(* Logix 5000 project; controller Electronic_Displays vendor 1 type 14 code 65 rev 17.4; software revision 17.01; part 2 of 8 *)

ADD_ON_INSTRUCTION ResetSign   (* revision 1.0, ExecuteEnableInFalse *)
// Reset Sign
// Erases All
// Variable Memory
// Revision note:
// Original Release
// 11-01-2012
// c.elston
VAR_IN_OUT
   Address : STRING; {required}   // "00" = all signs "01" = address 01 "02" = address 02 etc...(see protocol)
END_VAR
VAR_OUTPUT
   EN : BOOL; {visible}   // Instruction Interface Enable Bit
   DN : BOOL; {visible}   // Instruction Interface Done Bit
   ER : BOOL; {visible}   // Instruction Interface Error Bit
   IP : BOOL; {visible}   // Instruction Interface InProcess Bit
END_VAR
VAR_IN_OUT
   map_SignInput : SINT[32]; {required}   // Ethernet/IP LEDSIGN.I Data I/O Mapping
   map_SignOutput : SINT[496]; {required}   // Ethernet/IP LEDSIGN.O Data I/O Mapping
   Packet1Sent : STRING; {required}   // The actual packet sent to the sign (Packet1)
   Packet2Sent : STRING; {required}   // The actual packet sent to the sign (Packet2)
   Packet3Sent : STRING; {required}   // The actual packet sent to the sign (Packet3)
END_VAR
VAR
   SEQ : DINT;   // Sequence Number
   OktoCycle : BOOL;   // Ok to Cycle
   InCycle : BOOL;   // Incycle
   Error : BOOL;   // Error
   Enabled : BOOL;   // Enable ON Bit
   Done : BOOL;   // Done
   Disabled : BOOL;   // Disabled OFF Bit
   SignETX : STRING := '^C';   // DO NOT EDIT = ^C
   SignFileLabel : STRING;
   SignSOH : STRING := '^A';   // DO NOT EDIT = ^A
   SignAddress : STRING;
   SignSTX : STRING := '^B';   // DO NOT EDIT = ^B
   SignNULL : STRING;
   SignResetMemoryCommand : STRING := 'CM';   // DO NOT EDIT = SM
   SignCommandCode : STRING := 'C';   // DO NOT EDIT = C
   TotalPacketCount : DINT[7];   // Total Character Count
   Select : DINT;   // Packet Array Select
   PacketMax : DINT := 82;   // Max Packet Count
   PacketCount : DINT[7];
   Packet6Offset : DINT;
   Packet5Offset : DINT;
   Packet4Offset : DINT;
   Packet3Offset : DINT;
   Packet2Offset : DINT;
   Packet1Offset : DINT;
   Packet : STRING[7];   // Packet Array to send to sign
END_VAR

ROUTINE EnableInFalse   (* ladder *)
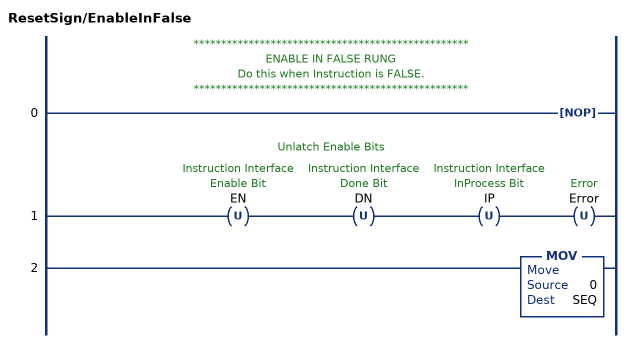
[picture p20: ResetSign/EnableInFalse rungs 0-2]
   // **************************************************
   // ENABLE IN FALSE RUNG
   // Do this when Instruction is FALSE.
   // **************************************************
   0: NOP();
   // Unlatch Enable Bits
   1: OTU(EN)OTU(DN)OTU(IP)OTU(Error);
   2: MOV(0,SEQ);
END_ROUTINE

ROUTINE Logic   (* ladder *)
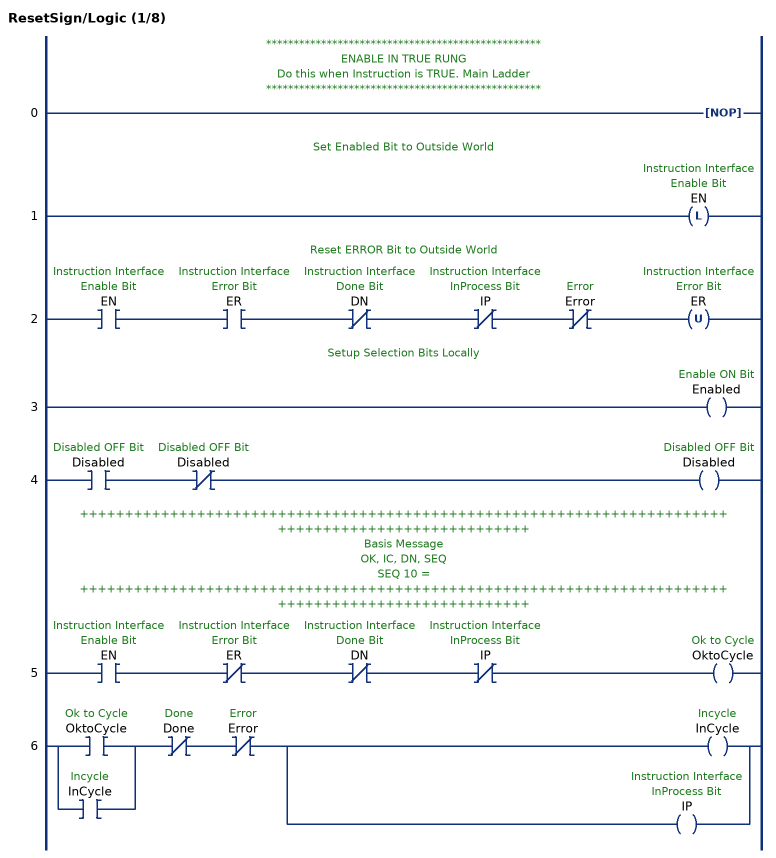
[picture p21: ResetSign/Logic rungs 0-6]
   // **************************************************
   // ENABLE IN TRUE RUNG
   // Do this when Instruction is TRUE. Main Ladder
   // **************************************************
   0: NOP();
   // Set Enabled Bit to Outside World
   1: OTL(EN);
   // Reset ERROR Bit to Outside World
   2: XIC(EN)XIC(ER)XIO(DN)XIO(IP)XIO(Error)OTU(ER);
   // Setup Selection Bits Locally
   3: OTE(Enabled);
   4: XIC(Disabled)XIO(Disabled)OTE(Disabled);
   // ++++++++++++++++++++++++++++++++++++++++++++++++++++++++++++++++++++++++++++++++++++++++++++++++++++
   // Basis Message
   // OK, IC, DN, SEQ
   // SEQ 10 =
   // ++++++++++++++++++++++++++++++++++++++++++++++++++++++++++++++++++++++++++++++++++++++++++++++++++++
   5: XIC(EN)XIO(ER)XIO(DN)XIO(IP)OTE(OktoCycle);
   6: [XIC(OktoCycle) ,XIC(InCycle) ]XIO(Done)XIO(Error)[OTE(InCycle) ,OTE(IP) ];
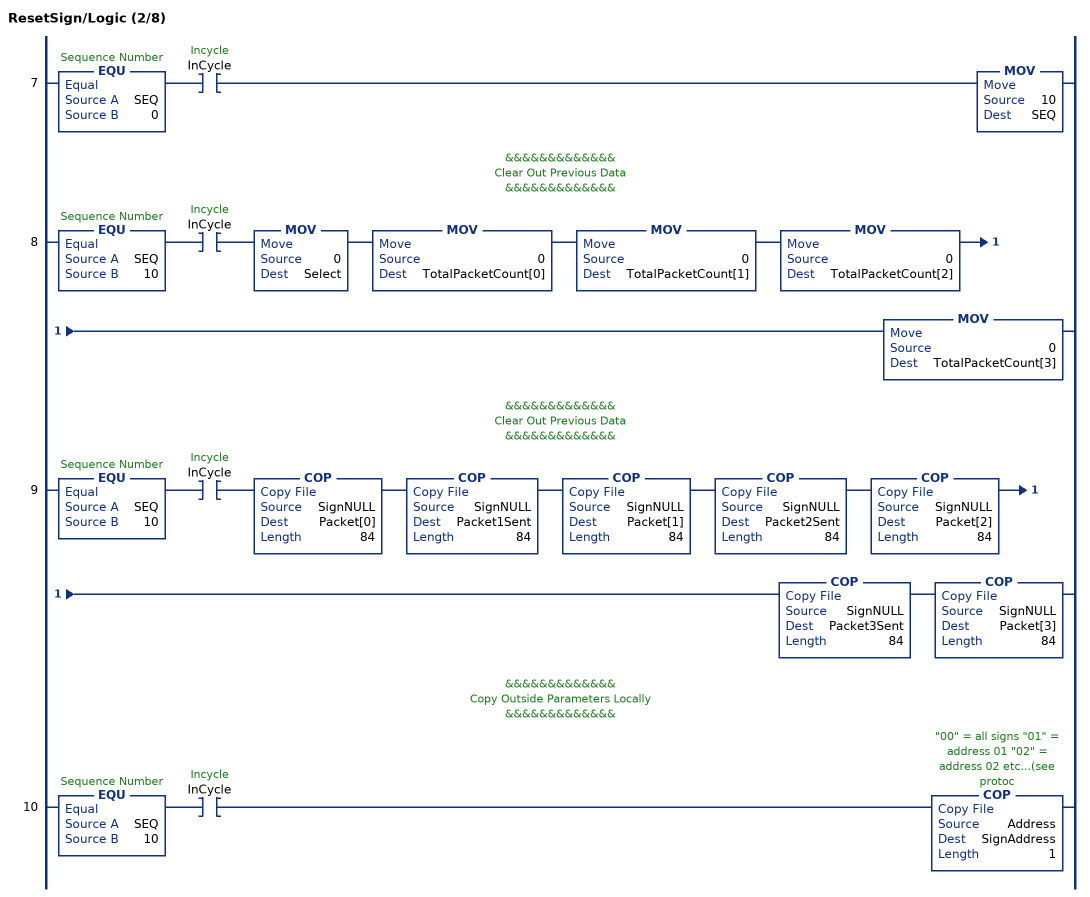
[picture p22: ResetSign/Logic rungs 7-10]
   7: EQU(SEQ,0)XIC(InCycle)MOV(10,SEQ);
   // &&&&&&&&&&&&&
   // Clear Out Previous Data
   // &&&&&&&&&&&&&
   8: EQU(SEQ,10)XIC(InCycle)MOV(0,Select)MOV(0,TotalPacketCount[0])MOV(0,TotalPacketCount[1])MOV(0,TotalPacketCount[2])MOV(0,TotalPacketCount[3]);
   // &&&&&&&&&&&&&
   // Clear Out Previous Data
   // &&&&&&&&&&&&&
   9: EQU(SEQ,10)XIC(InCycle)COP(SignNULL,Packet[0],84)COP(SignNULL,Packet1Sent,84)COP(SignNULL,Packet[1],84)COP(SignNULL,Packet2Sent,84)COP(SignNULL,Packet[2],84)COP(SignNULL,Packet3Sent,84)COP(SignNULL,Packet[3],84);
   // &&&&&&&&&&&&&
   // Copy Outside Parameters Locally
   // &&&&&&&&&&&&&
   10: EQU(SEQ,10)XIC(InCycle)COP(Address,SignAddress,1);
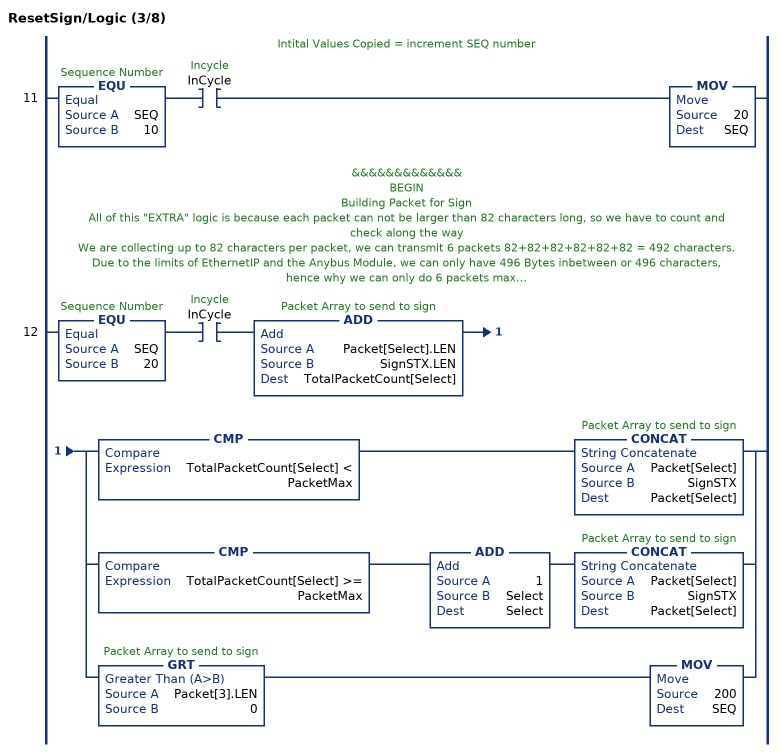
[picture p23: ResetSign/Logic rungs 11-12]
   // Intital Values Copied = increment SEQ number
   11: EQU(SEQ,10)XIC(InCycle)MOV(20,SEQ);
   // &&&&&&&&&&&&&
   // BEGIN
   // Building Packet for Sign
   // All of this "EXTRA" logic is because each packet can not be larger than 82 characters long, so we have to count and check along the way
   // We are collecting up to 82 characters per packet, we can transmit 6 packets 82+82+82+82+82+82 = 492 characters.
   // Due to the limits of EthernetIP and the Anybus Module, we can only have 496 Bytes inbetween or 496 characters, hence why we can only do 6 packets max.
   // Once we exceed this, we will fault and ERROR trap any windy typing people.
   // In this instruction below, it's so small, we are only using 3 packets max.
   // &&&&&&&&&&&&&
   12: EQU(SEQ,20)XIC(InCycle)ADD(Packet[Select].LEN,SignSTX.LEN,TotalPacketCount[Select])[CMP(TotalPacketCount[Select] < PacketMax) CONCAT(Packet[Select],SignSTX,Packet[Select]) ,CMP(TotalPacketCount[Select] >= PacketMax) ADD(1,Select,Select) CONCAT(Packet[Select],SignSTX,Packet[Select]) ,GRT(Packet[3].LEN,0) MOV(200,SEQ) ];
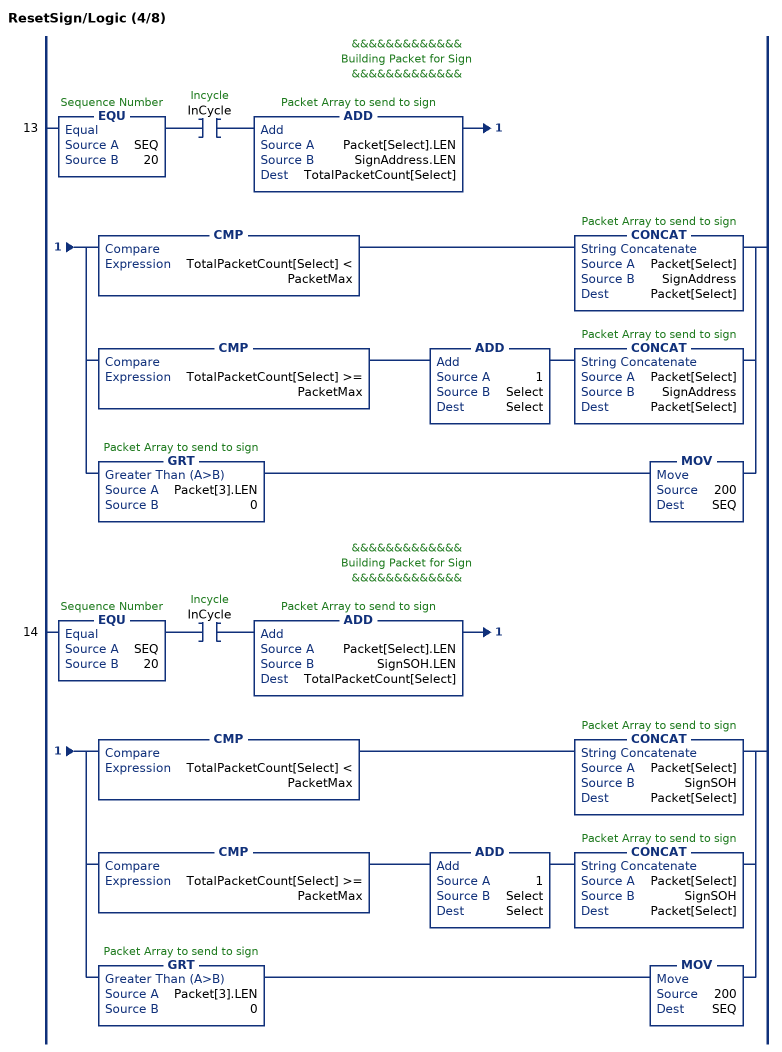
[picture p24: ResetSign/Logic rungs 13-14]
   // &&&&&&&&&&&&&
   // Building Packet for Sign
   // &&&&&&&&&&&&&
   13: EQU(SEQ,20)XIC(InCycle)ADD(Packet[Select].LEN,SignAddress.LEN,TotalPacketCount[Select])[CMP(TotalPacketCount[Select] < PacketMax) CONCAT(Packet[Select],SignAddress,Packet[Select]) ,CMP(TotalPacketCount[Select] >= PacketMax) ADD(1,Select,Select) CONCAT(Packet[Select],SignAddress,Packet[Select]) ,GRT(Packet[3].LEN,0) MOV(200,SEQ) ];
   // &&&&&&&&&&&&&
   // Building Packet for Sign
   // &&&&&&&&&&&&&
   14: EQU(SEQ,20)XIC(InCycle)ADD(Packet[Select].LEN,SignSOH.LEN,TotalPacketCount[Select])[CMP(TotalPacketCount[Select] < PacketMax) CONCAT(Packet[Select],SignSOH,Packet[Select]) ,CMP(TotalPacketCount[Select] >= PacketMax) ADD(1,Select,Select) CONCAT(Packet[Select],SignSOH,Packet[Select]) ,GRT(Packet[3].LEN,0) MOV(200,SEQ) ];
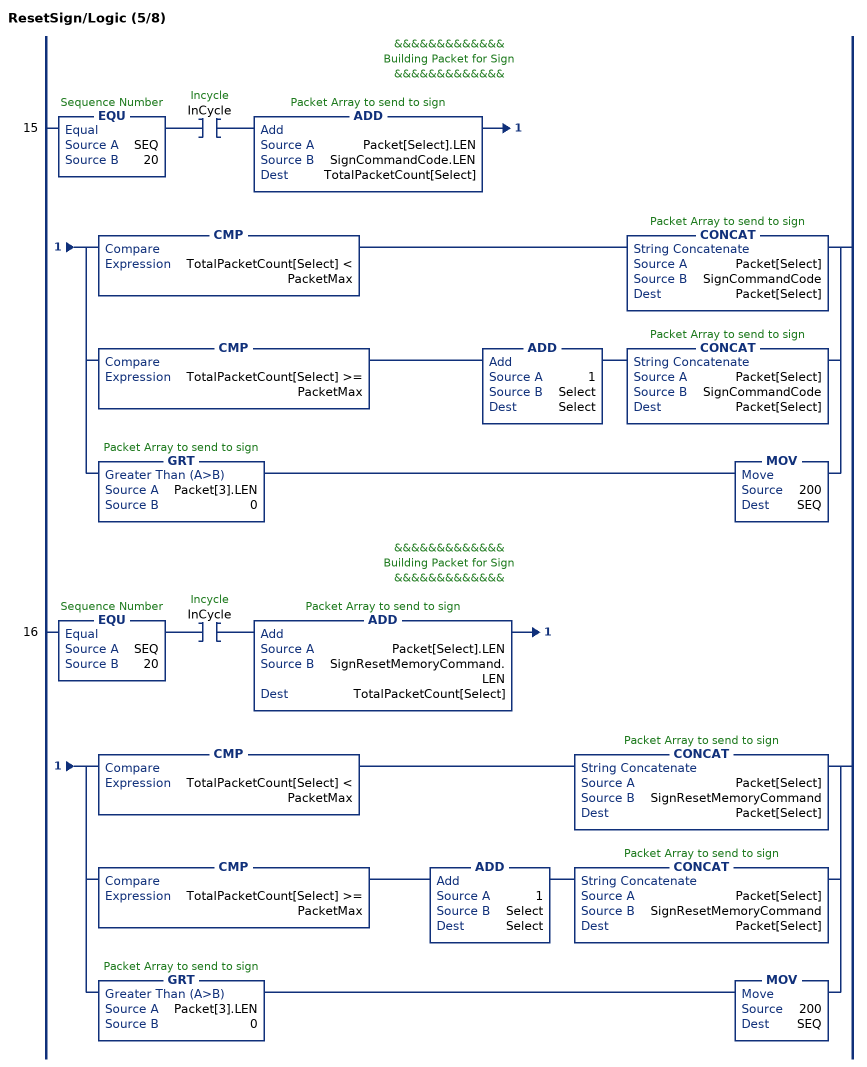
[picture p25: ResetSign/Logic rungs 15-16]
   // &&&&&&&&&&&&&
   // Building Packet for Sign
   // &&&&&&&&&&&&&
   15: EQU(SEQ,20)XIC(InCycle)ADD(Packet[Select].LEN,SignCommandCode.LEN,TotalPacketCount[Select])[CMP(TotalPacketCount[Select] < PacketMax) CONCAT(Packet[Select],SignCommandCode,Packet[Select]) ,CMP(TotalPacketCount[Select] >= PacketMax) ADD(1,Select,Select) CONCAT(Packet[Select],SignCommandCode,Packet[Select]) ,GRT(Packet[3].LEN,0) MOV(200,SEQ) ];
   // &&&&&&&&&&&&&
   // Building Packet for Sign
   // &&&&&&&&&&&&&
   16: EQU(SEQ,20)XIC(InCycle)ADD(Packet[Select].LEN,SignResetMemoryCommand.LEN,TotalPacketCount[Select])[CMP(TotalPacketCount[Select] < PacketMax) CONCAT(Packet[Select],SignResetMemoryCommand,Packet[Select]) ,CMP(TotalPacketCount[Select] >= PacketMax) ADD(1,Select,Select) CONCAT(Packet[Select],SignResetMemoryCommand,Packet[Select]) ,GRT(Packet[3].LEN,0) MOV(200,SEQ) ];
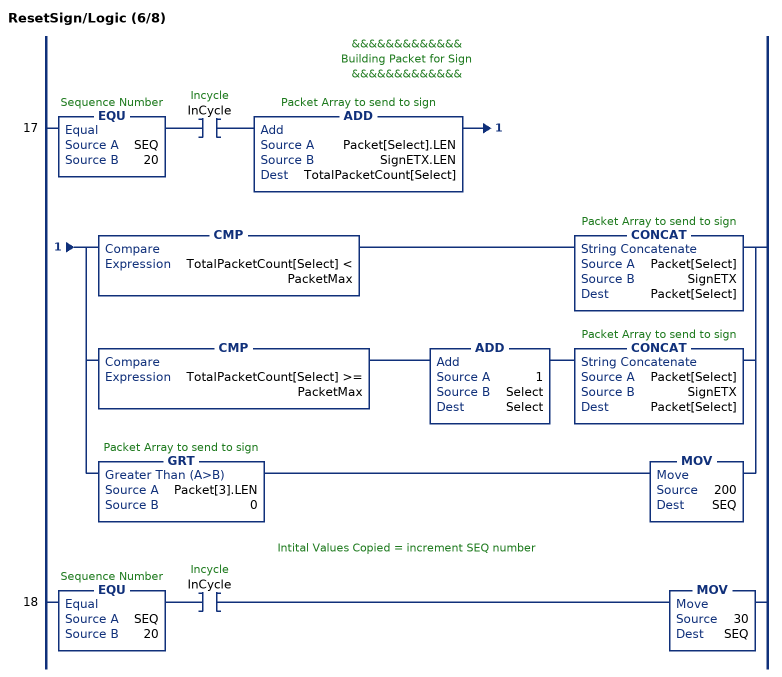
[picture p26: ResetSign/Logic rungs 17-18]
   // &&&&&&&&&&&&&
   // Building Packet for Sign
   // &&&&&&&&&&&&&
   17: EQU(SEQ,20)XIC(InCycle)ADD(Packet[Select].LEN,SignETX.LEN,TotalPacketCount[Select])[CMP(TotalPacketCount[Select] < PacketMax) CONCAT(Packet[Select],SignETX,Packet[Select]) ,CMP(TotalPacketCount[Select] >= PacketMax) ADD(1,Select,Select) CONCAT(Packet[Select],SignETX,Packet[Select]) ,GRT(Packet[3].LEN,0) MOV(200,SEQ) ];
   // Intital Values Copied = increment SEQ number
   18: EQU(SEQ,20)XIC(InCycle)MOV(30,SEQ);
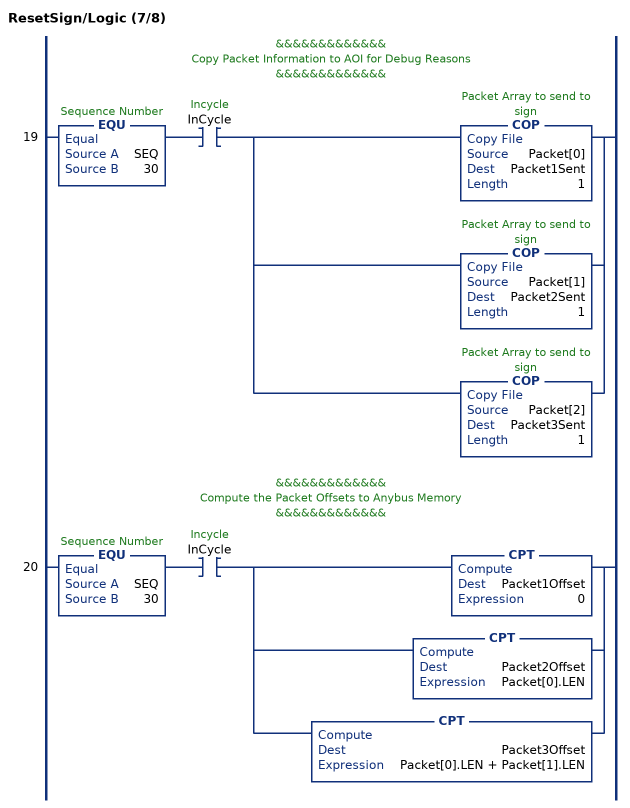
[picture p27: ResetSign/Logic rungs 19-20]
   // &&&&&&&&&&&&&
   // Copy Packet Information to AOI for Debug Reasons
   // &&&&&&&&&&&&&
   19: EQU(SEQ,30)XIC(InCycle)[COP(Packet[0],Packet1Sent,1) ,COP(Packet[1],Packet2Sent,1) ,COP(Packet[2],Packet3Sent,1) ];
   // &&&&&&&&&&&&&
   // Compute the Packet Offsets to Anybus Memory
   // &&&&&&&&&&&&&
   20: EQU(SEQ,30)XIC(InCycle)[CPT(Packet1Offset,0) ,CPT(Packet2Offset,Packet[0].LEN) ,CPT(Packet3Offset,Packet[0].LEN + Packet[1].LEN) ];
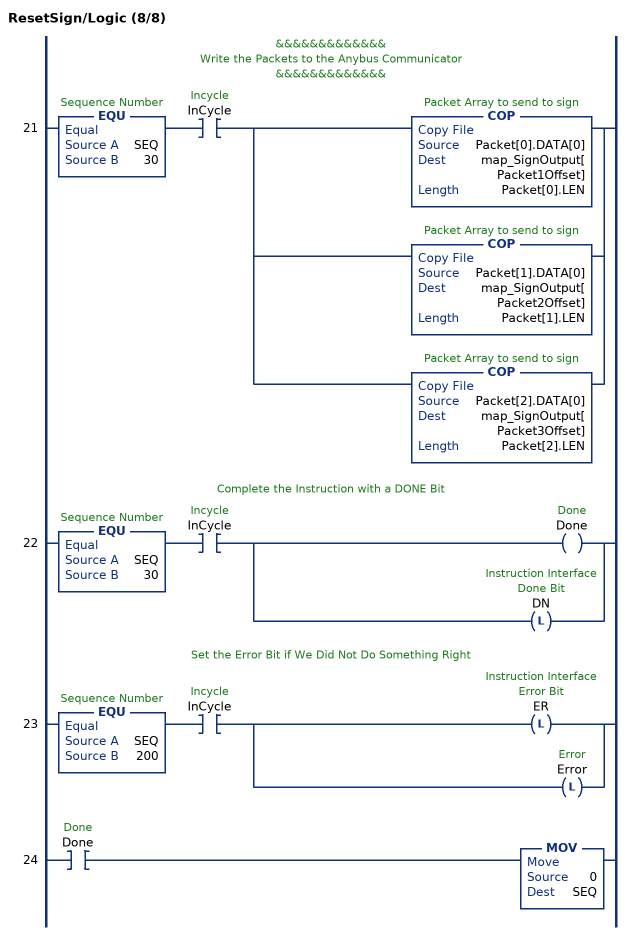
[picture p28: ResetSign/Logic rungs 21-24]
   // &&&&&&&&&&&&&
   // Write the Packets to the Anybus Communicator
   // &&&&&&&&&&&&&
   21: EQU(SEQ,30)XIC(InCycle)[COP(Packet[0].DATA[0],map_SignOutput[Packet1Offset],Packet[0].LEN) ,COP(Packet[1].DATA[0],map_SignOutput[Packet2Offset],Packet[1].LEN) ,COP(Packet[2].DATA[0],map_SignOutput[Packet3Offset],Packet[2].LEN) ];
   // Complete the Instruction with a DONE Bit
   22: EQU(SEQ,30)XIC(InCycle)[OTE(Done) ,OTL(DN) ];
   // Set the Error Bit if We Did Not Do Something Right
   23: EQU(SEQ,200)XIC(InCycle)[OTL(ER) ,OTL(Error) ];
   24: XIC(Done)MOV(0,SEQ);
END_ROUTINE
END_ADD_ON_INSTRUCTION

ADD_ON_INSTRUCTION SendSignMessage   (* revision 1.0, ExecuteEnableInFalse *)
// Send up to
// Four Lines
// to LED Sign
// Revision note:
// Original Release
// 11-01-2012
// c.elston
VAR_IN_OUT
   Address : STRING; {required}   // "00" = all signs "01" = address 01 "02" = address 02 etc...(see protocol)
   CommandCode : STRING; {required}   // "A" = text "B" = variable "C" = special "D" = text,norestart etc...(see protocol)
   FileLabel : STRING; {required}   // "A" = default etc...(see protocol)
END_VAR
VAR_INPUT
   ENText1Message : BOOL; {visible}   // 0 = don't sent message 1 = send message
END_VAR
VAR_IN_OUT
   Text1Message : STRING; {required}   // Actual Text Message to be Written to Screen (Line 1) 4 x 1 configuration
END_VAR
VAR_INPUT
   ENText2Message : BOOL; {visible}   // 0 = don't sent message 1 = send message
END_VAR
VAR_IN_OUT
   Text2Message : STRING; {required}   // Actual Text Message to be Written to Screen (Line 2) 4 x 1 configuration
END_VAR
VAR_INPUT
   ENText3Message : BOOL; {visible}   // 0 = don't sent message 1 = send message
END_VAR
VAR_IN_OUT
   Text3Message : STRING; {required}   // Actual Text Message to be Written to Screen (Line 3) 4 x 1 configuration
END_VAR
VAR_INPUT
   ENText4Message : BOOL; {visible}   // 0 = don't sent message 1 = send message
END_VAR
VAR_IN_OUT
   Text4Message : STRING; {required}   // Actual Text Message to be Written to Screen (Line 4) 4 x 1 configuration
END_VAR
VAR_INPUT
   ENTextFormats : BOOL; {visible}   // 0 = no additional text formatting 1 = enable text formatting
END_VAR
VAR_IN_OUT
   TextFont : STRING; {required}   // "0" = default "1" = SF7 "2" = SF10 "3" = SS16 "4" = SF16
   TextColor : STRING; {required}   // "0" = Red (default) "1" = Green "2" = Yellow "3" = Rainbow1
   TextAlign : STRING; {required}   // "M"=middle line "T"=top line "B"=bottom line "F"=fill (best for variables) "L"=left "R"=right
   TextAttribute : STRING; {required}   // "0"=flashing off "1"=flashing on "2"=wide off "3"=wide on "4"=bold off "5"=bold on
END_VAR
VAR_INPUT
   ENTextSpecials : BOOL; {visible}   // 0 = no additional text special formatting 1 = enable text special formatting
END_VAR
VAR_IN_OUT
   TextEffect : STRING; {required}   // "S"=scrolls "H"=hold "F"=flash "A"=slide up "B"=slide down "C"=slide left "D"=slide right "a"=roll up "b"=roll down "c"=roll left "d"=roll right
   TextSpeed : STRING; {required}   // 1 - 8 "3" = Default (see protocol)
   TextPause : STRING; {required}   // 00 - 99 "02" = Default (see protocol) [must be two digits] if not will not work!
END_VAR
VAR_INPUT
   ENVariable1Message : BOOL; {visible}   // 0 = don't sent embedded variable 1 = send embedded variable
END_VAR
VAR_IN_OUT
   Variable1Name : STRING; {required}   // Name of variable Default is = U
END_VAR
VAR_INPUT
   ENVariable2Message : BOOL; {visible}   // 0 = don't sent embedded variable 1 = send embedded variable
END_VAR
VAR_IN_OUT
   Variable2Name : STRING; {required}   // Name of variable Default is = V
END_VAR
VAR_INPUT
   ENVariable3Message : BOOL; {visible}   // 0 = don't sent embedded variable 1 = send embedded variable
END_VAR
VAR_IN_OUT
   Variable3Name : STRING; {required}   // Name of variable Default is = W
END_VAR
VAR_INPUT
   ENVariable4Message : BOOL; {visible}   // 0 = don't sent embedded variable 1 = send embedded variable
END_VAR
VAR_IN_OUT
   Variable4Name : STRING; {required}   // Name of variable Default is = X
END_VAR
VAR_INPUT
   ENVariableFormats : BOOL; {visible}   // 0 = no additional text formatting 1 = enable text formatting
END_VAR
VAR_IN_OUT
   VariableFont : STRING; {required}   // "0" = default "1" = SF7 "2" = SF10 "3" = SS16 "4" = SF16 etc...(see protocol)
   VariableColor : STRING; {required}   // "0" = Red (default) "1" = Green "2" = Yellow "3" = Rainbow1
   VariableAttribute : STRING; {required}   // "0"=flashing off "1"=flashing on "2"=wide off "3"=wide on "4"=bold off "5"=bold on
END_VAR
VAR_OUTPUT
   EN : BOOL; {visible}   // Instruction Interface Enable Bit
   DN : BOOL; {visible}   // Instruction Interface Done Bit
   IP : BOOL; {visible}   // Instruction Interface InProcess Bit
   ER : BOOL; {visible}   // Instruction Interface Error Bit
END_VAR
VAR_IN_OUT
   map_SignInput : SINT[32]; {required}   // Ethernet/IP LEDSIGN.I Data I/O Mapping
   map_SignOutput : SINT[496]; {required}   // Ethernet/IP LEDSIGN.O Data I/O Mapping
   Packet1Sent : STRING; {required}   // The actual packet sent to the sign (Packet1)
   Packet2Sent : STRING; {required}   // The actual packet sent to the sign (Packet2)
   Packet3Sent : STRING; {required}   // The actual packet sent to the sign (Packet3)
   Packet4Sent : STRING; {required}   // The actual packet sent to the sign (Packet4)
   Packet5Sent : STRING; {required}   // The actual packet sent to the sign (Packet5)
   Packet6Sent : STRING; {required}   // The actual packet sent to the sign (Packet6)
END_VAR
VAR
   SEQ : DINT;   // Sequence Number
   OktoCycle : BOOL;   // Ok to Cycle
   InCycle : BOOL;   // Incycle
   Error : BOOL;   // Error
   Enabled : BOOL;   // Enable ON Bit
   Done : BOOL;   // Done
   Disabled : BOOL;   // Disabled OFF Bit
   SignETX : STRING := '^C';   // DO NOT EDIT = ^C
   SignTextMessage1 : STRING;
   SignColor : STRING;
   SignFont : STRING;
   SignFileLabel : STRING;
   SignCommandCode : STRING;
   SignSOH : STRING := '^A';   // DO NOT EDIT = ^A
   SignAddress : STRING;
   SignSTX : STRING := '^B';   // DO NOT EDIT = ^B
   Packet : STRING[7];   // Packet Array to send to sign
   SignFontCommand : STRING := '^F';   // DO NOT EDIT = ^F
   SignColorCommand : STRING := '^O';   // DO NOT EDIT = ^O
   SignAlignCommand : STRING := '^G';   // DO NOT EDIT = ^G
   SignAlign : STRING;
   SignSpeedCommand : STRING := '^I';   // DO NOT EDIT = ^I
   SignSpeed : STRING;
   SignEffectCommand : STRING := '^E';   // DO NOT EDIT = ^E
   SignEffect : STRING;
   SignPauseCommand : STRING := '^J';   // DO NOT EDIT = ^J
   SignPause : STRING;
   SignTextMessage4 : STRING;
   SignTextMessage3 : STRING;
   SignTextMessage2 : STRING;
   SignNextLine : STRING := '^M';   // DO NOT EDIT = ^M
   SignNULL : STRING;
   SignVariableFont : STRING;
   SignVariableColor : STRING;
   SignVariable4 : STRING;
   SignVariable3 : STRING;
   SignVariable2 : STRING;
   SignVariable1 : STRING;
   SignVariableCommand : STRING := '^N';   // DO NOT EDIT = ^N
   Select : DINT;   // Packet Array Select
   TotalPacketCount : DINT[7];   // Total Character Count
   PacketMax : DINT := 82;   // Max Packet Count
   PacketCount : DINT[7];
   Packet6Offset : DINT;
   Packet5Offset : DINT;
   Packet4Offset : DINT;
   Packet3Offset : DINT;
   Packet2Offset : DINT;
   Packet1Offset : DINT;
   SignMode2Command : STRING := 'H';   // DO NOT EDIT = H (make it hold)
   SignAttributeCommand : STRING := '^H';   // DO NOT EDIT = ^H
   SignAttribute : STRING;
   SignVariableAttribute : STRING;
END_VAR

ROUTINE EnableInFalse   (* ladder *)
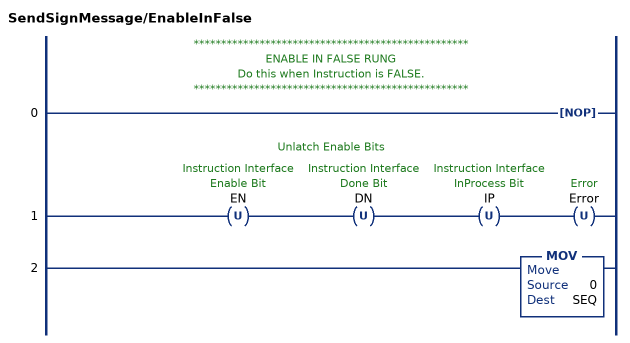
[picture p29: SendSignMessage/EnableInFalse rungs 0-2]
   // **************************************************
   // ENABLE IN FALSE RUNG
   // Do this when Instruction is FALSE.
   // **************************************************
   0: NOP();
   // Unlatch Enable Bits
   1: OTU(EN)OTU(DN)OTU(IP)OTU(Error);
   2: MOV(0,SEQ);
END_ROUTINE

ROUTINE Logic   (* ladder *)
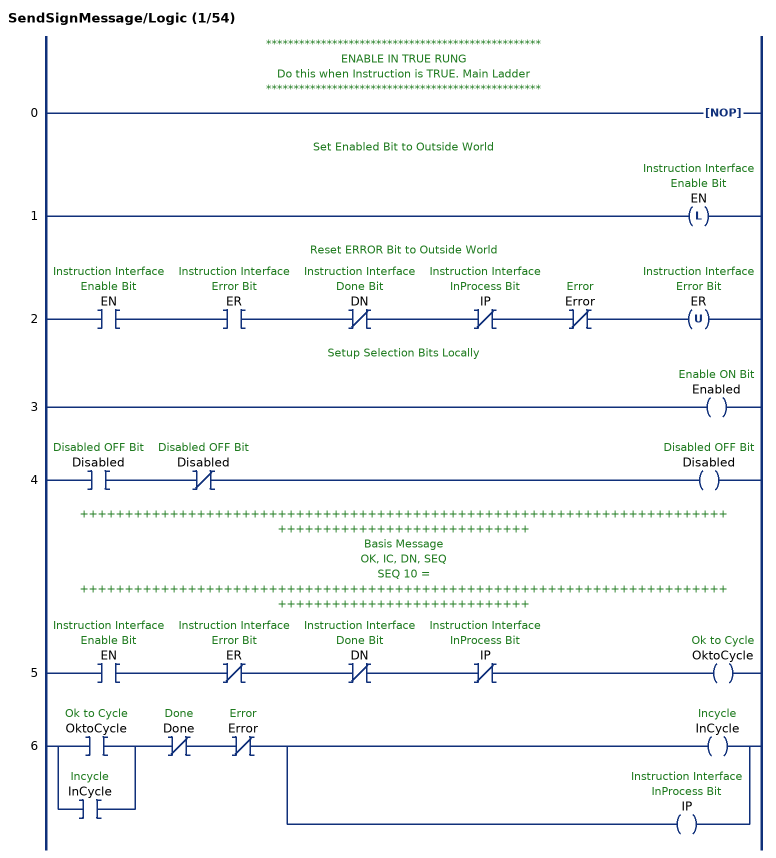
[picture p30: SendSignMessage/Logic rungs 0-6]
   // **************************************************
   // ENABLE IN TRUE RUNG
   // Do this when Instruction is TRUE. Main Ladder
   // **************************************************
   0: NOP();
   // Set Enabled Bit to Outside World
   1: OTL(EN);
   // Reset ERROR Bit to Outside World
   2: XIC(EN)XIC(ER)XIO(DN)XIO(IP)XIO(Error)OTU(ER);
   // Setup Selection Bits Locally
   3: OTE(Enabled);
   4: XIC(Disabled)XIO(Disabled)OTE(Disabled);
   // ++++++++++++++++++++++++++++++++++++++++++++++++++++++++++++++++++++++++++++++++++++++++++++++++++++
   // Basis Message
   // OK, IC, DN, SEQ
   // SEQ 10 =
   // ++++++++++++++++++++++++++++++++++++++++++++++++++++++++++++++++++++++++++++++++++++++++++++++++++++
   5: XIC(EN)XIO(ER)XIO(DN)XIO(IP)OTE(OktoCycle);
   6: [XIC(OktoCycle) ,XIC(InCycle) ]XIO(Done)XIO(Error)[OTE(InCycle) ,OTE(IP) ];
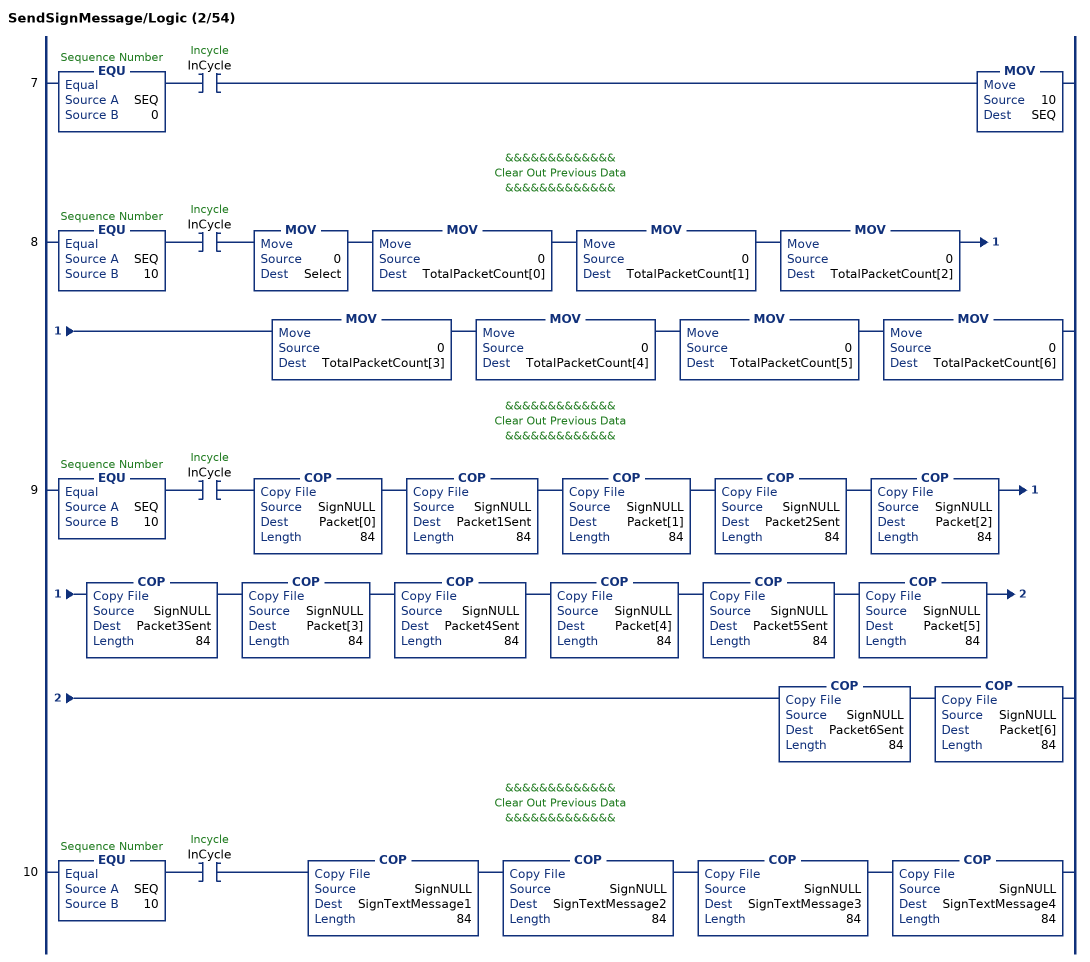
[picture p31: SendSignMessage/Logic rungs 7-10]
   7: EQU(SEQ,0)XIC(InCycle)MOV(10,SEQ);
   // &&&&&&&&&&&&&
   // Clear Out Previous Data
   // &&&&&&&&&&&&&
   8: EQU(SEQ,10)XIC(InCycle)MOV(0,Select)MOV(0,TotalPacketCount[0])MOV(0,TotalPacketCount[1])MOV(0,TotalPacketCount[2])MOV(0,TotalPacketCount[3])MOV(0,TotalPacketCount[4])MOV(0,TotalPacketCount[5])MOV(0,TotalPacketCount[6]);
   // &&&&&&&&&&&&&
   // Clear Out Previous Data
   // &&&&&&&&&&&&&
   9: EQU(SEQ,10)XIC(InCycle)COP(SignNULL,Packet[0],84)COP(SignNULL,Packet1Sent,84)COP(SignNULL,Packet[1],84)COP(SignNULL,Packet2Sent,84)COP(SignNULL,Packet[2],84)COP(SignNULL,Packet3Sent,84)COP(SignNULL,Packet[3],84)COP(SignNULL,Packet4Sent,84)COP(SignNULL,Packet[4],84)COP(SignNULL,Packet5Sent,84)COP(SignNULL,Packet[5],84)COP(SignNULL,Packet6Sent,84)COP(SignNULL,Packet[6],84);
   // &&&&&&&&&&&&&
   // Clear Out Previous Data
   // &&&&&&&&&&&&&
   10: EQU(SEQ,10)XIC(InCycle)COP(SignNULL,SignTextMessage1,84)COP(SignNULL,SignTextMessage2,84)COP(SignNULL,SignTextMessage3,84)COP(SignNULL,SignTextMessage4,84);
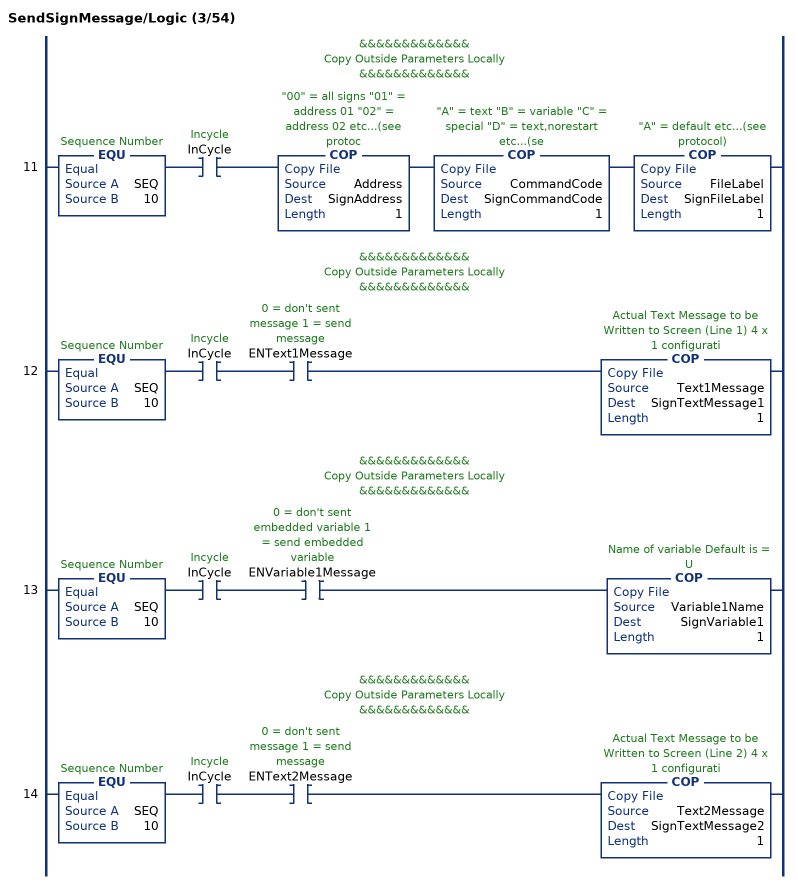
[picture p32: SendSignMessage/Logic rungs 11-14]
   // &&&&&&&&&&&&&
   // Copy Outside Parameters Locally
   // &&&&&&&&&&&&&
   11: EQU(SEQ,10)XIC(InCycle)COP(Address,SignAddress,1)COP(CommandCode,SignCommandCode,1)COP(FileLabel,SignFileLabel,1);
   // &&&&&&&&&&&&&
   // Copy Outside Parameters Locally
   // &&&&&&&&&&&&&
   12: EQU(SEQ,10)XIC(InCycle)XIC(ENText1Message)COP(Text1Message,SignTextMessage1,1);
   // &&&&&&&&&&&&&
   // Copy Outside Parameters Locally
   // &&&&&&&&&&&&&
   13: EQU(SEQ,10)XIC(InCycle)XIC(ENVariable1Message)COP(Variable1Name,SignVariable1,1);
   // &&&&&&&&&&&&&
   // Copy Outside Parameters Locally
   // &&&&&&&&&&&&&
   14: EQU(SEQ,10)XIC(InCycle)XIC(ENText2Message)COP(Text2Message,SignTextMessage2,1);
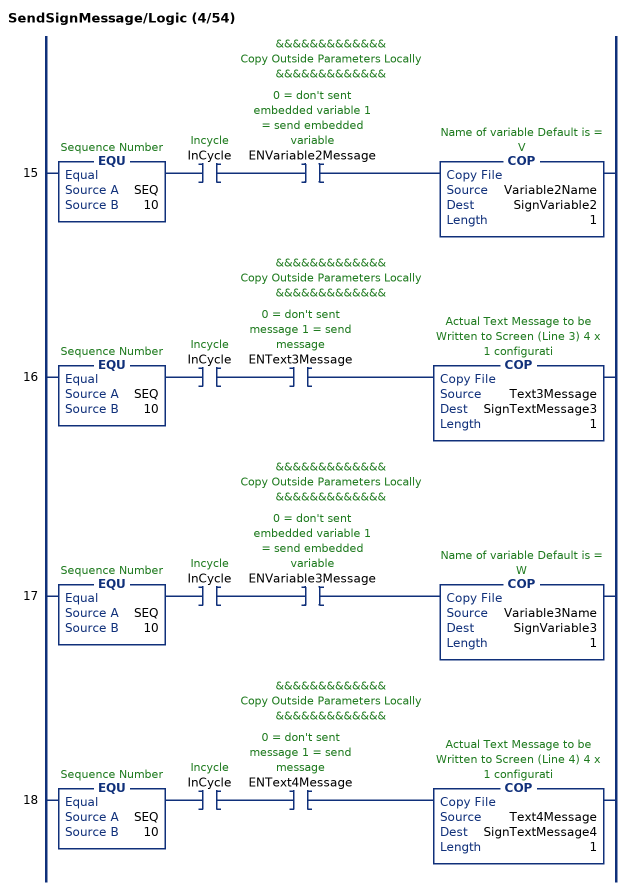
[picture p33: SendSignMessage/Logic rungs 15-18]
   // &&&&&&&&&&&&&
   // Copy Outside Parameters Locally
   // &&&&&&&&&&&&&
   15: EQU(SEQ,10)XIC(InCycle)XIC(ENVariable2Message)COP(Variable2Name,SignVariable2,1);
   // &&&&&&&&&&&&&
   // Copy Outside Parameters Locally
   // &&&&&&&&&&&&&
   16: EQU(SEQ,10)XIC(InCycle)XIC(ENText3Message)COP(Text3Message,SignTextMessage3,1);
   // &&&&&&&&&&&&&
   // Copy Outside Parameters Locally
   // &&&&&&&&&&&&&
   17: EQU(SEQ,10)XIC(InCycle)XIC(ENVariable3Message)COP(Variable3Name,SignVariable3,1);
   // &&&&&&&&&&&&&
   // Copy Outside Parameters Locally
   // &&&&&&&&&&&&&
   18: EQU(SEQ,10)XIC(InCycle)XIC(ENText4Message)COP(Text4Message,SignTextMessage4,1);
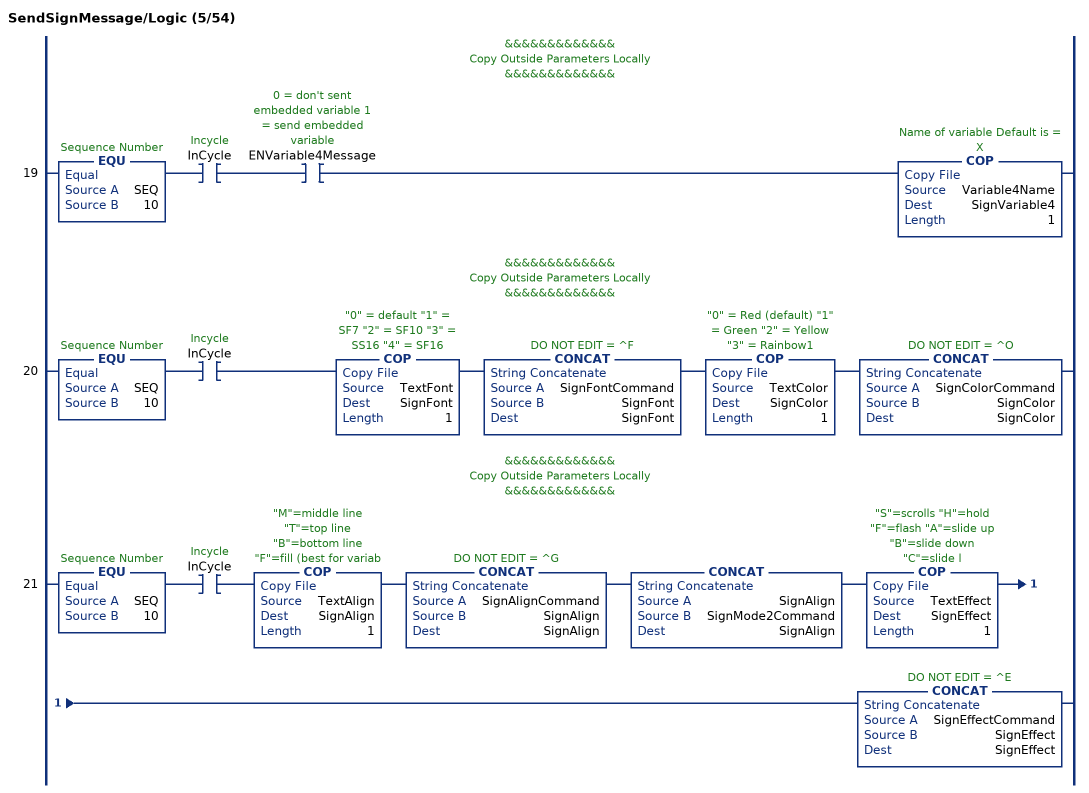
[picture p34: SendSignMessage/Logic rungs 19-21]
   // &&&&&&&&&&&&&
   // Copy Outside Parameters Locally
   // &&&&&&&&&&&&&
   19: EQU(SEQ,10)XIC(InCycle)XIC(ENVariable4Message)COP(Variable4Name,SignVariable4,1);
   // &&&&&&&&&&&&&
   // Copy Outside Parameters Locally
   // &&&&&&&&&&&&&
   20: EQU(SEQ,10)XIC(InCycle)COP(TextFont,SignFont,1)CONCAT(SignFontCommand,SignFont,SignFont)COP(TextColor,SignColor,1)CONCAT(SignColorCommand,SignColor,SignColor);
   // &&&&&&&&&&&&&
   // Copy Outside Parameters Locally
   // &&&&&&&&&&&&&
   21: EQU(SEQ,10)XIC(InCycle)COP(TextAlign,SignAlign,1)CONCAT(SignAlignCommand,SignAlign,SignAlign)CONCAT(SignAlign,SignMode2Command,SignAlign)COP(TextEffect,SignEffect,1)CONCAT(SignEffectCommand,SignEffect,SignEffect);
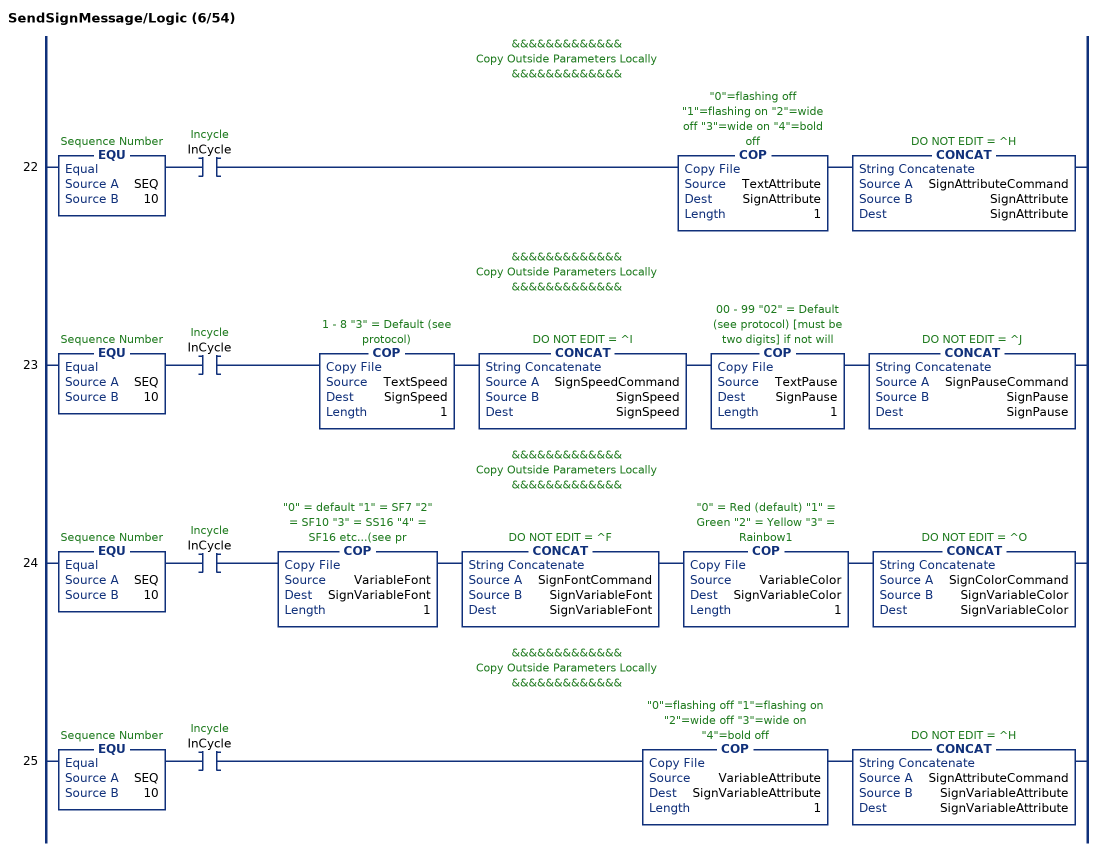
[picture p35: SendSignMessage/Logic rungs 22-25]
   // &&&&&&&&&&&&&
   // Copy Outside Parameters Locally
   // &&&&&&&&&&&&&
   22: EQU(SEQ,10)XIC(InCycle)COP(TextAttribute,SignAttribute,1)CONCAT(SignAttributeCommand,SignAttribute,SignAttribute);
   // &&&&&&&&&&&&&
   // Copy Outside Parameters Locally
   // &&&&&&&&&&&&&
   23: EQU(SEQ,10)XIC(InCycle)COP(TextSpeed,SignSpeed,1)CONCAT(SignSpeedCommand,SignSpeed,SignSpeed)COP(TextPause,SignPause,1)CONCAT(SignPauseCommand,SignPause,SignPause);
   // &&&&&&&&&&&&&
   // Copy Outside Parameters Locally
   // &&&&&&&&&&&&&
   24: EQU(SEQ,10)XIC(InCycle)COP(VariableFont,SignVariableFont,1)CONCAT(SignFontCommand,SignVariableFont,SignVariableFont)COP(VariableColor,SignVariableColor,1)CONCAT(SignColorCommand,SignVariableColor,SignVariableColor);
   // &&&&&&&&&&&&&
   // Copy Outside Parameters Locally
   // &&&&&&&&&&&&&
   25: EQU(SEQ,10)XIC(InCycle)COP(VariableAttribute,SignVariableAttribute,1)CONCAT(SignAttributeCommand,SignVariableAttribute,SignVariableAttribute);
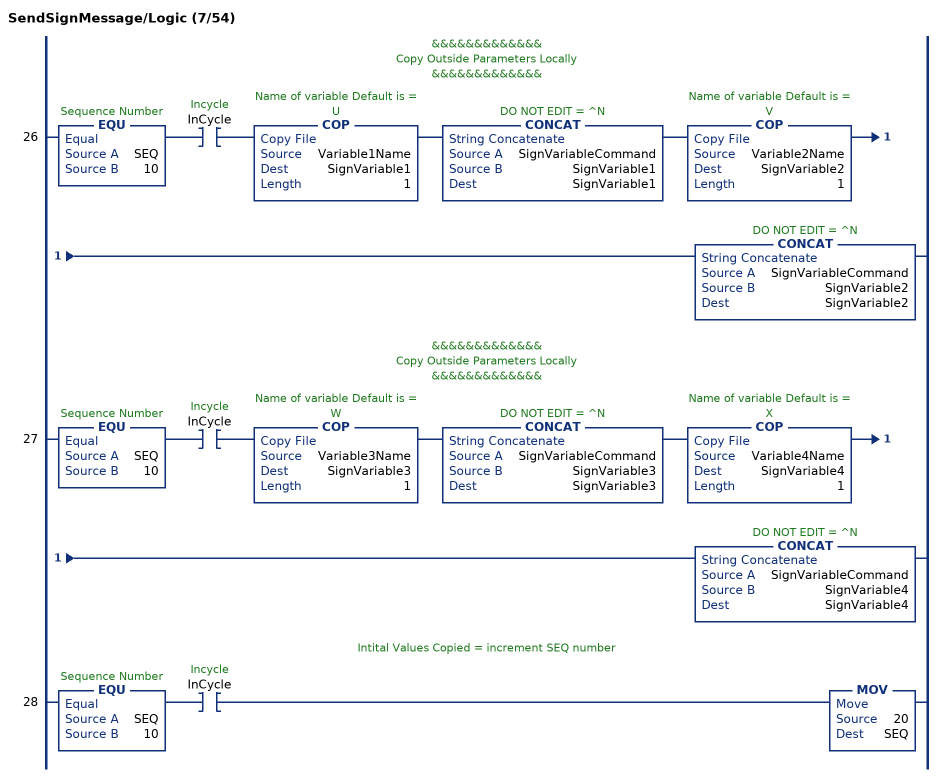
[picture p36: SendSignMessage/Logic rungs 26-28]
   // &&&&&&&&&&&&&
   // Copy Outside Parameters Locally
   // &&&&&&&&&&&&&
   26: EQU(SEQ,10)XIC(InCycle)COP(Variable1Name,SignVariable1,1)CONCAT(SignVariableCommand,SignVariable1,SignVariable1)COP(Variable2Name,SignVariable2,1)CONCAT(SignVariableCommand,SignVariable2,SignVariable2);
   // &&&&&&&&&&&&&
   // Copy Outside Parameters Locally
   // &&&&&&&&&&&&&
   27: EQU(SEQ,10)XIC(InCycle)COP(Variable3Name,SignVariable3,1)CONCAT(SignVariableCommand,SignVariable3,SignVariable3)COP(Variable4Name,SignVariable4,1)CONCAT(SignVariableCommand,SignVariable4,SignVariable4);
   // Intital Values Copied = increment SEQ number
   28: EQU(SEQ,10)XIC(InCycle)MOV(20,SEQ);
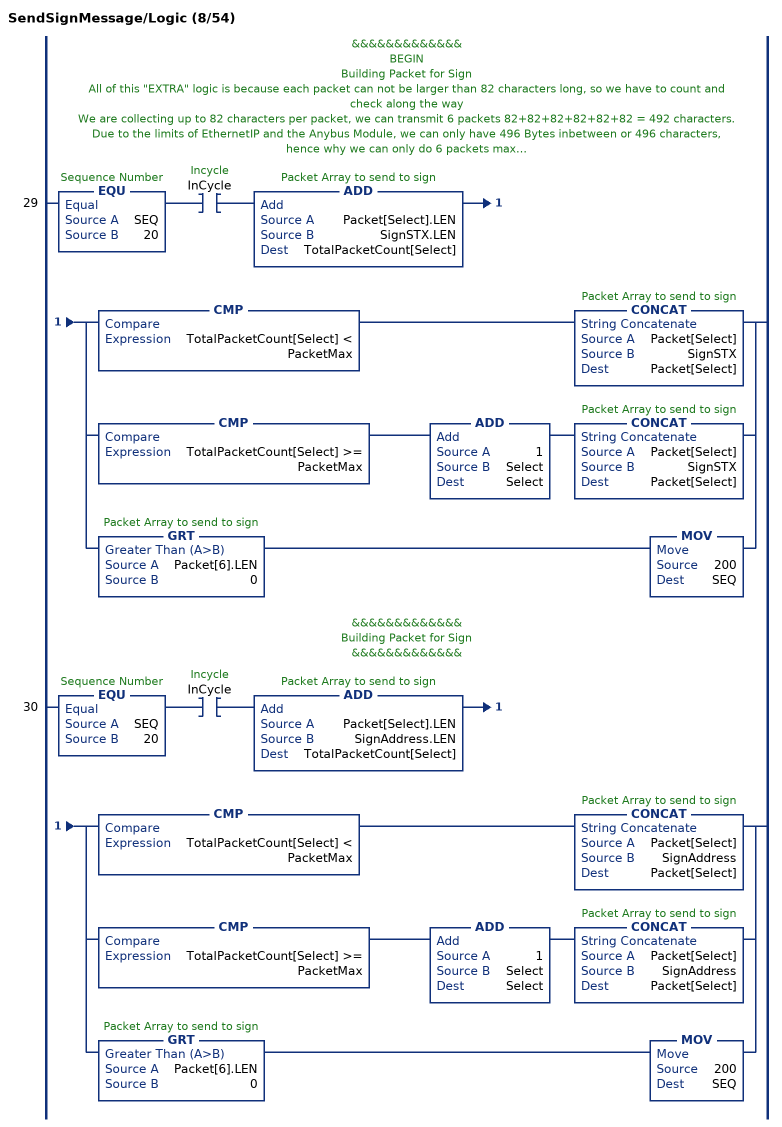
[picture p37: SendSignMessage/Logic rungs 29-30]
   // &&&&&&&&&&&&&
   // BEGIN
   // Building Packet for Sign
   // All of this "EXTRA" logic is because each packet can not be larger than 82 characters long, so we have to count and check along the way
   // We are collecting up to 82 characters per packet, we can transmit 6 packets 82+82+82+82+82+82 = 492 characters.
   // Due to the limits of EthernetIP and the Anybus Module, we can only have 496 Bytes inbetween or 496 characters, hence why we can only do 6 packets max.
   // Once we exceed this, we will fault and ERROR trap any windy typing people.
   // &&&&&&&&&&&&&
   29: EQU(SEQ,20)XIC(InCycle)ADD(Packet[Select].LEN,SignSTX.LEN,TotalPacketCount[Select])[CMP(TotalPacketCount[Select] < PacketMax) CONCAT(Packet[Select],SignSTX,Packet[Select]) ,CMP(TotalPacketCount[Select] >= PacketMax) ADD(1,Select,Select) CONCAT(Packet[Select],SignSTX,Packet[Select]) ,GRT(Packet[6].LEN,0) MOV(200,SEQ) ];
   // &&&&&&&&&&&&&
   // Building Packet for Sign
   // &&&&&&&&&&&&&
   30: EQU(SEQ,20)XIC(InCycle)ADD(Packet[Select].LEN,SignAddress.LEN,TotalPacketCount[Select])[CMP(TotalPacketCount[Select] < PacketMax) CONCAT(Packet[Select],SignAddress,Packet[Select]) ,CMP(TotalPacketCount[Select] >= PacketMax) ADD(1,Select,Select) CONCAT(Packet[Select],SignAddress,Packet[Select]) ,GRT(Packet[6].LEN,0) MOV(200,SEQ) ];
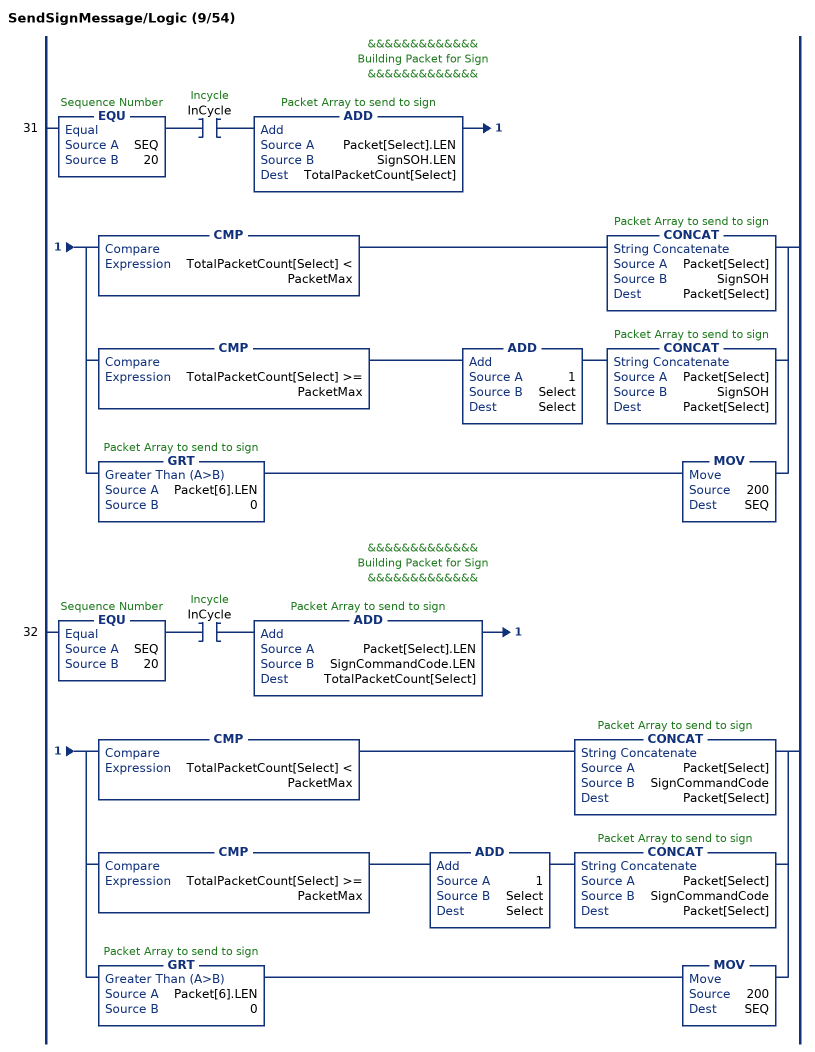
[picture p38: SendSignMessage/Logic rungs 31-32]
   // &&&&&&&&&&&&&
   // Building Packet for Sign
   // &&&&&&&&&&&&&
   31: EQU(SEQ,20)XIC(InCycle)ADD(Packet[Select].LEN,SignSOH.LEN,TotalPacketCount[Select])[CMP(TotalPacketCount[Select] < PacketMax) CONCAT(Packet[Select],SignSOH,Packet[Select]) ,CMP(TotalPacketCount[Select] >= PacketMax) ADD(1,Select,Select) CONCAT(Packet[Select],SignSOH,Packet[Select]) ,GRT(Packet[6].LEN,0) MOV(200,SEQ) ];
   // &&&&&&&&&&&&&
   // Building Packet for Sign
   // &&&&&&&&&&&&&
   32: EQU(SEQ,20)XIC(InCycle)ADD(Packet[Select].LEN,SignCommandCode.LEN,TotalPacketCount[Select])[CMP(TotalPacketCount[Select] < PacketMax) CONCAT(Packet[Select],SignCommandCode,Packet[Select]) ,CMP(TotalPacketCount[Select] >= PacketMax) ADD(1,Select,Select) CONCAT(Packet[Select],SignCommandCode,Packet[Select]) ,GRT(Packet[6].LEN,0) MOV(200,SEQ) ];
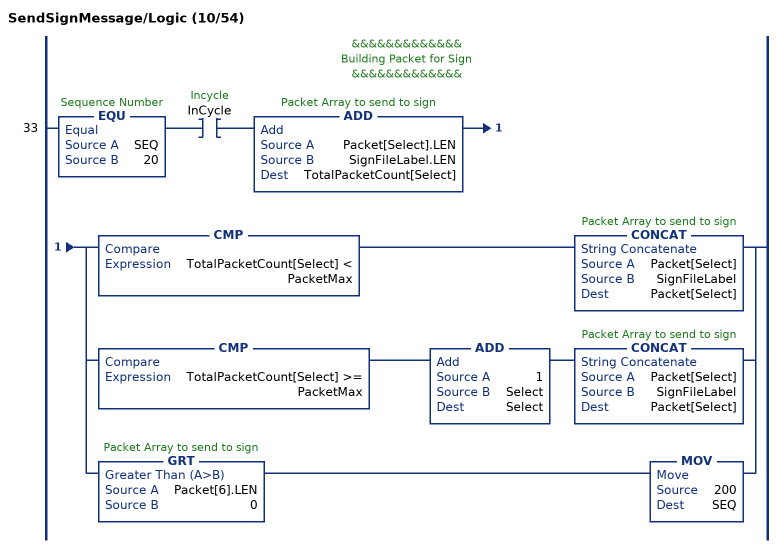
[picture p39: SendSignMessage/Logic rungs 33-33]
   // &&&&&&&&&&&&&
   // Building Packet for Sign
   // &&&&&&&&&&&&&
   33: EQU(SEQ,20)XIC(InCycle)ADD(Packet[Select].LEN,SignFileLabel.LEN,TotalPacketCount[Select])[CMP(TotalPacketCount[Select] < PacketMax) CONCAT(Packet[Select],SignFileLabel,Packet[Select]) ,CMP(TotalPacketCount[Select] >= PacketMax) ADD(1,Select,Select) CONCAT(Packet[Select],SignFileLabel,Packet[Select]) ,GRT(Packet[6].LEN,0) MOV(200,SEQ) ];
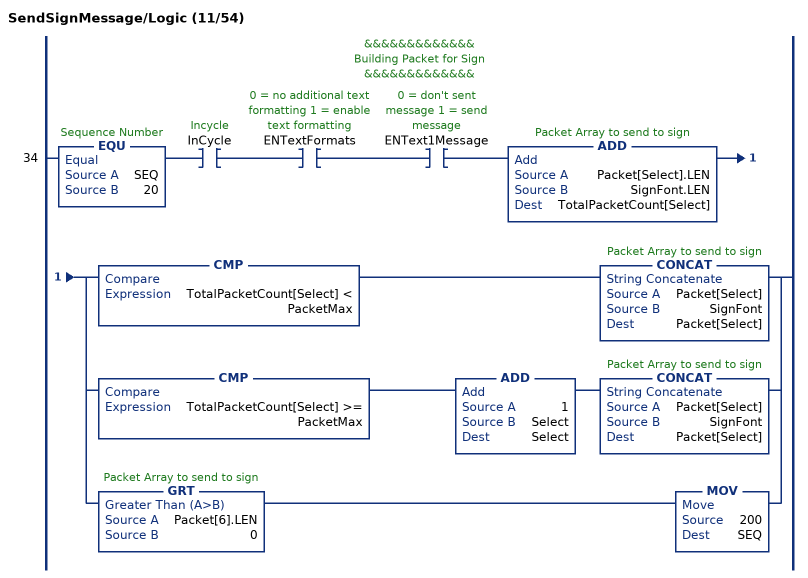
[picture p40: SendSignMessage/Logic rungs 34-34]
   // &&&&&&&&&&&&&
   // Building Packet for Sign
   // &&&&&&&&&&&&&
   34: EQU(SEQ,20)XIC(InCycle)XIC(ENTextFormats)XIC(ENText1Message)ADD(Packet[Select].LEN,SignFont.LEN,TotalPacketCount[Select])[CMP(TotalPacketCount[Select] < PacketMax) CONCAT(Packet[Select],SignFont,Packet[Select]) ,CMP(TotalPacketCount[Select] >= PacketMax) ADD(1,Select,Select) CONCAT(Packet[Select],SignFont,Packet[Select]) ,GRT(Packet[6].LEN,0) MOV(200,SEQ) ];
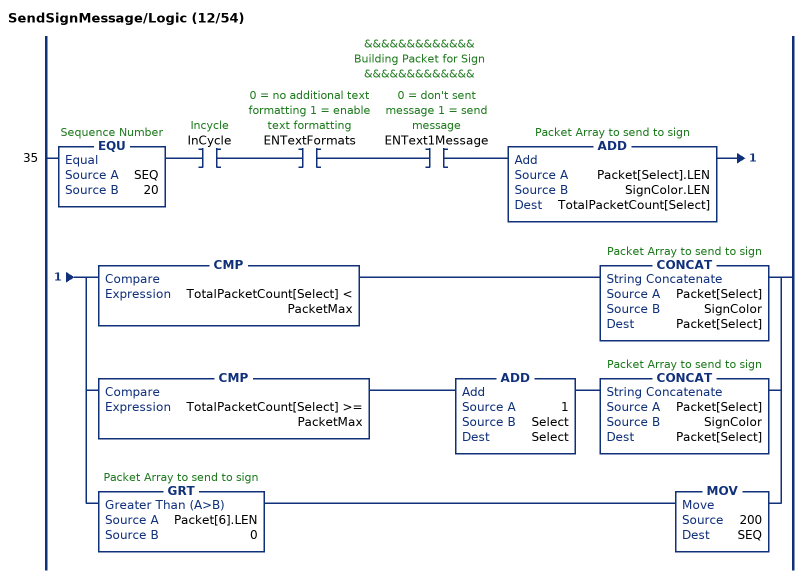
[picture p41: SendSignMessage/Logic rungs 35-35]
   // &&&&&&&&&&&&&
   // Building Packet for Sign
   // &&&&&&&&&&&&&
   35: EQU(SEQ,20)XIC(InCycle)XIC(ENTextFormats)XIC(ENText1Message)ADD(Packet[Select].LEN,SignColor.LEN,TotalPacketCount[Select])[CMP(TotalPacketCount[Select] < PacketMax) CONCAT(Packet[Select],SignColor,Packet[Select]) ,CMP(TotalPacketCount[Select] >= PacketMax) ADD(1,Select,Select) CONCAT(Packet[Select],SignColor,Packet[Select]) ,GRT(Packet[6].LEN,0) MOV(200,SEQ) ];
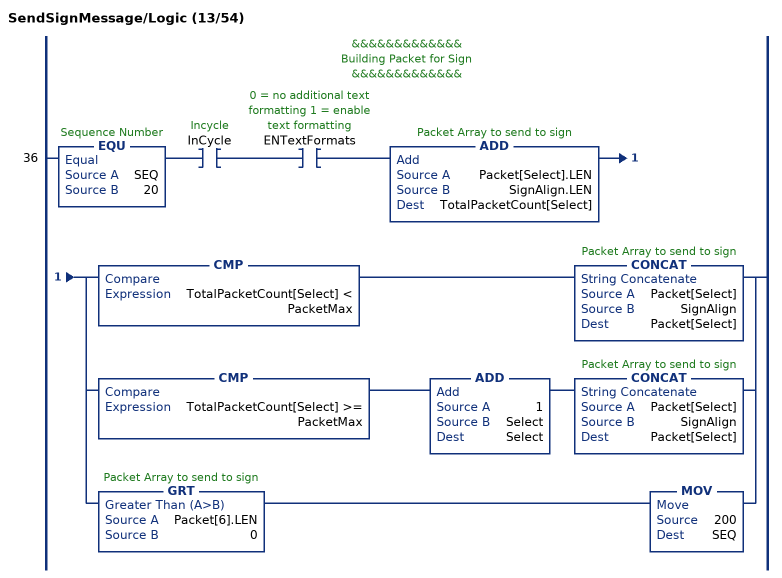
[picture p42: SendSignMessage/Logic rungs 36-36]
   // &&&&&&&&&&&&&
   // Building Packet for Sign
   // &&&&&&&&&&&&&
   36: EQU(SEQ,20)XIC(InCycle)XIC(ENTextFormats)ADD(Packet[Select].LEN,SignAlign.LEN,TotalPacketCount[Select])[CMP(TotalPacketCount[Select] < PacketMax) CONCAT(Packet[Select],SignAlign,Packet[Select]) ,CMP(TotalPacketCount[Select] >= PacketMax) ADD(1,Select,Select) CONCAT(Packet[Select],SignAlign,Packet[Select]) ,GRT(Packet[6].LEN,0) MOV(200,SEQ) ];
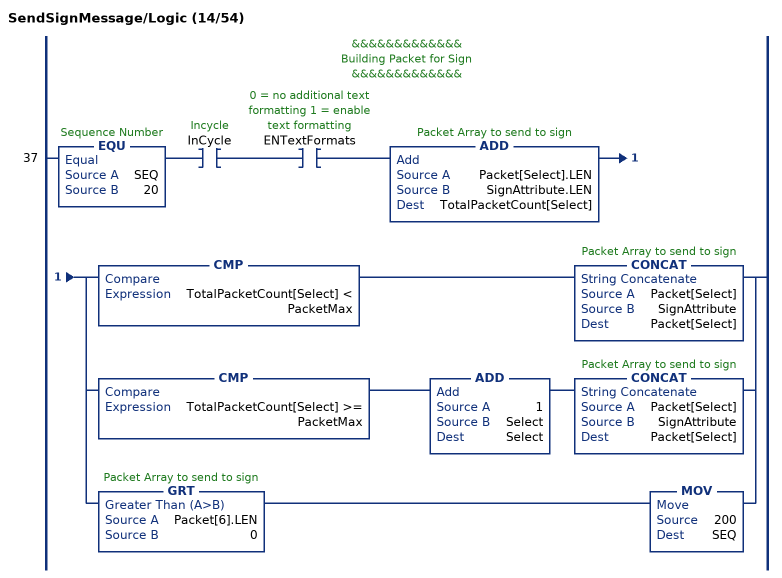
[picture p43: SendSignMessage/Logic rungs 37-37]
   // &&&&&&&&&&&&&
   // Building Packet for Sign
   // &&&&&&&&&&&&&
   37: EQU(SEQ,20)XIC(InCycle)XIC(ENTextFormats)ADD(Packet[Select].LEN,SignAttribute.LEN,TotalPacketCount[Select])[CMP(TotalPacketCount[Select] < PacketMax) CONCAT(Packet[Select],SignAttribute,Packet[Select]) ,CMP(TotalPacketCount[Select] >= PacketMax) ADD(1,Select,Select) CONCAT(Packet[Select],SignAttribute,Packet[Select]) ,GRT(Packet[6].LEN,0) MOV(200,SEQ) ];
(* Logix 5000 project; controller Electronic_Displays vendor 1 type 14 code 65 rev 17.4; software revision 17.01; part 3 of 8 *)
(* tags used below, declared in another part *)
   ENText1Message : BOOL;   // 0 = don't sent message 1 = send message
   ENText2Message : BOOL;   // 0 = don't sent message 1 = send message
   ENText3Message : BOOL;   // 0 = don't sent message 1 = send message
   ENTextFormats : BOOL;   // 0 = no additional text formatting 1 = enable text formatting
   ENTextSpecials : BOOL;   // 0 = no additional text special formatting 1 = enable text special formatting
   ENVariable1Message : BOOL;   // 0 = don't sent embedded variable 1 = send embedded variable
   ENVariable2Message : BOOL;   // 0 = don't sent embedded variable 1 = send embedded variable
   ENVariable3Message : BOOL;   // 0 = don't sent embedded variable 1 = send embedded variable
   ENVariableFormats : BOOL;   // 0 = no additional text formatting 1 = enable text formatting
   SEQ : DINT;   // Sequence Number
   InCycle : BOOL;   // Incycle
   SignTextMessage1 : STRING;
   SignColor : STRING;
   SignFont : STRING;
   Packet : STRING[7];   // Packet Array to send to sign
   SignSpeed : STRING;
   SignEffect : STRING;
   SignPause : STRING;
   SignTextMessage3 : STRING;
   SignTextMessage2 : STRING;
   SignNextLine : STRING;   // DO NOT EDIT = ^M
   SignVariableFont : STRING;
   SignVariableColor : STRING;
   SignVariable2 : STRING;
   SignVariable1 : STRING;
   Select : DINT;   // Packet Array Select
   TotalPacketCount : DINT[7];   // Total Character Count
   PacketMax : DINT;   // Max Packet Count
   SignAttribute : STRING;
   SignVariableAttribute : STRING;
(* SendSignMessage, continued *)

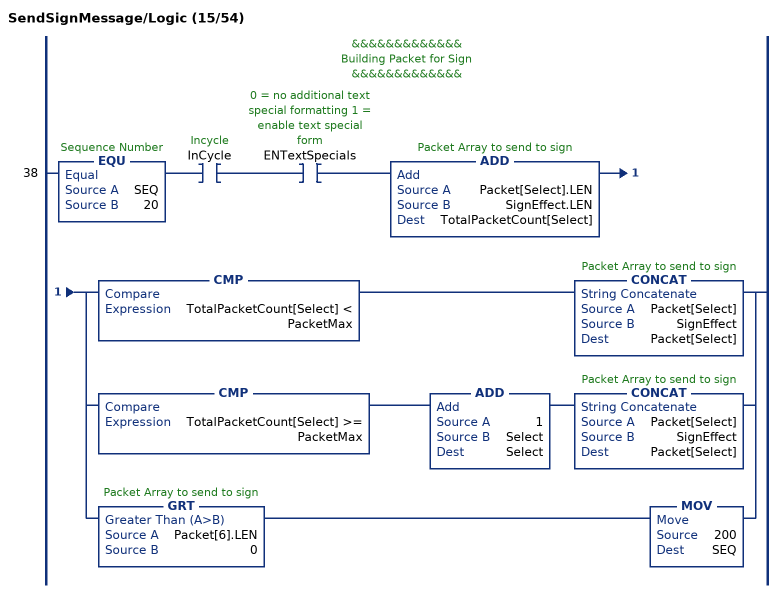
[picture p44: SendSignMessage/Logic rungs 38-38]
   // &&&&&&&&&&&&&
   // Building Packet for Sign
   // &&&&&&&&&&&&&
   38: EQU(SEQ,20)XIC(InCycle)XIC(ENTextSpecials)ADD(Packet[Select].LEN,SignEffect.LEN,TotalPacketCount[Select])[CMP(TotalPacketCount[Select] < PacketMax) CONCAT(Packet[Select],SignEffect,Packet[Select]) ,CMP(TotalPacketCount[Select] >= PacketMax) ADD(1,Select,Select) CONCAT(Packet[Select],SignEffect,Packet[Select]) ,GRT(Packet[6].LEN,0) MOV(200,SEQ) ];
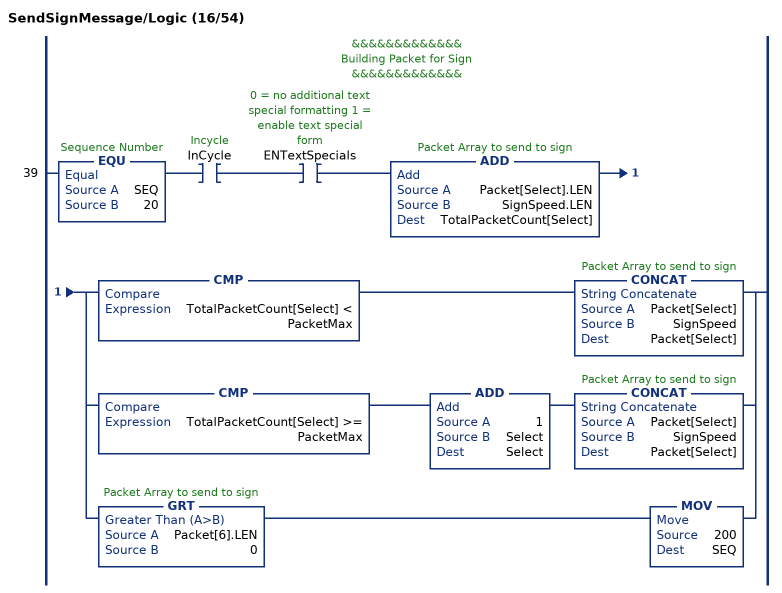
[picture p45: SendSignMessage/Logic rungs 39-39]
   // &&&&&&&&&&&&&
   // Building Packet for Sign
   // &&&&&&&&&&&&&
   39: EQU(SEQ,20)XIC(InCycle)XIC(ENTextSpecials)ADD(Packet[Select].LEN,SignSpeed.LEN,TotalPacketCount[Select])[CMP(TotalPacketCount[Select] < PacketMax) CONCAT(Packet[Select],SignSpeed,Packet[Select]) ,CMP(TotalPacketCount[Select] >= PacketMax) ADD(1,Select,Select) CONCAT(Packet[Select],SignSpeed,Packet[Select]) ,GRT(Packet[6].LEN,0) MOV(200,SEQ) ];
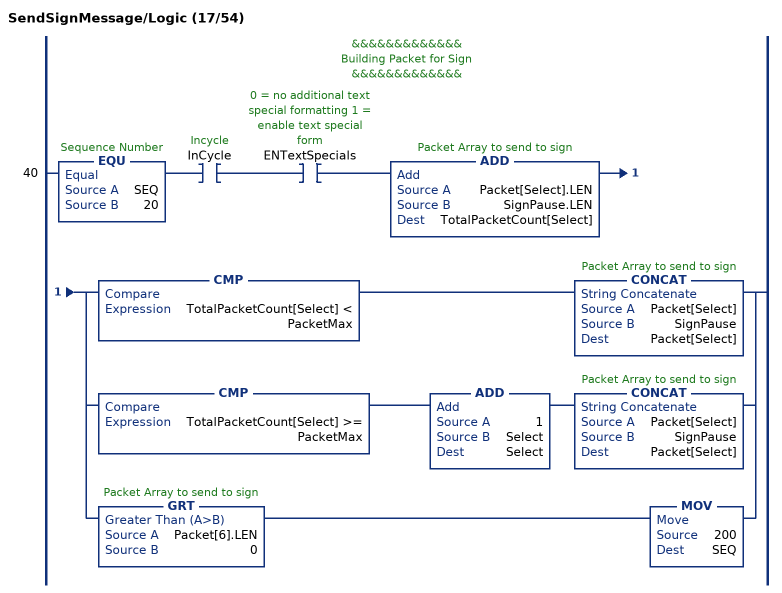
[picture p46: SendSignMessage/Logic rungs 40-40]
   // &&&&&&&&&&&&&
   // Building Packet for Sign
   // &&&&&&&&&&&&&
   40: EQU(SEQ,20)XIC(InCycle)XIC(ENTextSpecials)ADD(Packet[Select].LEN,SignPause.LEN,TotalPacketCount[Select])[CMP(TotalPacketCount[Select] < PacketMax) CONCAT(Packet[Select],SignPause,Packet[Select]) ,CMP(TotalPacketCount[Select] >= PacketMax) ADD(1,Select,Select) CONCAT(Packet[Select],SignPause,Packet[Select]) ,GRT(Packet[6].LEN,0) MOV(200,SEQ) ];
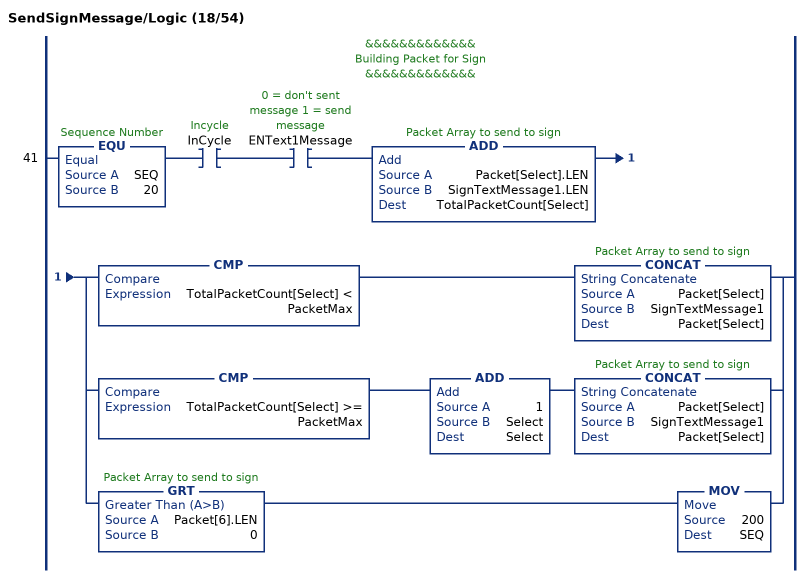
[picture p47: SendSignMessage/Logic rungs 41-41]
   // &&&&&&&&&&&&&
   // Building Packet for Sign
   // &&&&&&&&&&&&&
   41: EQU(SEQ,20)XIC(InCycle)XIC(ENText1Message)ADD(Packet[Select].LEN,SignTextMessage1.LEN,TotalPacketCount[Select])[CMP(TotalPacketCount[Select] < PacketMax) CONCAT(Packet[Select],SignTextMessage1,Packet[Select]) ,CMP(TotalPacketCount[Select] >= PacketMax) ADD(1,Select,Select) CONCAT(Packet[Select],SignTextMessage1,Packet[Select]) ,GRT(Packet[6].LEN,0) MOV(200,SEQ) ];
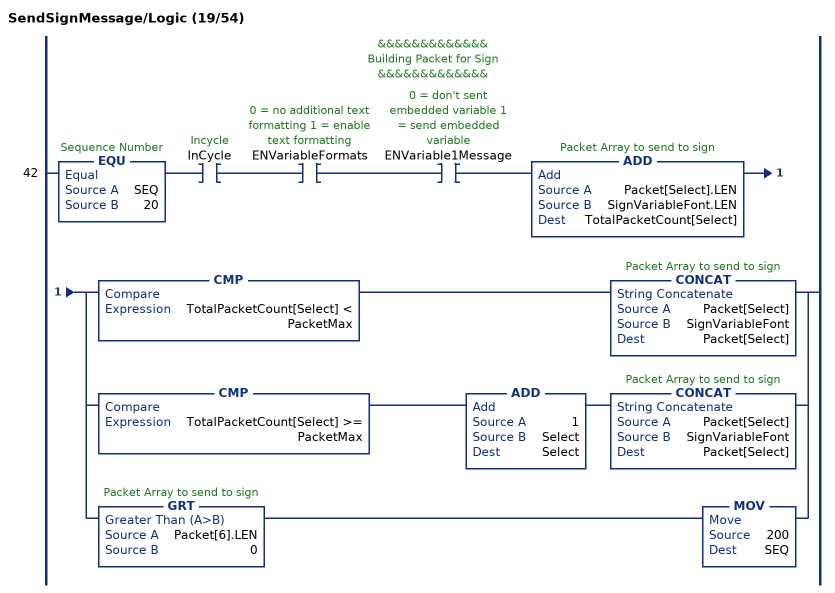
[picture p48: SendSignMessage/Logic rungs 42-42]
   // &&&&&&&&&&&&&
   // Building Packet for Sign
   // &&&&&&&&&&&&&
   42: EQU(SEQ,20)XIC(InCycle)XIC(ENVariableFormats)XIC(ENVariable1Message)ADD(Packet[Select].LEN,SignVariableFont.LEN,TotalPacketCount[Select])[CMP(TotalPacketCount[Select] < PacketMax) CONCAT(Packet[Select],SignVariableFont,Packet[Select]) ,CMP(TotalPacketCount[Select] >= PacketMax) ADD(1,Select,Select) CONCAT(Packet[Select],SignVariableFont,Packet[Select]) ,GRT(Packet[6].LEN,0) MOV(200,SEQ) ];
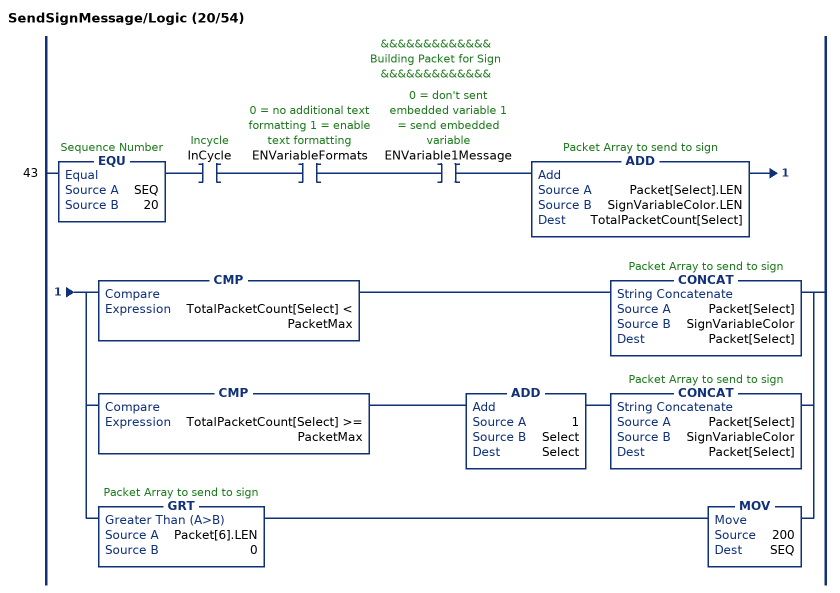
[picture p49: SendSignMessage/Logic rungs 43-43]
   // &&&&&&&&&&&&&
   // Building Packet for Sign
   // &&&&&&&&&&&&&
   43: EQU(SEQ,20)XIC(InCycle)XIC(ENVariableFormats)XIC(ENVariable1Message)ADD(Packet[Select].LEN,SignVariableColor.LEN,TotalPacketCount[Select])[CMP(TotalPacketCount[Select] < PacketMax) CONCAT(Packet[Select],SignVariableColor,Packet[Select]) ,CMP(TotalPacketCount[Select] >= PacketMax) ADD(1,Select,Select) CONCAT(Packet[Select],SignVariableColor,Packet[Select]) ,GRT(Packet[6].LEN,0) MOV(200,SEQ) ];
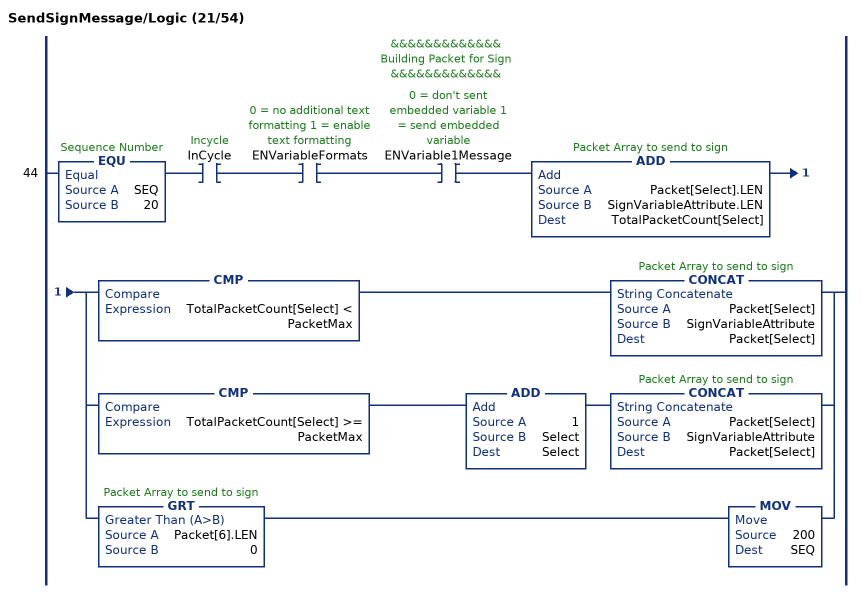
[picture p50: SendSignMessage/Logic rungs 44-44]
   // &&&&&&&&&&&&&
   // Building Packet for Sign
   // &&&&&&&&&&&&&
   44: EQU(SEQ,20)XIC(InCycle)XIC(ENVariableFormats)XIC(ENVariable1Message)ADD(Packet[Select].LEN,SignVariableAttribute.LEN,TotalPacketCount[Select])[CMP(TotalPacketCount[Select] < PacketMax) CONCAT(Packet[Select],SignVariableAttribute,Packet[Select]) ,CMP(TotalPacketCount[Select] >= PacketMax) ADD(1,Select,Select) CONCAT(Packet[Select],SignVariableAttribute,Packet[Select]) ,GRT(Packet[6].LEN,0) MOV(200,SEQ) ];
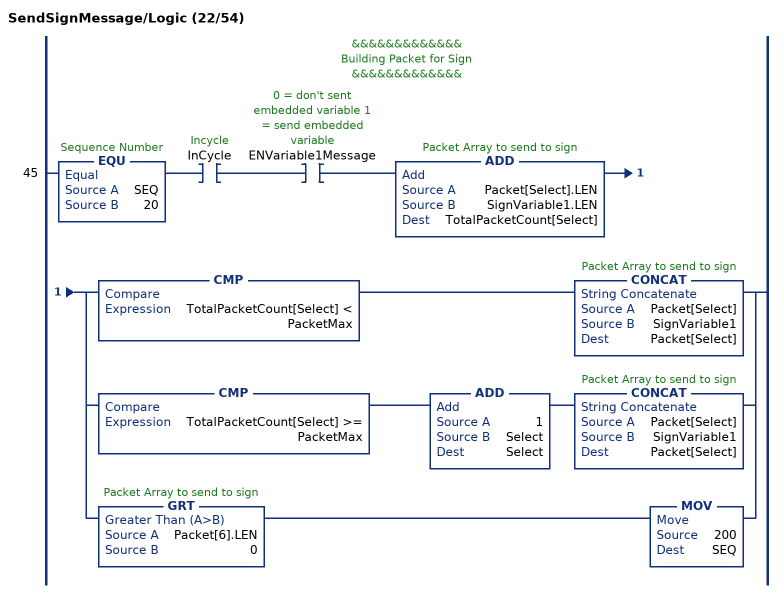
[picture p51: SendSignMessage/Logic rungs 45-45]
   // &&&&&&&&&&&&&
   // Building Packet for Sign
   // &&&&&&&&&&&&&
   45: EQU(SEQ,20)XIC(InCycle)XIC(ENVariable1Message)ADD(Packet[Select].LEN,SignVariable1.LEN,TotalPacketCount[Select])[CMP(TotalPacketCount[Select] < PacketMax) CONCAT(Packet[Select],SignVariable1,Packet[Select]) ,CMP(TotalPacketCount[Select] >= PacketMax) ADD(1,Select,Select) CONCAT(Packet[Select],SignVariable1,Packet[Select]) ,GRT(Packet[6].LEN,0) MOV(200,SEQ) ];
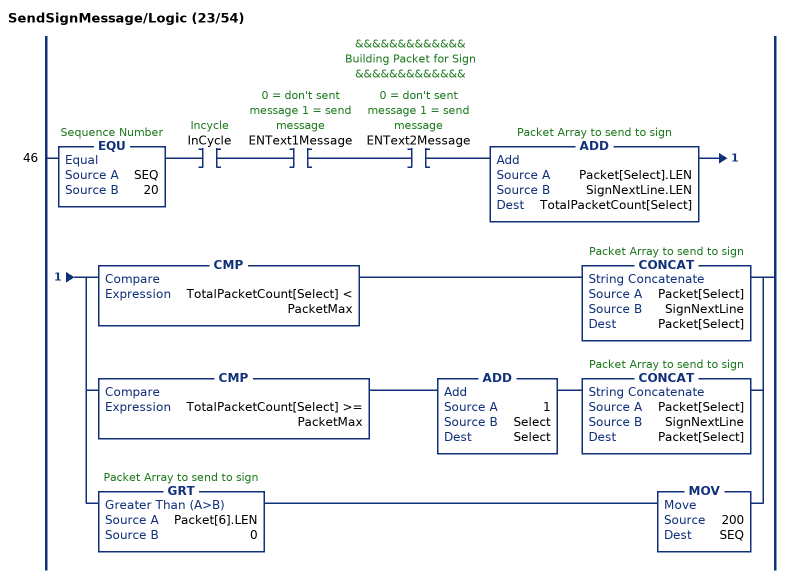
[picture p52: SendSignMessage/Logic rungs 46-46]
   // &&&&&&&&&&&&&
   // Building Packet for Sign
   // &&&&&&&&&&&&&
   46: EQU(SEQ,20)XIC(InCycle)XIC(ENText1Message)XIC(ENText2Message)ADD(Packet[Select].LEN,SignNextLine.LEN,TotalPacketCount[Select])[CMP(TotalPacketCount[Select] < PacketMax) CONCAT(Packet[Select],SignNextLine,Packet[Select]) ,CMP(TotalPacketCount[Select] >= PacketMax) ADD(1,Select,Select) CONCAT(Packet[Select],SignNextLine,Packet[Select]) ,GRT(Packet[6].LEN,0) MOV(200,SEQ) ];
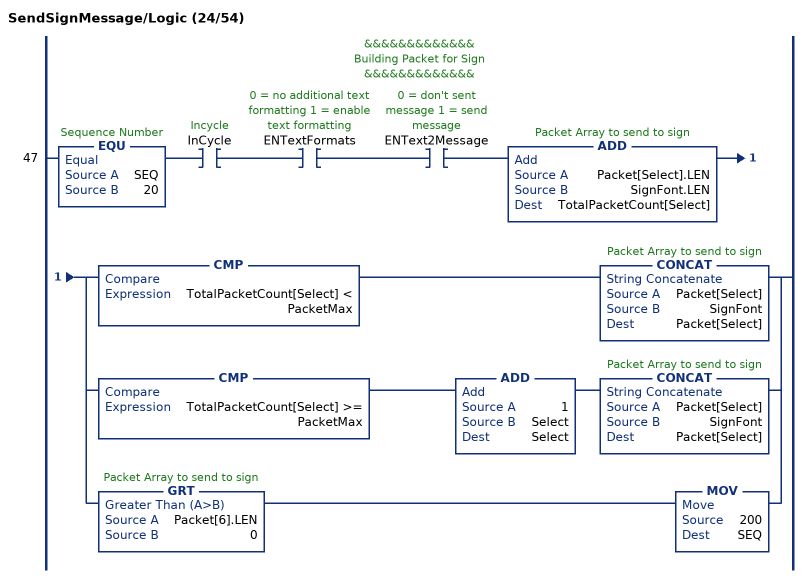
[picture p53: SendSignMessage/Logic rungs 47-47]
   // &&&&&&&&&&&&&
   // Building Packet for Sign
   // &&&&&&&&&&&&&
   47: EQU(SEQ,20)XIC(InCycle)XIC(ENTextFormats)XIC(ENText2Message)ADD(Packet[Select].LEN,SignFont.LEN,TotalPacketCount[Select])[CMP(TotalPacketCount[Select] < PacketMax) CONCAT(Packet[Select],SignFont,Packet[Select]) ,CMP(TotalPacketCount[Select] >= PacketMax) ADD(1,Select,Select) CONCAT(Packet[Select],SignFont,Packet[Select]) ,GRT(Packet[6].LEN,0) MOV(200,SEQ) ];
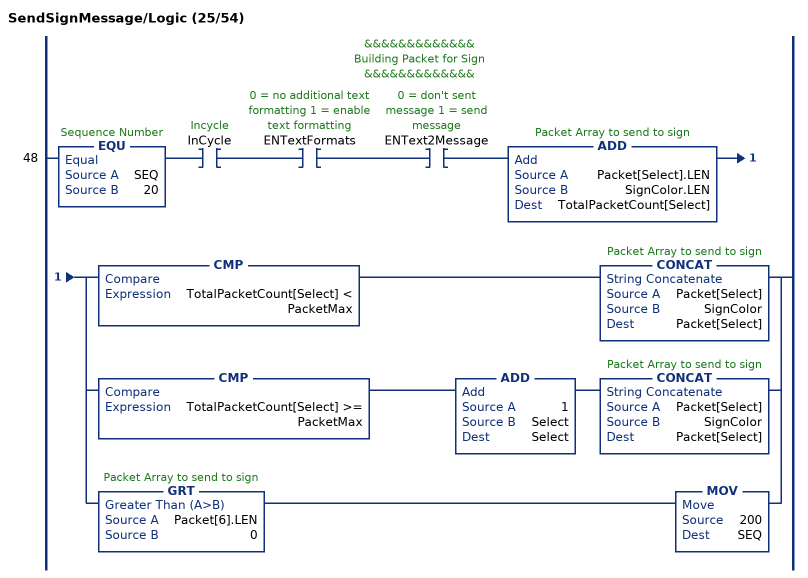
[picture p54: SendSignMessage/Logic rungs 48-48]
   // &&&&&&&&&&&&&
   // Building Packet for Sign
   // &&&&&&&&&&&&&
   48: EQU(SEQ,20)XIC(InCycle)XIC(ENTextFormats)XIC(ENText2Message)ADD(Packet[Select].LEN,SignColor.LEN,TotalPacketCount[Select])[CMP(TotalPacketCount[Select] < PacketMax) CONCAT(Packet[Select],SignColor,Packet[Select]) ,CMP(TotalPacketCount[Select] >= PacketMax) ADD(1,Select,Select) CONCAT(Packet[Select],SignColor,Packet[Select]) ,GRT(Packet[6].LEN,0) MOV(200,SEQ) ];
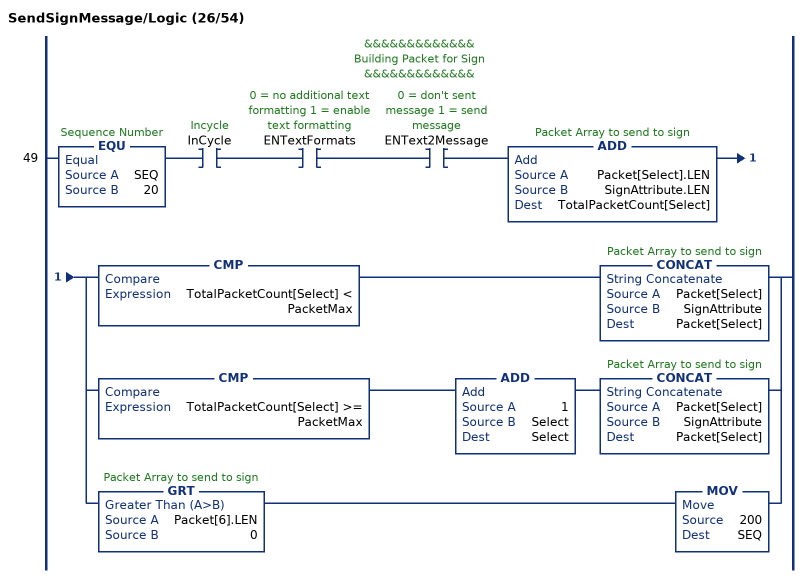
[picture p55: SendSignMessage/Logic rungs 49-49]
   // &&&&&&&&&&&&&
   // Building Packet for Sign
   // &&&&&&&&&&&&&
   49: EQU(SEQ,20)XIC(InCycle)XIC(ENTextFormats)XIC(ENText2Message)ADD(Packet[Select].LEN,SignAttribute.LEN,TotalPacketCount[Select])[CMP(TotalPacketCount[Select] < PacketMax) CONCAT(Packet[Select],SignAttribute,Packet[Select]) ,CMP(TotalPacketCount[Select] >= PacketMax) ADD(1,Select,Select) CONCAT(Packet[Select],SignAttribute,Packet[Select]) ,GRT(Packet[6].LEN,0) MOV(200,SEQ) ];
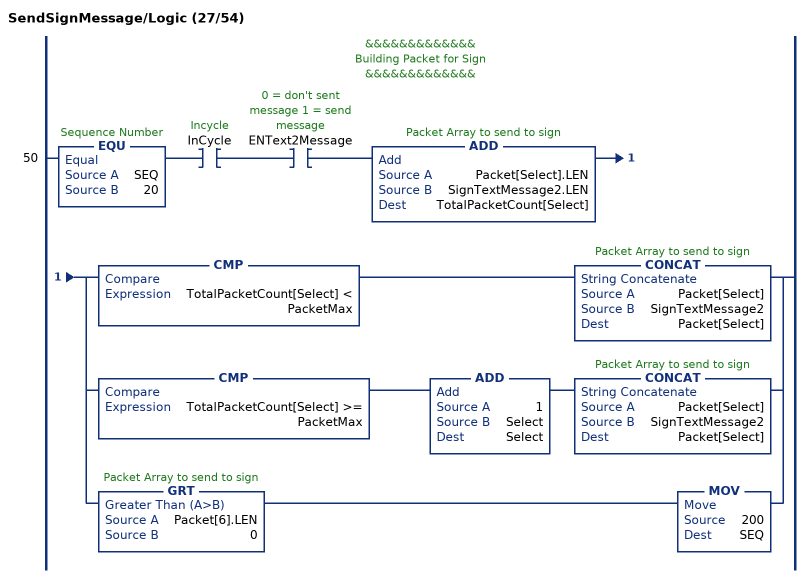
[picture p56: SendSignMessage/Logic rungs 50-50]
   // &&&&&&&&&&&&&
   // Building Packet for Sign
   // &&&&&&&&&&&&&
   50: EQU(SEQ,20)XIC(InCycle)XIC(ENText2Message)ADD(Packet[Select].LEN,SignTextMessage2.LEN,TotalPacketCount[Select])[CMP(TotalPacketCount[Select] < PacketMax) CONCAT(Packet[Select],SignTextMessage2,Packet[Select]) ,CMP(TotalPacketCount[Select] >= PacketMax) ADD(1,Select,Select) CONCAT(Packet[Select],SignTextMessage2,Packet[Select]) ,GRT(Packet[6].LEN,0) MOV(200,SEQ) ];
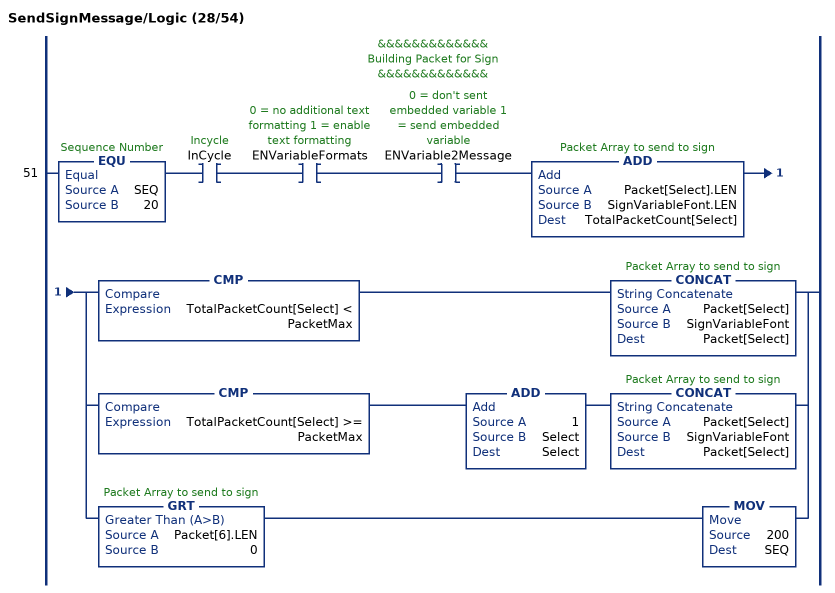
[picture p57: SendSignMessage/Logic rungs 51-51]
   // &&&&&&&&&&&&&
   // Building Packet for Sign
   // &&&&&&&&&&&&&
   51: EQU(SEQ,20)XIC(InCycle)XIC(ENVariableFormats)XIC(ENVariable2Message)ADD(Packet[Select].LEN,SignVariableFont.LEN,TotalPacketCount[Select])[CMP(TotalPacketCount[Select] < PacketMax) CONCAT(Packet[Select],SignVariableFont,Packet[Select]) ,CMP(TotalPacketCount[Select] >= PacketMax) ADD(1,Select,Select) CONCAT(Packet[Select],SignVariableFont,Packet[Select]) ,GRT(Packet[6].LEN,0) MOV(200,SEQ) ];
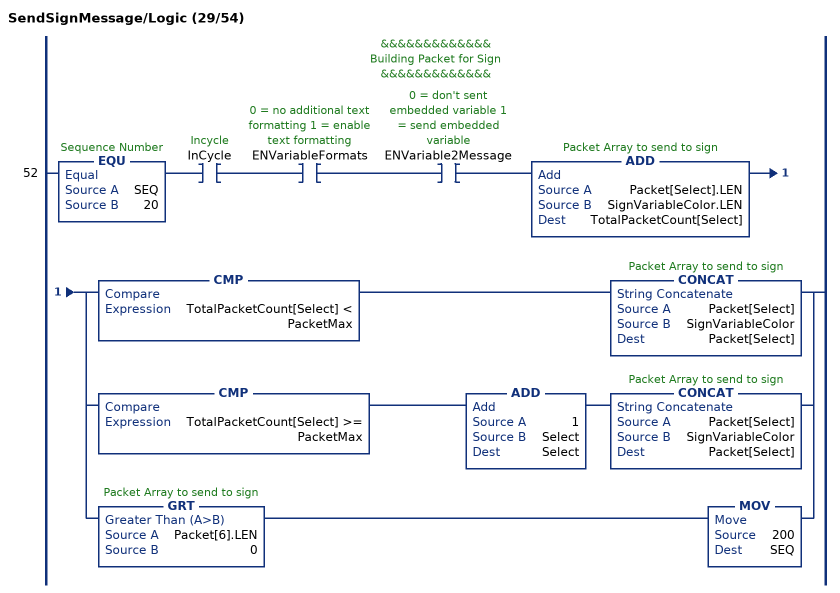
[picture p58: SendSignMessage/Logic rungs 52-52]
   // &&&&&&&&&&&&&
   // Building Packet for Sign
   // &&&&&&&&&&&&&
   52: EQU(SEQ,20)XIC(InCycle)XIC(ENVariableFormats)XIC(ENVariable2Message)ADD(Packet[Select].LEN,SignVariableColor.LEN,TotalPacketCount[Select])[CMP(TotalPacketCount[Select] < PacketMax) CONCAT(Packet[Select],SignVariableColor,Packet[Select]) ,CMP(TotalPacketCount[Select] >= PacketMax) ADD(1,Select,Select) CONCAT(Packet[Select],SignVariableColor,Packet[Select]) ,GRT(Packet[6].LEN,0) MOV(200,SEQ) ];
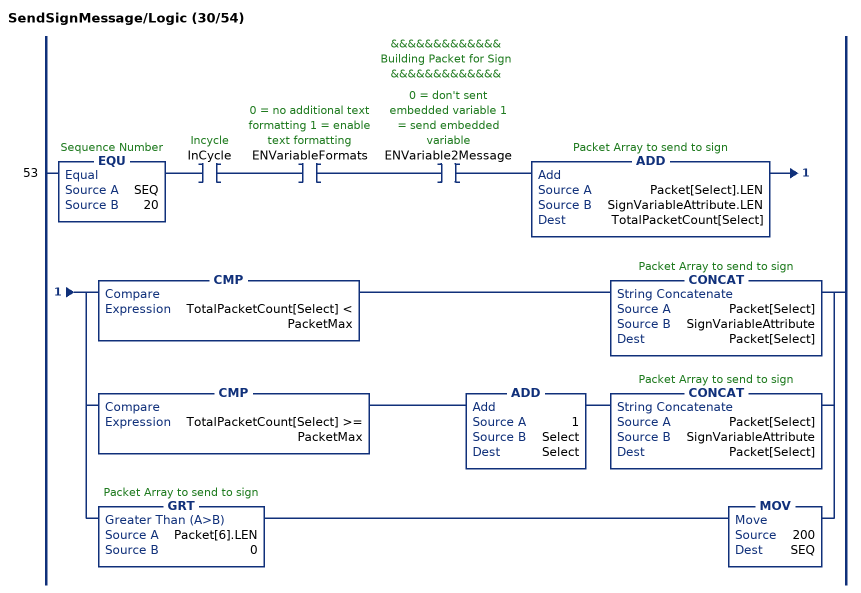
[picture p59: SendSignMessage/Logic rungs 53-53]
   // &&&&&&&&&&&&&
   // Building Packet for Sign
   // &&&&&&&&&&&&&
   53: EQU(SEQ,20)XIC(InCycle)XIC(ENVariableFormats)XIC(ENVariable2Message)ADD(Packet[Select].LEN,SignVariableAttribute.LEN,TotalPacketCount[Select])[CMP(TotalPacketCount[Select] < PacketMax) CONCAT(Packet[Select],SignVariableAttribute,Packet[Select]) ,CMP(TotalPacketCount[Select] >= PacketMax) ADD(1,Select,Select) CONCAT(Packet[Select],SignVariableAttribute,Packet[Select]) ,GRT(Packet[6].LEN,0) MOV(200,SEQ) ];
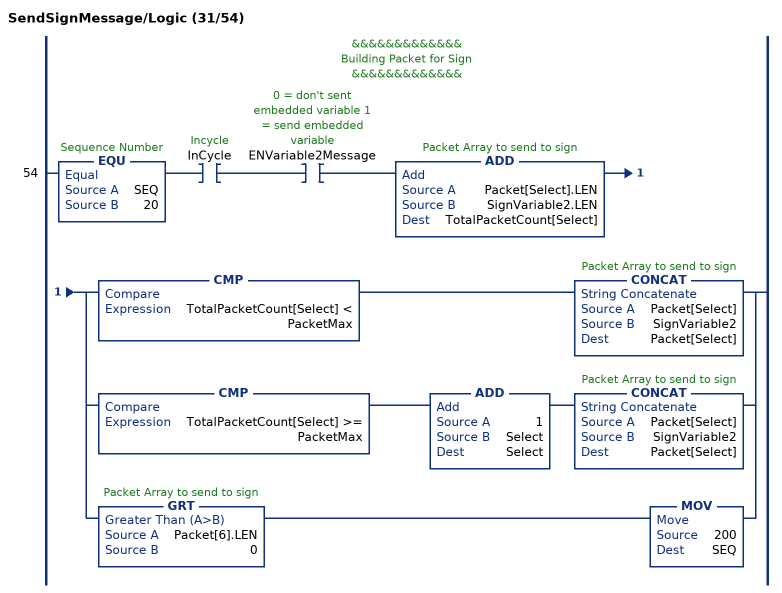
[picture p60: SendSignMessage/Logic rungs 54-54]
   // &&&&&&&&&&&&&
   // Building Packet for Sign
   // &&&&&&&&&&&&&
   54: EQU(SEQ,20)XIC(InCycle)XIC(ENVariable2Message)ADD(Packet[Select].LEN,SignVariable2.LEN,TotalPacketCount[Select])[CMP(TotalPacketCount[Select] < PacketMax) CONCAT(Packet[Select],SignVariable2,Packet[Select]) ,CMP(TotalPacketCount[Select] >= PacketMax) ADD(1,Select,Select) CONCAT(Packet[Select],SignVariable2,Packet[Select]) ,GRT(Packet[6].LEN,0) MOV(200,SEQ) ];
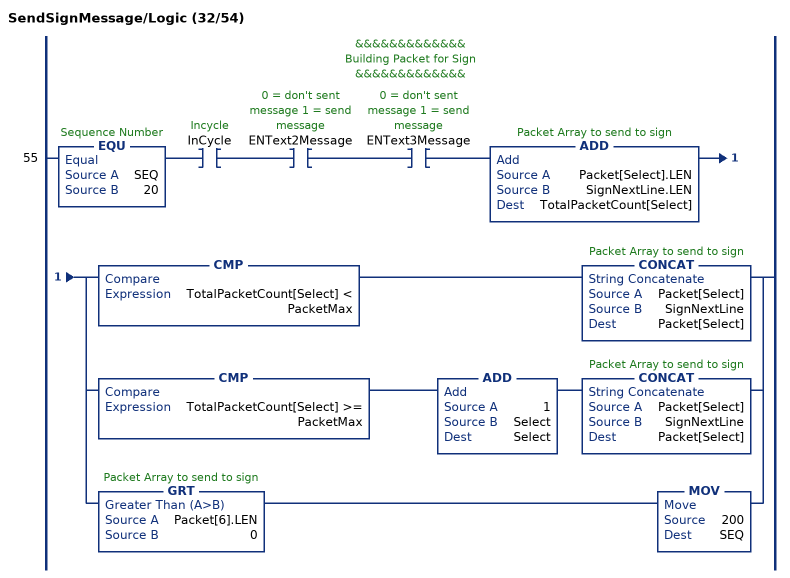
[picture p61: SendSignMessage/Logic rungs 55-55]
   // &&&&&&&&&&&&&
   // Building Packet for Sign
   // &&&&&&&&&&&&&
   55: EQU(SEQ,20)XIC(InCycle)XIC(ENText2Message)XIC(ENText3Message)ADD(Packet[Select].LEN,SignNextLine.LEN,TotalPacketCount[Select])[CMP(TotalPacketCount[Select] < PacketMax) CONCAT(Packet[Select],SignNextLine,Packet[Select]) ,CMP(TotalPacketCount[Select] >= PacketMax) ADD(1,Select,Select) CONCAT(Packet[Select],SignNextLine,Packet[Select]) ,GRT(Packet[6].LEN,0) MOV(200,SEQ) ];
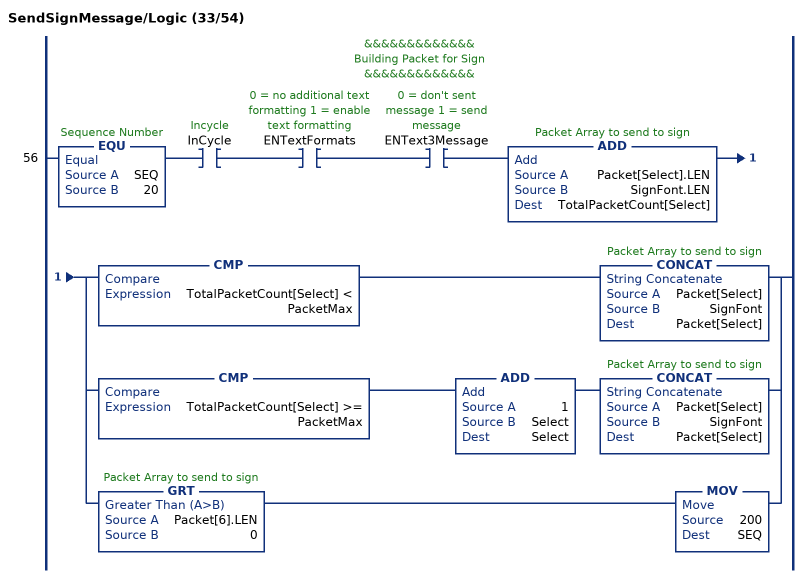
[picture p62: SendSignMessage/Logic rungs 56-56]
   // &&&&&&&&&&&&&
   // Building Packet for Sign
   // &&&&&&&&&&&&&
   56: EQU(SEQ,20)XIC(InCycle)XIC(ENTextFormats)XIC(ENText3Message)ADD(Packet[Select].LEN,SignFont.LEN,TotalPacketCount[Select])[CMP(TotalPacketCount[Select] < PacketMax) CONCAT(Packet[Select],SignFont,Packet[Select]) ,CMP(TotalPacketCount[Select] >= PacketMax) ADD(1,Select,Select) CONCAT(Packet[Select],SignFont,Packet[Select]) ,GRT(Packet[6].LEN,0) MOV(200,SEQ) ];
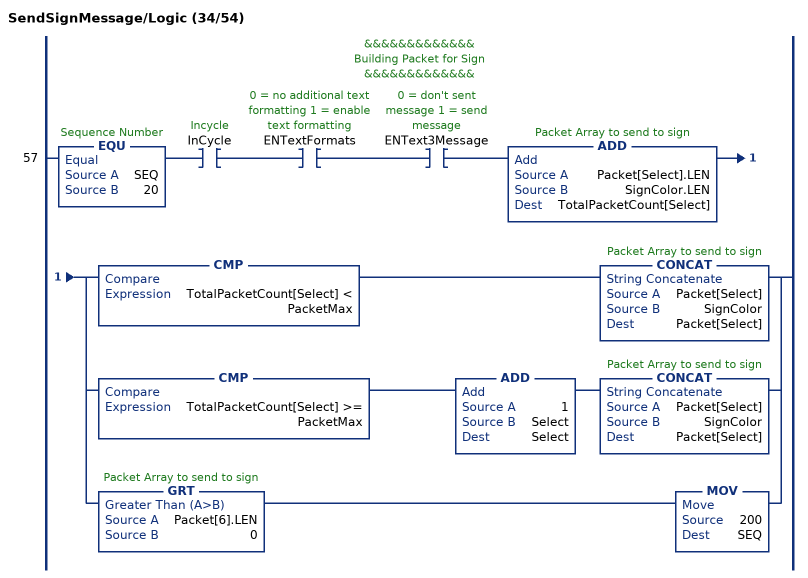
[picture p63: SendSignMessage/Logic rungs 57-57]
   // &&&&&&&&&&&&&
   // Building Packet for Sign
   // &&&&&&&&&&&&&
   57: EQU(SEQ,20)XIC(InCycle)XIC(ENTextFormats)XIC(ENText3Message)ADD(Packet[Select].LEN,SignColor.LEN,TotalPacketCount[Select])[CMP(TotalPacketCount[Select] < PacketMax) CONCAT(Packet[Select],SignColor,Packet[Select]) ,CMP(TotalPacketCount[Select] >= PacketMax) ADD(1,Select,Select) CONCAT(Packet[Select],SignColor,Packet[Select]) ,GRT(Packet[6].LEN,0) MOV(200,SEQ) ];
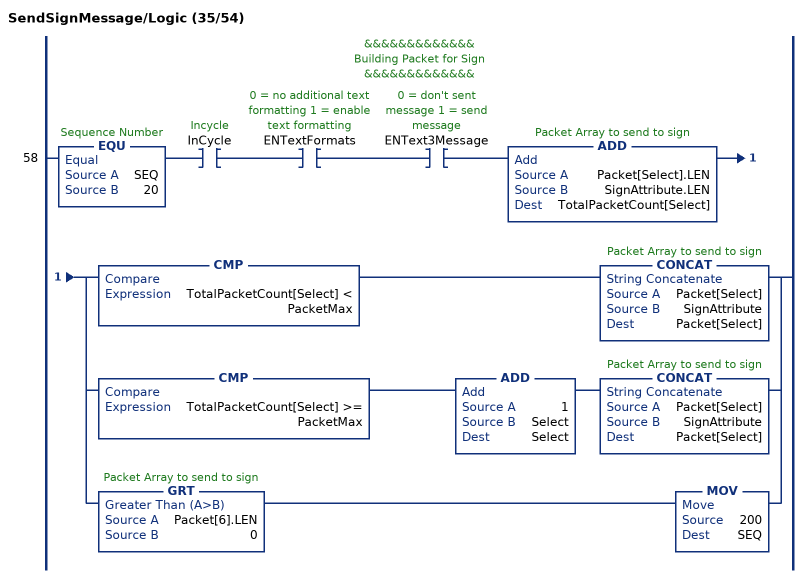
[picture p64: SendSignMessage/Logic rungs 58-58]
   // &&&&&&&&&&&&&
   // Building Packet for Sign
   // &&&&&&&&&&&&&
   58: EQU(SEQ,20)XIC(InCycle)XIC(ENTextFormats)XIC(ENText3Message)ADD(Packet[Select].LEN,SignAttribute.LEN,TotalPacketCount[Select])[CMP(TotalPacketCount[Select] < PacketMax) CONCAT(Packet[Select],SignAttribute,Packet[Select]) ,CMP(TotalPacketCount[Select] >= PacketMax) ADD(1,Select,Select) CONCAT(Packet[Select],SignAttribute,Packet[Select]) ,GRT(Packet[6].LEN,0) MOV(200,SEQ) ];
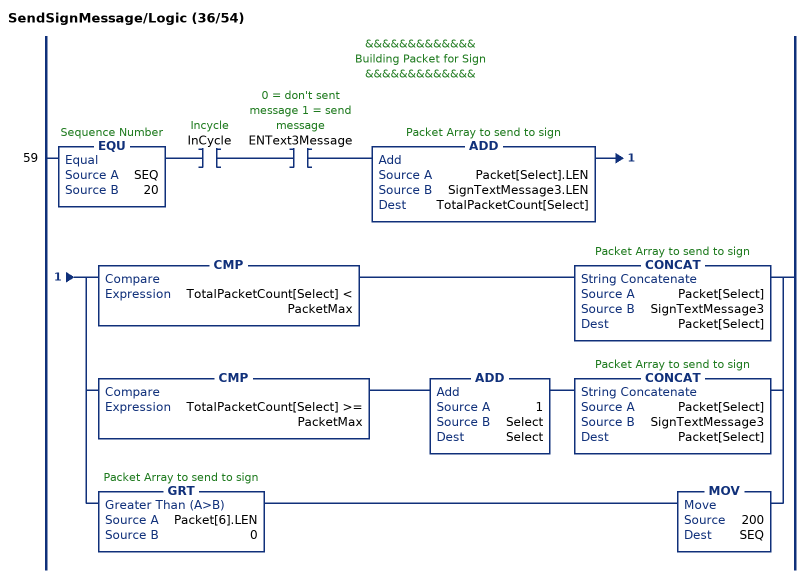
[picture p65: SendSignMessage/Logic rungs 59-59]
   // &&&&&&&&&&&&&
   // Building Packet for Sign
   // &&&&&&&&&&&&&
   59: EQU(SEQ,20)XIC(InCycle)XIC(ENText3Message)ADD(Packet[Select].LEN,SignTextMessage3.LEN,TotalPacketCount[Select])[CMP(TotalPacketCount[Select] < PacketMax) CONCAT(Packet[Select],SignTextMessage3,Packet[Select]) ,CMP(TotalPacketCount[Select] >= PacketMax) ADD(1,Select,Select) CONCAT(Packet[Select],SignTextMessage3,Packet[Select]) ,GRT(Packet[6].LEN,0) MOV(200,SEQ) ];
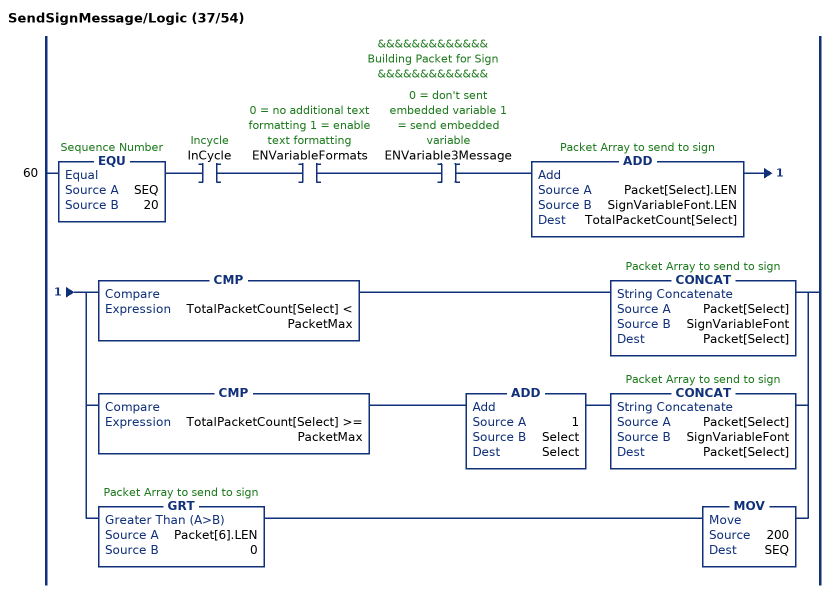
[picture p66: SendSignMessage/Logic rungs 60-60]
   // &&&&&&&&&&&&&
   // Building Packet for Sign
   // &&&&&&&&&&&&&
   60: EQU(SEQ,20)XIC(InCycle)XIC(ENVariableFormats)XIC(ENVariable3Message)ADD(Packet[Select].LEN,SignVariableFont.LEN,TotalPacketCount[Select])[CMP(TotalPacketCount[Select] < PacketMax) CONCAT(Packet[Select],SignVariableFont,Packet[Select]) ,CMP(TotalPacketCount[Select] >= PacketMax) ADD(1,Select,Select) CONCAT(Packet[Select],SignVariableFont,Packet[Select]) ,GRT(Packet[6].LEN,0) MOV(200,SEQ) ];
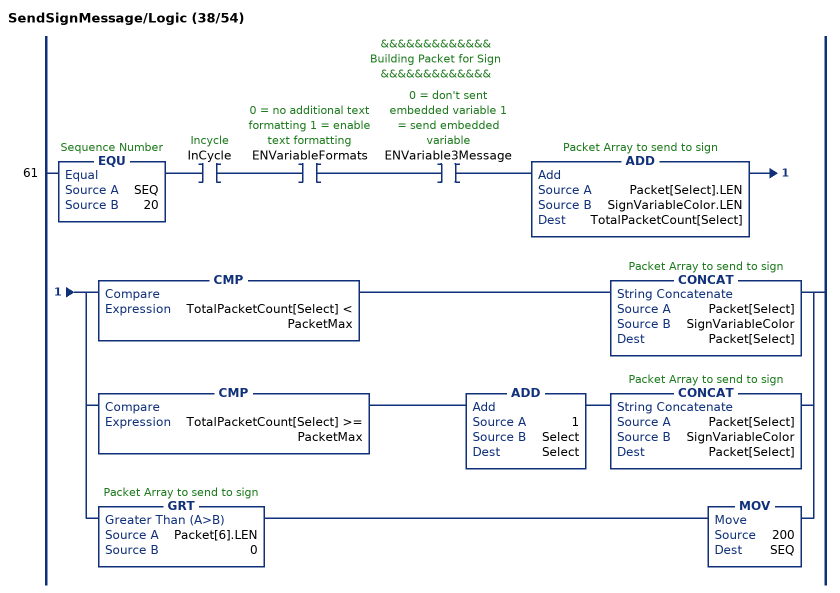
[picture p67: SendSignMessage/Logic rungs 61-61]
   // &&&&&&&&&&&&&
   // Building Packet for Sign
   // &&&&&&&&&&&&&
   61: EQU(SEQ,20)XIC(InCycle)XIC(ENVariableFormats)XIC(ENVariable3Message)ADD(Packet[Select].LEN,SignVariableColor.LEN,TotalPacketCount[Select])[CMP(TotalPacketCount[Select] < PacketMax) CONCAT(Packet[Select],SignVariableColor,Packet[Select]) ,CMP(TotalPacketCount[Select] >= PacketMax) ADD(1,Select,Select) CONCAT(Packet[Select],SignVariableColor,Packet[Select]) ,GRT(Packet[6].LEN,0) MOV(200,SEQ) ];
(* Logix 5000 project; controller Electronic_Displays vendor 1 type 14 code 65 rev 17.4; software revision 17.01; part 4 of 8 *)
(* tags used below, declared in another part *)
   ENText3Message : BOOL;   // 0 = don't sent message 1 = send message
   ENText4Message : BOOL;   // 0 = don't sent message 1 = send message
   ENTextFormats : BOOL;   // 0 = no additional text formatting 1 = enable text formatting
   ENVariableFormats : BOOL;   // 0 = no additional text formatting 1 = enable text formatting
   Packet4Sent : STRING;   // The actual packet sent to the sign (Packet4)
   Packet5Sent : STRING;   // The actual packet sent to the sign (Packet5)
   Packet6Sent : STRING;   // The actual packet sent to the sign (Packet6)
   SignColor : STRING;
   SignFont : STRING;
   SignTextMessage4 : STRING;
   SignNextLine : STRING;   // DO NOT EDIT = ^M
   SignVariableFont : STRING;
   SignVariableColor : STRING;
   SignAttribute : STRING;
   SignVariableAttribute : STRING;
(* SendSignMessage, continued *)

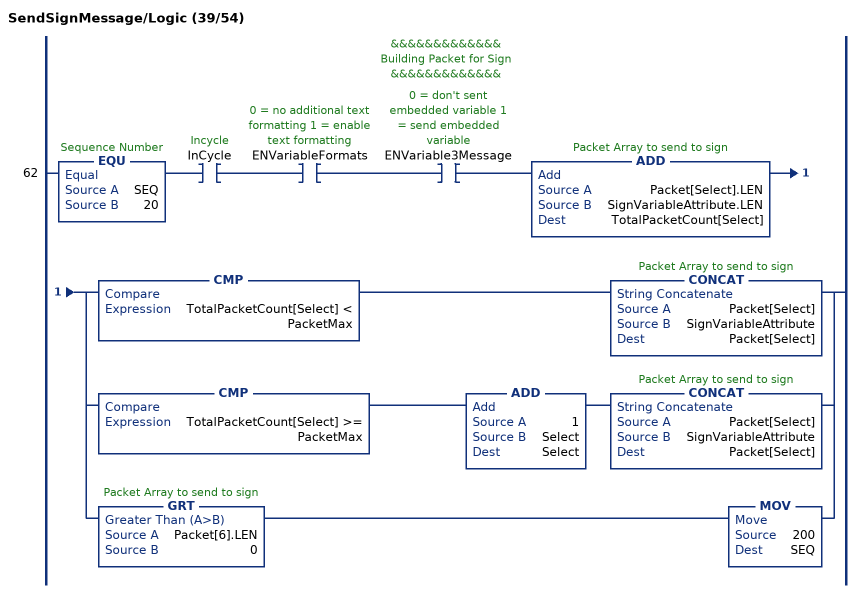
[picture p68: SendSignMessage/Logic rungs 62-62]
   // &&&&&&&&&&&&&
   // Building Packet for Sign
   // &&&&&&&&&&&&&
   62: EQU(SEQ,20)XIC(InCycle)XIC(ENVariableFormats)XIC(ENVariable3Message)ADD(Packet[Select].LEN,SignVariableAttribute.LEN,TotalPacketCount[Select])[CMP(TotalPacketCount[Select] < PacketMax) CONCAT(Packet[Select],SignVariableAttribute,Packet[Select]) ,CMP(TotalPacketCount[Select] >= PacketMax) ADD(1,Select,Select) CONCAT(Packet[Select],SignVariableAttribute,Packet[Select]) ,GRT(Packet[6].LEN,0) MOV(200,SEQ) ];
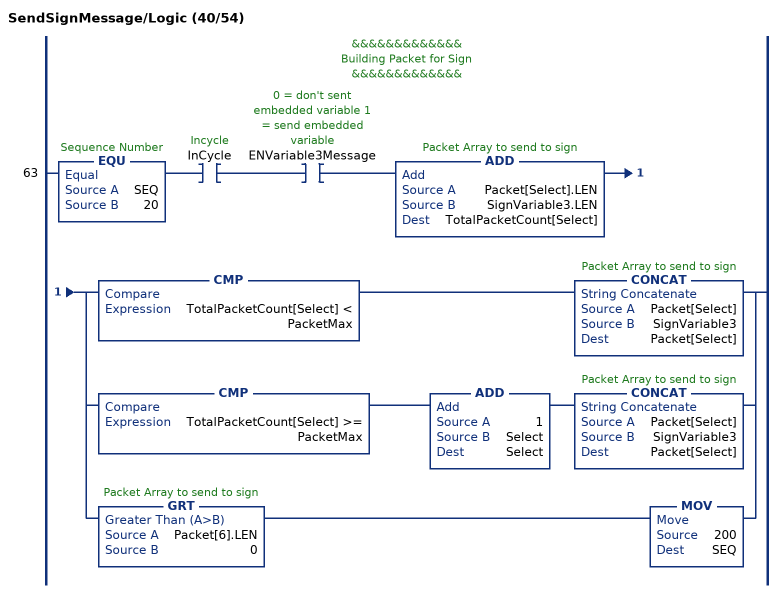
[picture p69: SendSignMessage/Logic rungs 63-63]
   // &&&&&&&&&&&&&
   // Building Packet for Sign
   // &&&&&&&&&&&&&
   63: EQU(SEQ,20)XIC(InCycle)XIC(ENVariable3Message)ADD(Packet[Select].LEN,SignVariable3.LEN,TotalPacketCount[Select])[CMP(TotalPacketCount[Select] < PacketMax) CONCAT(Packet[Select],SignVariable3,Packet[Select]) ,CMP(TotalPacketCount[Select] >= PacketMax) ADD(1,Select,Select) CONCAT(Packet[Select],SignVariable3,Packet[Select]) ,GRT(Packet[6].LEN,0) MOV(200,SEQ) ];
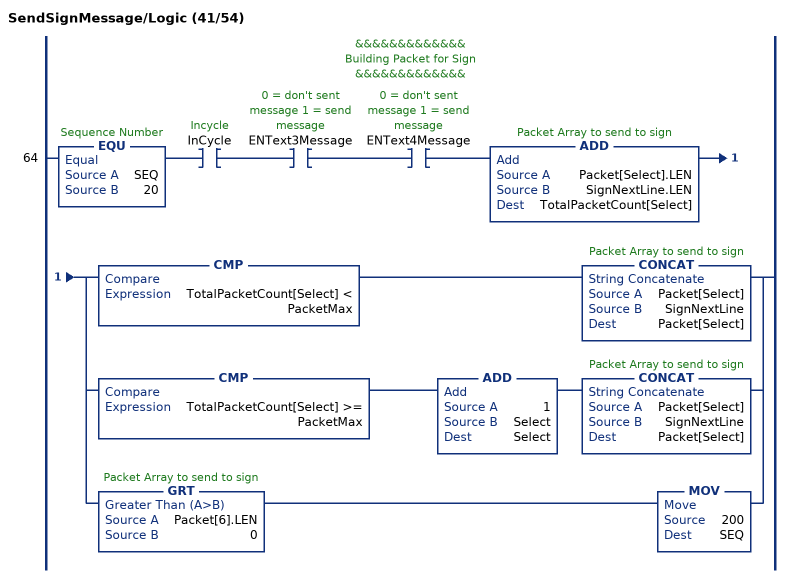
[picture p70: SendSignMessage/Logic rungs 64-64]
   // &&&&&&&&&&&&&
   // Building Packet for Sign
   // &&&&&&&&&&&&&
   64: EQU(SEQ,20)XIC(InCycle)XIC(ENText3Message)XIC(ENText4Message)ADD(Packet[Select].LEN,SignNextLine.LEN,TotalPacketCount[Select])[CMP(TotalPacketCount[Select] < PacketMax) CONCAT(Packet[Select],SignNextLine,Packet[Select]) ,CMP(TotalPacketCount[Select] >= PacketMax) ADD(1,Select,Select) CONCAT(Packet[Select],SignNextLine,Packet[Select]) ,GRT(Packet[6].LEN,0) MOV(200,SEQ) ];
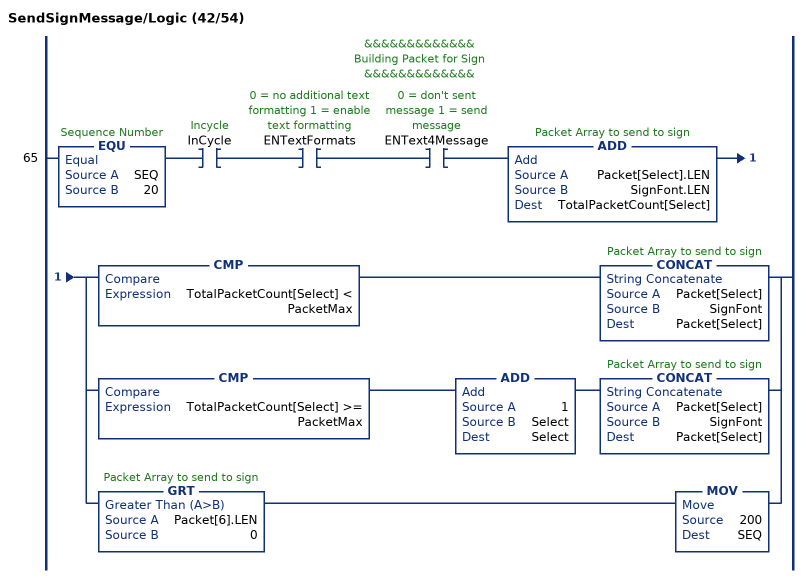
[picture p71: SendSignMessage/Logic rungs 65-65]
   // &&&&&&&&&&&&&
   // Building Packet for Sign
   // &&&&&&&&&&&&&
   65: EQU(SEQ,20)XIC(InCycle)XIC(ENTextFormats)XIC(ENText4Message)ADD(Packet[Select].LEN,SignFont.LEN,TotalPacketCount[Select])[CMP(TotalPacketCount[Select] < PacketMax) CONCAT(Packet[Select],SignFont,Packet[Select]) ,CMP(TotalPacketCount[Select] >= PacketMax) ADD(1,Select,Select) CONCAT(Packet[Select],SignFont,Packet[Select]) ,GRT(Packet[6].LEN,0) MOV(200,SEQ) ];
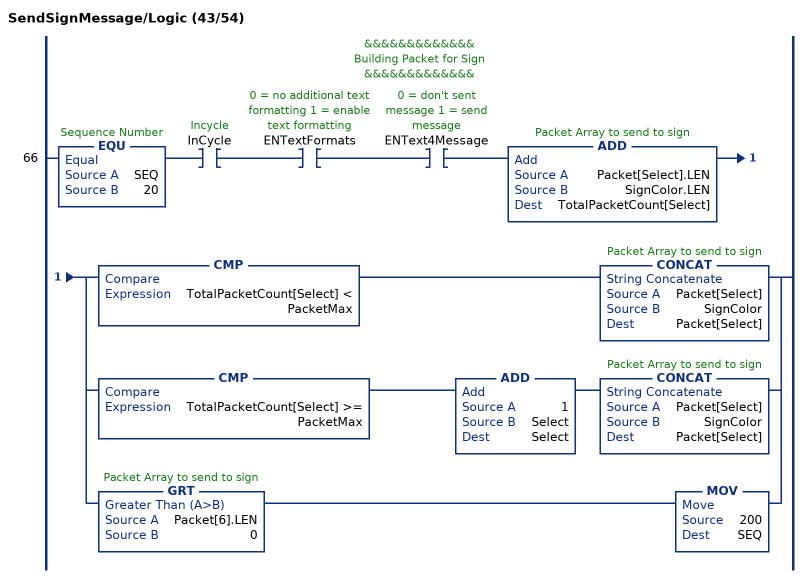
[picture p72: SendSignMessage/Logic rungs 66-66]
   // &&&&&&&&&&&&&
   // Building Packet for Sign
   // &&&&&&&&&&&&&
   66: EQU(SEQ,20)XIC(InCycle)XIC(ENTextFormats)XIC(ENText4Message)ADD(Packet[Select].LEN,SignColor.LEN,TotalPacketCount[Select])[CMP(TotalPacketCount[Select] < PacketMax) CONCAT(Packet[Select],SignColor,Packet[Select]) ,CMP(TotalPacketCount[Select] >= PacketMax) ADD(1,Select,Select) CONCAT(Packet[Select],SignColor,Packet[Select]) ,GRT(Packet[6].LEN,0) MOV(200,SEQ) ];
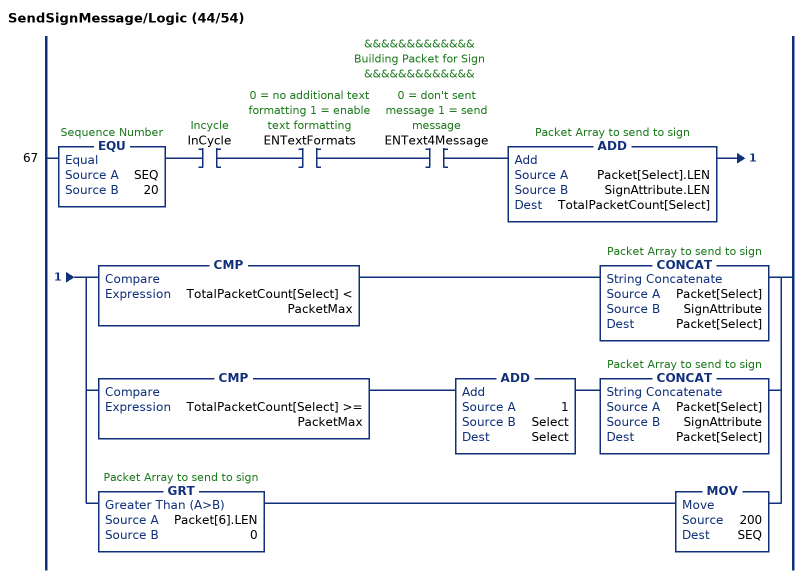
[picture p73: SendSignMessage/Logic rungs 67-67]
   // &&&&&&&&&&&&&
   // Building Packet for Sign
   // &&&&&&&&&&&&&
   67: EQU(SEQ,20)XIC(InCycle)XIC(ENTextFormats)XIC(ENText4Message)ADD(Packet[Select].LEN,SignAttribute.LEN,TotalPacketCount[Select])[CMP(TotalPacketCount[Select] < PacketMax) CONCAT(Packet[Select],SignAttribute,Packet[Select]) ,CMP(TotalPacketCount[Select] >= PacketMax) ADD(1,Select,Select) CONCAT(Packet[Select],SignAttribute,Packet[Select]) ,GRT(Packet[6].LEN,0) MOV(200,SEQ) ];
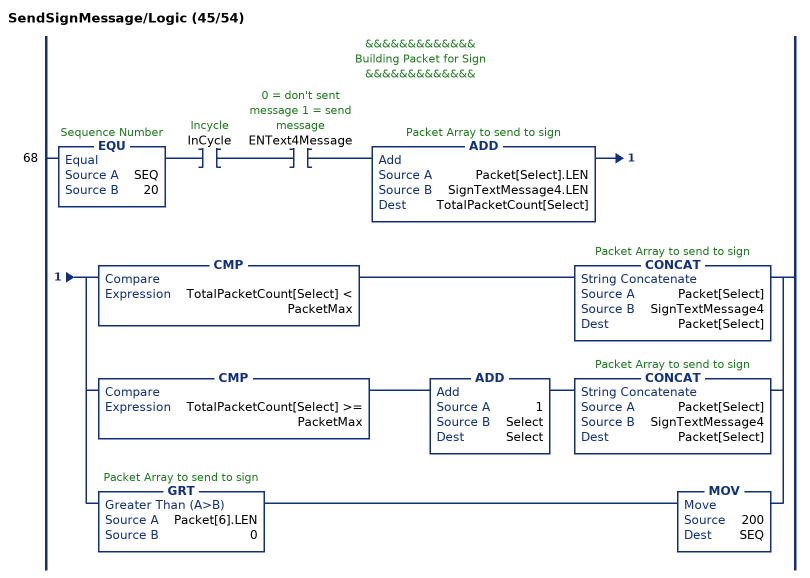
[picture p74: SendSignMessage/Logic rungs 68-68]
   // &&&&&&&&&&&&&
   // Building Packet for Sign
   // &&&&&&&&&&&&&
   68: EQU(SEQ,20)XIC(InCycle)XIC(ENText4Message)ADD(Packet[Select].LEN,SignTextMessage4.LEN,TotalPacketCount[Select])[CMP(TotalPacketCount[Select] < PacketMax) CONCAT(Packet[Select],SignTextMessage4,Packet[Select]) ,CMP(TotalPacketCount[Select] >= PacketMax) ADD(1,Select,Select) CONCAT(Packet[Select],SignTextMessage4,Packet[Select]) ,GRT(Packet[6].LEN,0) MOV(200,SEQ) ];
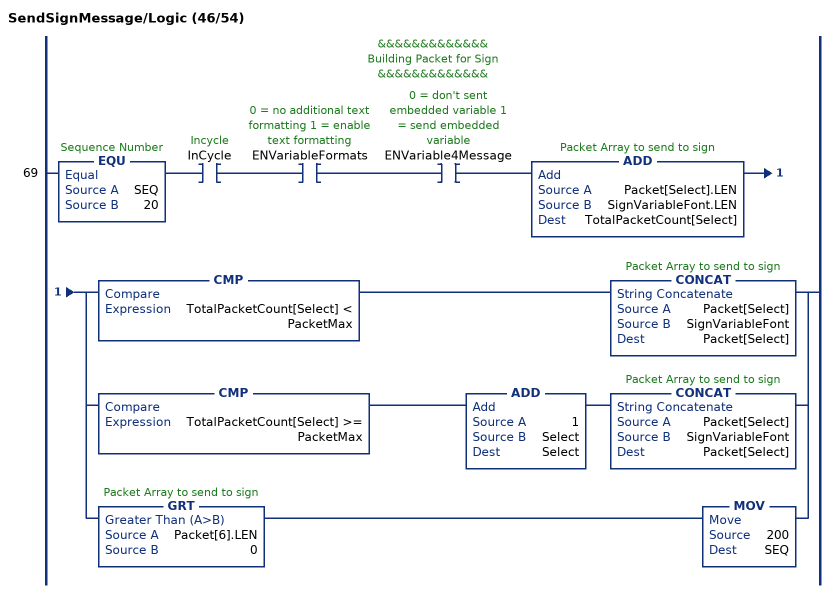
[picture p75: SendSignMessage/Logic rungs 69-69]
   // &&&&&&&&&&&&&
   // Building Packet for Sign
   // &&&&&&&&&&&&&
   69: EQU(SEQ,20)XIC(InCycle)XIC(ENVariableFormats)XIC(ENVariable4Message)ADD(Packet[Select].LEN,SignVariableFont.LEN,TotalPacketCount[Select])[CMP(TotalPacketCount[Select] < PacketMax) CONCAT(Packet[Select],SignVariableFont,Packet[Select]) ,CMP(TotalPacketCount[Select] >= PacketMax) ADD(1,Select,Select) CONCAT(Packet[Select],SignVariableFont,Packet[Select]) ,GRT(Packet[6].LEN,0) MOV(200,SEQ) ];
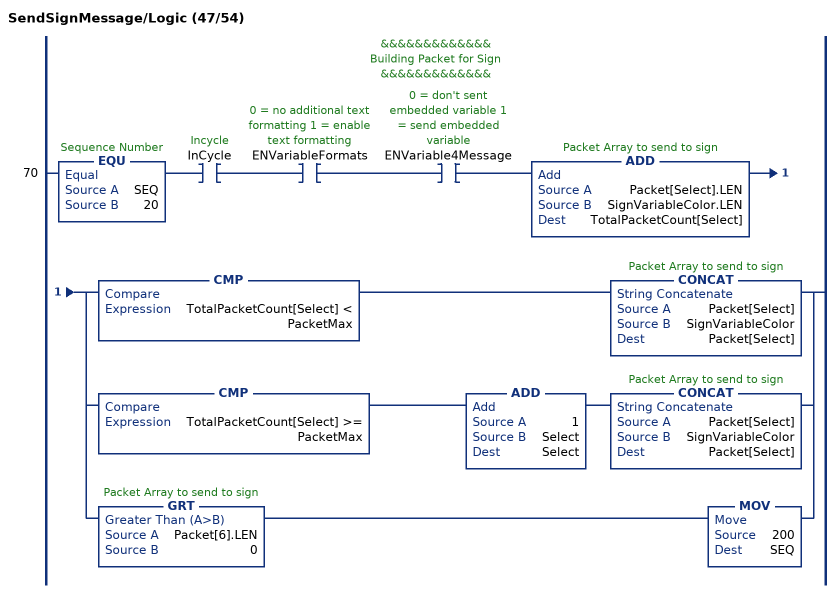
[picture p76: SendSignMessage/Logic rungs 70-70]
   // &&&&&&&&&&&&&
   // Building Packet for Sign
   // &&&&&&&&&&&&&
   70: EQU(SEQ,20)XIC(InCycle)XIC(ENVariableFormats)XIC(ENVariable4Message)ADD(Packet[Select].LEN,SignVariableColor.LEN,TotalPacketCount[Select])[CMP(TotalPacketCount[Select] < PacketMax) CONCAT(Packet[Select],SignVariableColor,Packet[Select]) ,CMP(TotalPacketCount[Select] >= PacketMax) ADD(1,Select,Select) CONCAT(Packet[Select],SignVariableColor,Packet[Select]) ,GRT(Packet[6].LEN,0) MOV(200,SEQ) ];
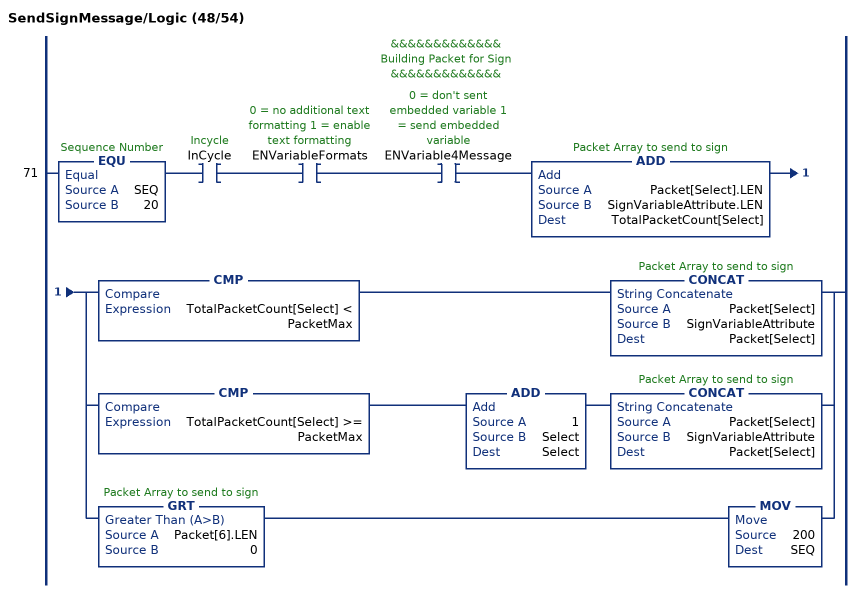
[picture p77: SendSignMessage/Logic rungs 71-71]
   // &&&&&&&&&&&&&
   // Building Packet for Sign
   // &&&&&&&&&&&&&
   71: EQU(SEQ,20)XIC(InCycle)XIC(ENVariableFormats)XIC(ENVariable4Message)ADD(Packet[Select].LEN,SignVariableAttribute.LEN,TotalPacketCount[Select])[CMP(TotalPacketCount[Select] < PacketMax) CONCAT(Packet[Select],SignVariableAttribute,Packet[Select]) ,CMP(TotalPacketCount[Select] >= PacketMax) ADD(1,Select,Select) CONCAT(Packet[Select],SignVariableAttribute,Packet[Select]) ,GRT(Packet[6].LEN,0) MOV(200,SEQ) ];
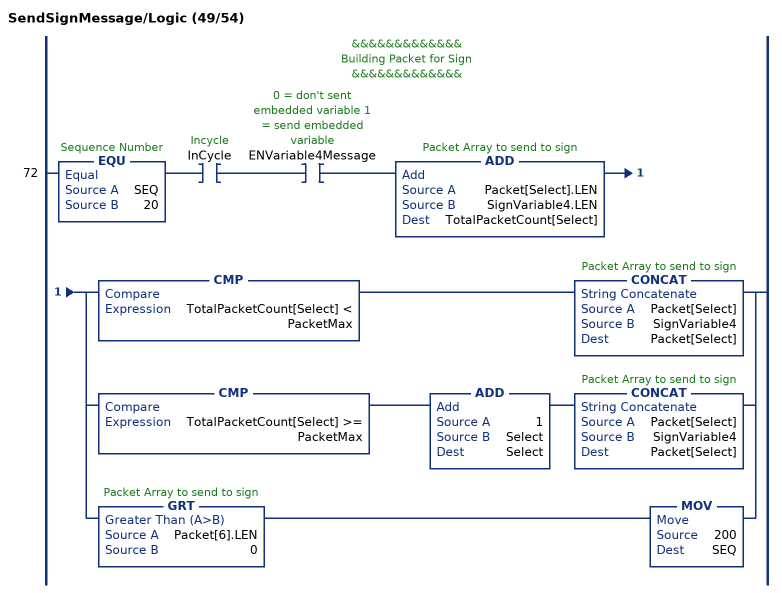
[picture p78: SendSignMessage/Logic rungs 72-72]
   // &&&&&&&&&&&&&
   // Building Packet for Sign
   // &&&&&&&&&&&&&
   72: EQU(SEQ,20)XIC(InCycle)XIC(ENVariable4Message)ADD(Packet[Select].LEN,SignVariable4.LEN,TotalPacketCount[Select])[CMP(TotalPacketCount[Select] < PacketMax) CONCAT(Packet[Select],SignVariable4,Packet[Select]) ,CMP(TotalPacketCount[Select] >= PacketMax) ADD(1,Select,Select) CONCAT(Packet[Select],SignVariable4,Packet[Select]) ,GRT(Packet[6].LEN,0) MOV(200,SEQ) ];
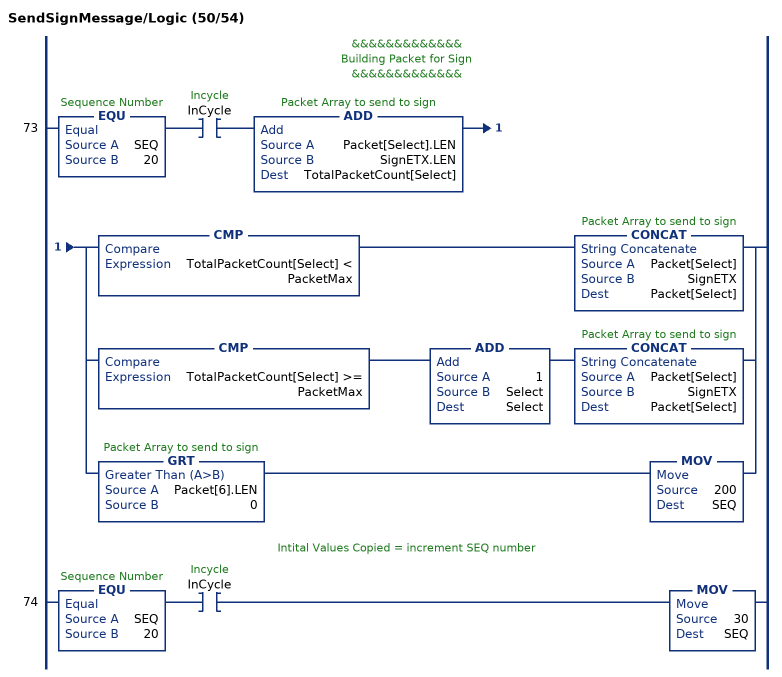
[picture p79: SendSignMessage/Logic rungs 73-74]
   // &&&&&&&&&&&&&
   // Building Packet for Sign
   // &&&&&&&&&&&&&
   73: EQU(SEQ,20)XIC(InCycle)ADD(Packet[Select].LEN,SignETX.LEN,TotalPacketCount[Select])[CMP(TotalPacketCount[Select] < PacketMax) CONCAT(Packet[Select],SignETX,Packet[Select]) ,CMP(TotalPacketCount[Select] >= PacketMax) ADD(1,Select,Select) CONCAT(Packet[Select],SignETX,Packet[Select]) ,GRT(Packet[6].LEN,0) MOV(200,SEQ) ];
   // Intital Values Copied = increment SEQ number
   74: EQU(SEQ,20)XIC(InCycle)MOV(30,SEQ);
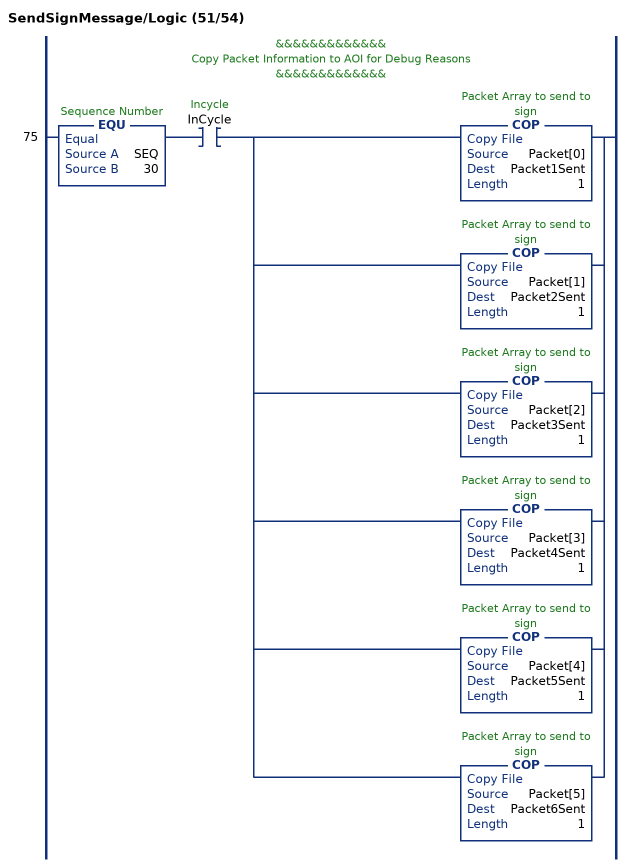
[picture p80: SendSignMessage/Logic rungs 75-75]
   // &&&&&&&&&&&&&
   // Copy Packet Information to AOI for Debug Reasons
   // &&&&&&&&&&&&&
   75: EQU(SEQ,30)XIC(InCycle)[COP(Packet[0],Packet1Sent,1) ,COP(Packet[1],Packet2Sent,1) ,COP(Packet[2],Packet3Sent,1) ,COP(Packet[3],Packet4Sent,1) ,COP(Packet[4],Packet5Sent,1) ,COP(Packet[5],Packet6Sent,1) ];
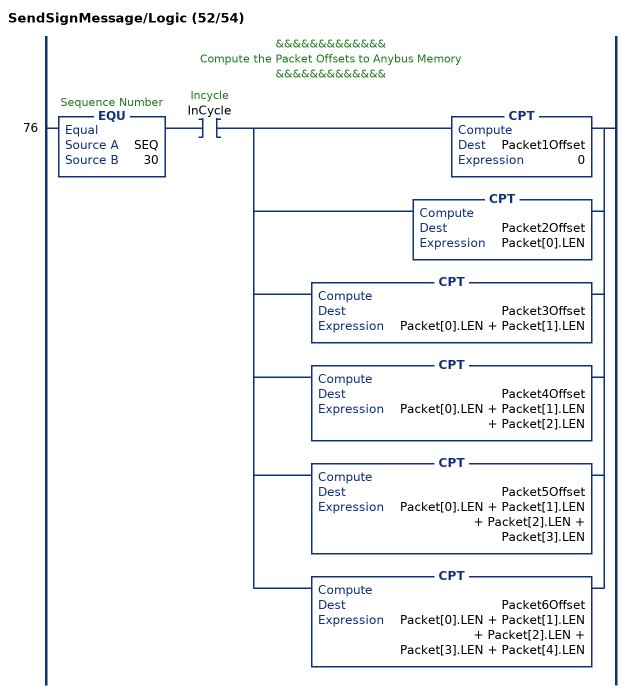
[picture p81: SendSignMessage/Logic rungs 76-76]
   // &&&&&&&&&&&&&
   // Compute the Packet Offsets to Anybus Memory
   // &&&&&&&&&&&&&
   76: EQU(SEQ,30)XIC(InCycle)[CPT(Packet1Offset,0) ,CPT(Packet2Offset,Packet[0].LEN) ,CPT(Packet3Offset,Packet[0].LEN + Packet[1].LEN) ,CPT(Packet4Offset,Packet[0].LEN + Packet[1].LEN + Packet[2].LEN) ,CPT(Packet5Offset,Packet[0].LEN + Packet[1].LEN + Packet[2].LEN + Packet[3].LEN) ,CPT(Packet6Offset,Packet[0].LEN + Packet[1].LEN + Packet[2].LEN + Packet[3].LEN + Packet[4].LEN) ];
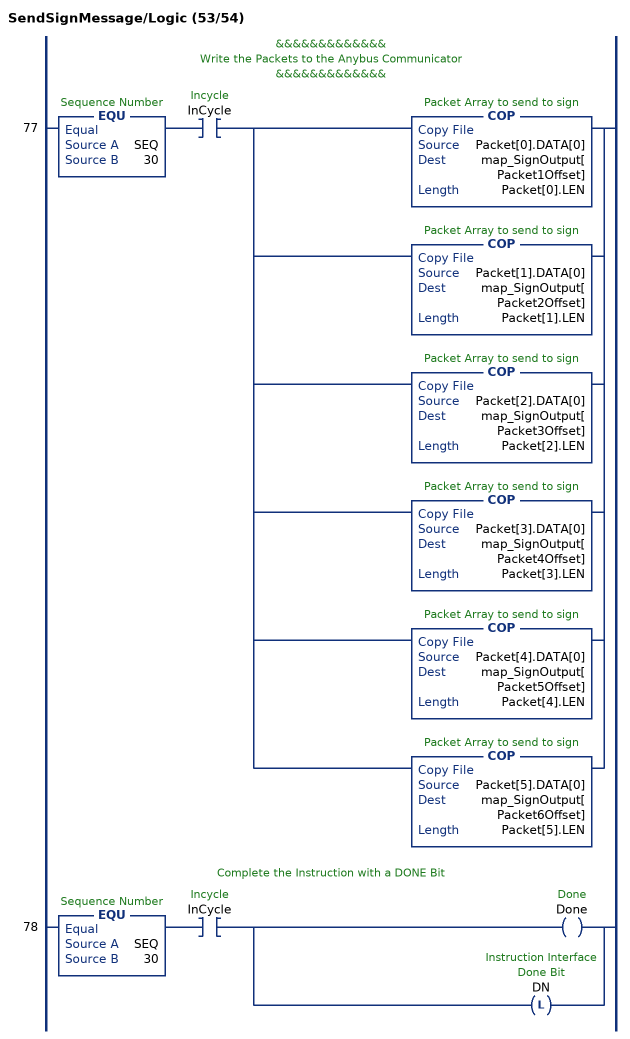
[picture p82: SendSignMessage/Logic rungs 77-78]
   // &&&&&&&&&&&&&
   // Write the Packets to the Anybus Communicator
   // &&&&&&&&&&&&&
   77: EQU(SEQ,30)XIC(InCycle)[COP(Packet[0].DATA[0],map_SignOutput[Packet1Offset],Packet[0].LEN) ,COP(Packet[1].DATA[0],map_SignOutput[Packet2Offset],Packet[1].LEN) ,COP(Packet[2].DATA[0],map_SignOutput[Packet3Offset],Packet[2].LEN) ,COP(Packet[3].DATA[0],map_SignOutput[Packet4Offset],Packet[3].LEN) ,COP(Packet[4].DATA[0],map_SignOutput[Packet5Offset],Packet[4].LEN) ,COP(Packet[5].DATA[0],map_SignOutput[Packet6Offset],Packet[5].LEN) ];
   // Complete the Instruction with a DONE Bit
   78: EQU(SEQ,30)XIC(InCycle)[OTE(Done) ,OTL(DN) ];
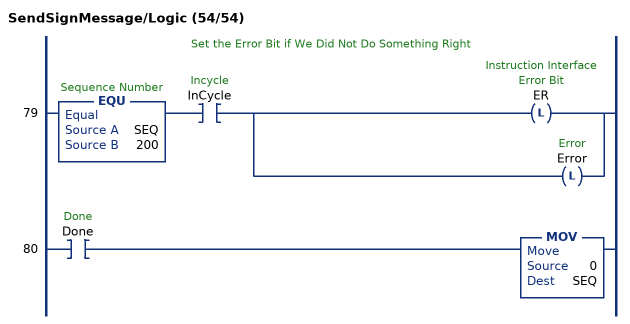
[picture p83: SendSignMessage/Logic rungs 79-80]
   // Set the Error Bit if We Did Not Do Something Right
   79: EQU(SEQ,200)XIC(InCycle)[OTL(ER) ,OTL(Error) ];
   80: XIC(Done)MOV(0,SEQ);
END_ROUTINE
END_ADD_ON_INSTRUCTION

ADD_ON_INSTRUCTION SetupSignVariables   (* revision 1.0, ExecuteEnableInFalse *)
// Setup to
// Four Variables
// to LED Sign
// Revision note:
// Original Release
// 11-01-2012
// c.elston
VAR_IN_OUT
   Address : STRING; {required}   // "00" = all signs "01" = address 01 "02" = address 02 etc...(see protocol)
   FileLabel : STRING; {required}   // "A" = default etc...(see protocol)
END_VAR
VAR_INPUT
   ENVariable1Message : BOOL; {visible}   // 0 = don't setup variable 1 = setup variable
END_VAR
VAR_IN_OUT
   Variable1Name : STRING; {required}   // Name of variable Default is = U
END_VAR
VAR_INPUT
   ENVariable2Message : BOOL; {visible}   // 0 = don't setup variable 1 = setup variable
END_VAR
VAR_IN_OUT
   Variable2Name : STRING; {required}   // Name of variable Default is = V
END_VAR
VAR_INPUT
   ENVariable3Message : BOOL; {visible}   // 0 = don't setup variable 1 = setup variable
END_VAR
VAR_IN_OUT
   Variable3Name : STRING; {required}   // Name of variable Default is = W
END_VAR
VAR_INPUT
   ENVariable4Message : BOOL; {visible}   // 0 = don't setup variable 1 = setup variable
END_VAR
VAR_IN_OUT
   Variable4Name : STRING; {required}   // Name of variable Default is = X
END_VAR
VAR_OUTPUT
   EN : BOOL; {visible}   // Instruction Interface Enable Bit
   DN : BOOL; {visible}   // Instruction Interface Done Bit
   ER : BOOL; {visible}   // Instruction Interface Error Bit
   IP : BOOL; {visible}   // Instruction Interface InProcess Bit
END_VAR
VAR_IN_OUT
   map_SignInput : SINT[32]; {required}   // Ethernet/IP LEDSIGN.I Data I/O Mapping
   map_SignOutput : SINT[496]; {required}   // Ethernet/IP LEDSIGN.O Data I/O Mapping
   Packet1Sent : STRING; {required}   // The actual packet sent to the sign (Packet1)
   Packet2Sent : STRING; {required}   // The actual packet sent to the sign (Packet2)
   Packet3Sent : STRING; {required}   // The actual packet sent to the sign (Packet3)
END_VAR
VAR
   SEQ : DINT;   // Sequence Number
   OktoCycle : BOOL;   // Ok to Cycle
   InCycle : BOOL;   // Incycle
   Error : BOOL;   // Error
   Enabled : BOOL;   // Enable ON Bit
   Done : BOOL;   // Done
   Disabled : BOOL;   // Disabled OFF Bit
   SignETX : STRING := '^C';   // DO NOT EDIT = ^C
   SignFileLabel : STRING;
   SignSOH : STRING := '^A';   // DO NOT EDIT = ^A
   SignAddress : STRING;
   SignSTX : STRING := '^B';   // DO NOT EDIT = ^B
   SignNULL : STRING;
   SignVariable4 : STRING;
   SignVariable3 : STRING;
   SignVariable2 : STRING;
   SignVariable1 : STRING;
   SignSetMemoryCommand : STRING := 'SM';   // DO NOT EDIT = SM
   SignCommandCode : STRING := 'C';   // DO NOT EDIT = C
   SignSizeVariableCommand : STRING := '0010';   // DO NOT EDIT = 0010 (16 bytes of memory) enough for 16 characters
   SignFileVariableCommand : STRING := 'V';   // DO NOT EDIT = V
   TotalPacketCount : DINT[7];   // Total Character Count
   Select : DINT;   // Packet Array Select
   PacketMax : DINT := 82;   // Max Packet Count
   PacketCount : DINT[7];
   Packet6Offset : DINT;
   Packet5Offset : DINT;
   Packet4Offset : DINT;
   Packet3Offset : DINT;
   Packet2Offset : DINT;
   Packet1Offset : DINT;
   Packet : STRING[7];   // Packet Array to send to sign
END_VAR

ROUTINE EnableInFalse   (* ladder *)
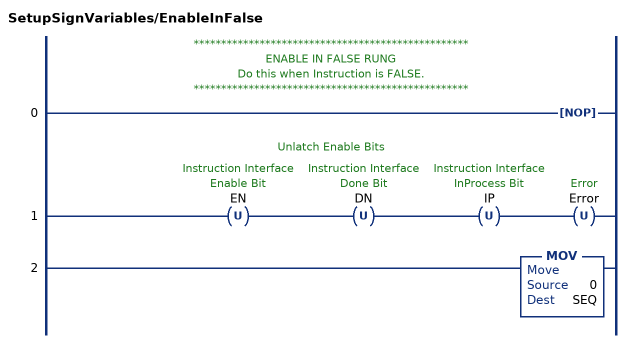
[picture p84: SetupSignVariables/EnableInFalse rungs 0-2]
   // **************************************************
   // ENABLE IN FALSE RUNG
   // Do this when Instruction is FALSE.
   // **************************************************
   0: NOP();
   // Unlatch Enable Bits
   1: OTU(EN)OTU(DN)OTU(IP)OTU(Error);
   2: MOV(0,SEQ);
END_ROUTINE

ROUTINE Logic   (* ladder *)
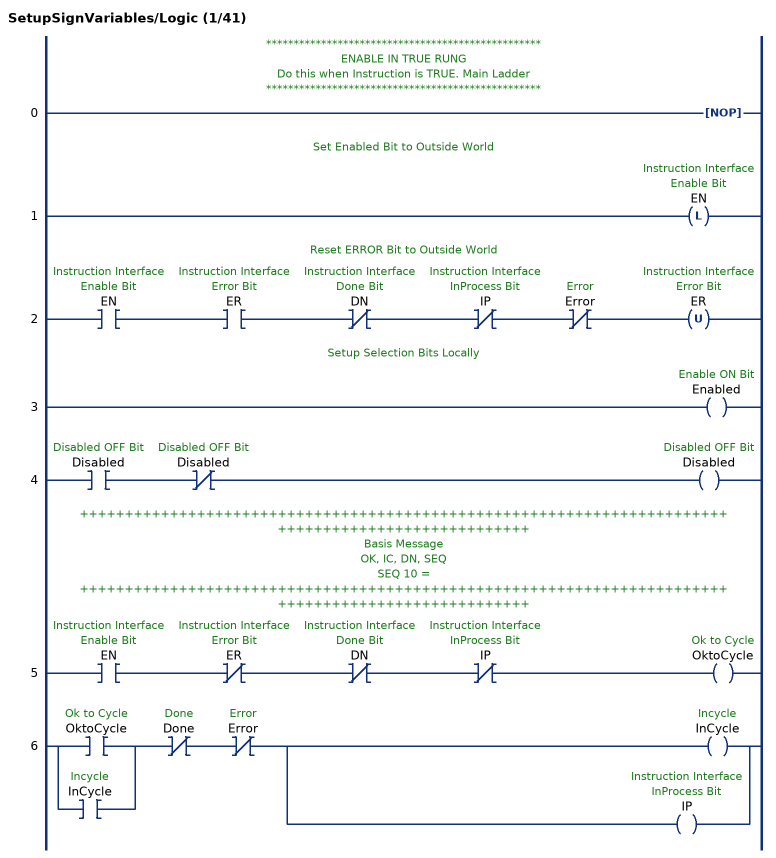
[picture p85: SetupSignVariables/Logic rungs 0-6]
   // **************************************************
   // ENABLE IN TRUE RUNG
   // Do this when Instruction is TRUE. Main Ladder
   // **************************************************
   0: NOP();
   // Set Enabled Bit to Outside World
   1: OTL(EN);
   // Reset ERROR Bit to Outside World
   2: XIC(EN)XIC(ER)XIO(DN)XIO(IP)XIO(Error)OTU(ER);
   // Setup Selection Bits Locally
   3: OTE(Enabled);
   4: XIC(Disabled)XIO(Disabled)OTE(Disabled);
   // ++++++++++++++++++++++++++++++++++++++++++++++++++++++++++++++++++++++++++++++++++++++++++++++++++++
   // Basis Message
   // OK, IC, DN, SEQ
   // SEQ 10 =
   // ++++++++++++++++++++++++++++++++++++++++++++++++++++++++++++++++++++++++++++++++++++++++++++++++++++
   5: XIC(EN)XIO(ER)XIO(DN)XIO(IP)OTE(OktoCycle);
   6: [XIC(OktoCycle) ,XIC(InCycle) ]XIO(Done)XIO(Error)[OTE(InCycle) ,OTE(IP) ];
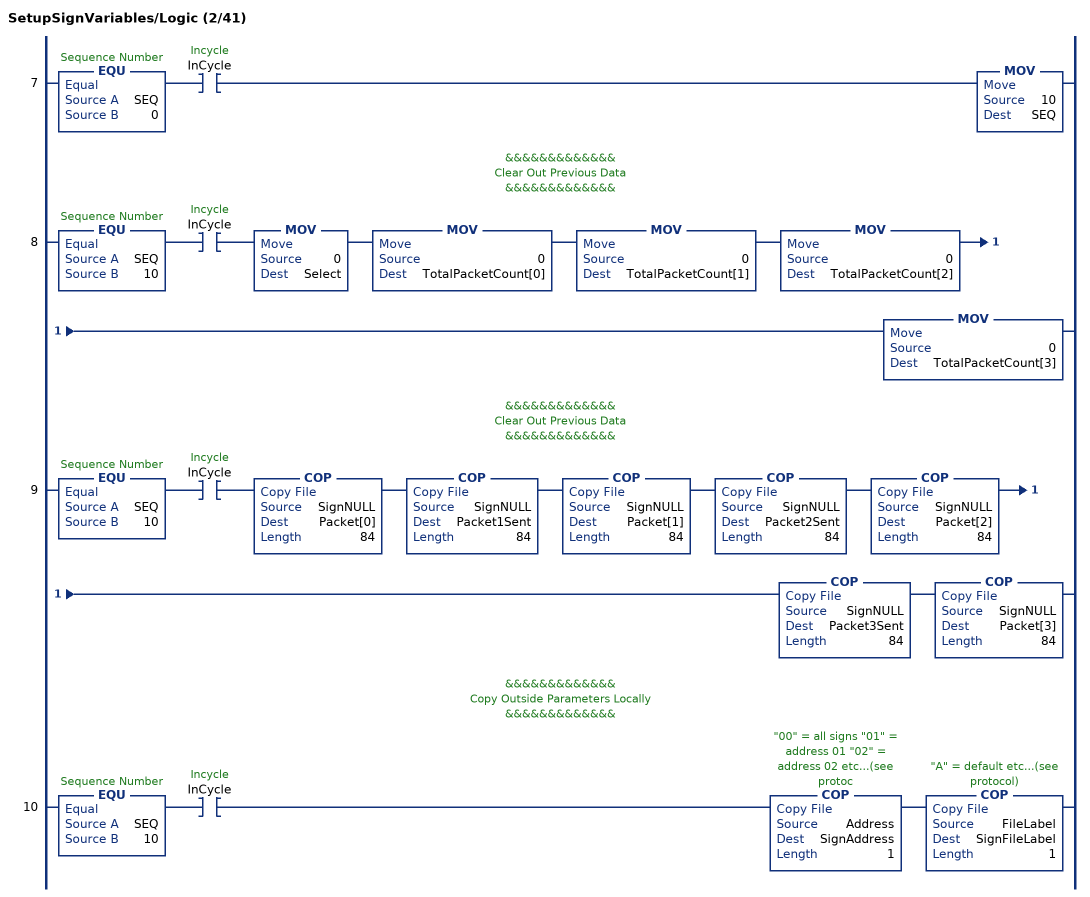
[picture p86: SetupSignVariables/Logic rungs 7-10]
   7: EQU(SEQ,0)XIC(InCycle)MOV(10,SEQ);
   // &&&&&&&&&&&&&
   // Clear Out Previous Data
   // &&&&&&&&&&&&&
   8: EQU(SEQ,10)XIC(InCycle)MOV(0,Select)MOV(0,TotalPacketCount[0])MOV(0,TotalPacketCount[1])MOV(0,TotalPacketCount[2])MOV(0,TotalPacketCount[3]);
   // &&&&&&&&&&&&&
   // Clear Out Previous Data
   // &&&&&&&&&&&&&
   9: EQU(SEQ,10)XIC(InCycle)COP(SignNULL,Packet[0],84)COP(SignNULL,Packet1Sent,84)COP(SignNULL,Packet[1],84)COP(SignNULL,Packet2Sent,84)COP(SignNULL,Packet[2],84)COP(SignNULL,Packet3Sent,84)COP(SignNULL,Packet[3],84);
   // &&&&&&&&&&&&&
   // Copy Outside Parameters Locally
   // &&&&&&&&&&&&&
   10: EQU(SEQ,10)XIC(InCycle)COP(Address,SignAddress,1)COP(FileLabel,SignFileLabel,1);
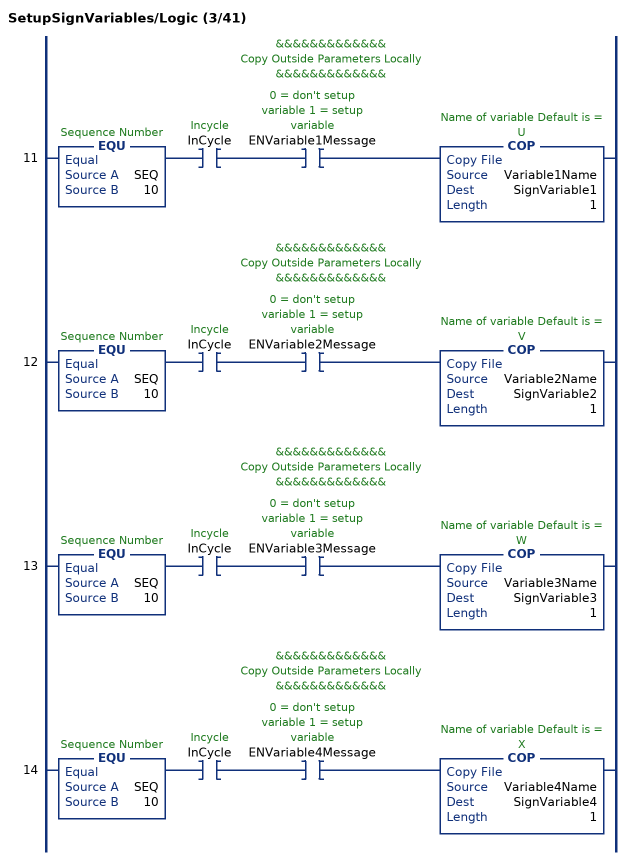
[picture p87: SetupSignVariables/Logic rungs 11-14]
   // &&&&&&&&&&&&&
   // Copy Outside Parameters Locally
   // &&&&&&&&&&&&&
   11: EQU(SEQ,10)XIC(InCycle)XIC(ENVariable1Message)COP(Variable1Name,SignVariable1,1);
   // &&&&&&&&&&&&&
   // Copy Outside Parameters Locally
   // &&&&&&&&&&&&&
   12: EQU(SEQ,10)XIC(InCycle)XIC(ENVariable2Message)COP(Variable2Name,SignVariable2,1);
   // &&&&&&&&&&&&&
   // Copy Outside Parameters Locally
   // &&&&&&&&&&&&&
   13: EQU(SEQ,10)XIC(InCycle)XIC(ENVariable3Message)COP(Variable3Name,SignVariable3,1);
   // &&&&&&&&&&&&&
   // Copy Outside Parameters Locally
   // &&&&&&&&&&&&&
   14: EQU(SEQ,10)XIC(InCycle)XIC(ENVariable4Message)COP(Variable4Name,SignVariable4,1);
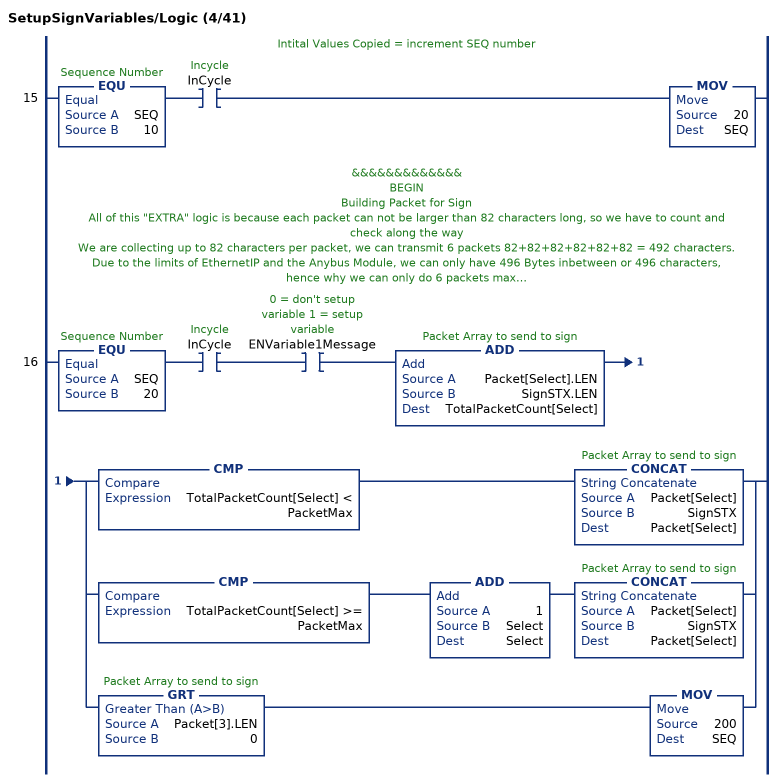
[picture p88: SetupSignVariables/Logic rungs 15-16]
   // Intital Values Copied = increment SEQ number
   15: EQU(SEQ,10)XIC(InCycle)MOV(20,SEQ);
   // &&&&&&&&&&&&&
   // BEGIN
   // Building Packet for Sign
   // All of this "EXTRA" logic is because each packet can not be larger than 82 characters long, so we have to count and check along the way
   // We are collecting up to 82 characters per packet, we can transmit 6 packets 82+82+82+82+82+82 = 492 characters.
   // Due to the limits of EthernetIP and the Anybus Module, we can only have 496 Bytes inbetween or 496 characters, hence why we can only do 6 packets max.
   // Once we exceed this, we will fault and ERROR trap any windy typing people.
   // In this instruction below, it's so small, we are only using 3 packets max.
   // &&&&&&&&&&&&&
   16: EQU(SEQ,20)XIC(InCycle)XIC(ENVariable1Message)ADD(Packet[Select].LEN,SignSTX.LEN,TotalPacketCount[Select])[CMP(TotalPacketCount[Select] < PacketMax) CONCAT(Packet[Select],SignSTX,Packet[Select]) ,CMP(TotalPacketCount[Select] >= PacketMax) ADD(1,Select,Select) CONCAT(Packet[Select],SignSTX,Packet[Select]) ,GRT(Packet[3].LEN,0) MOV(200,SEQ) ];
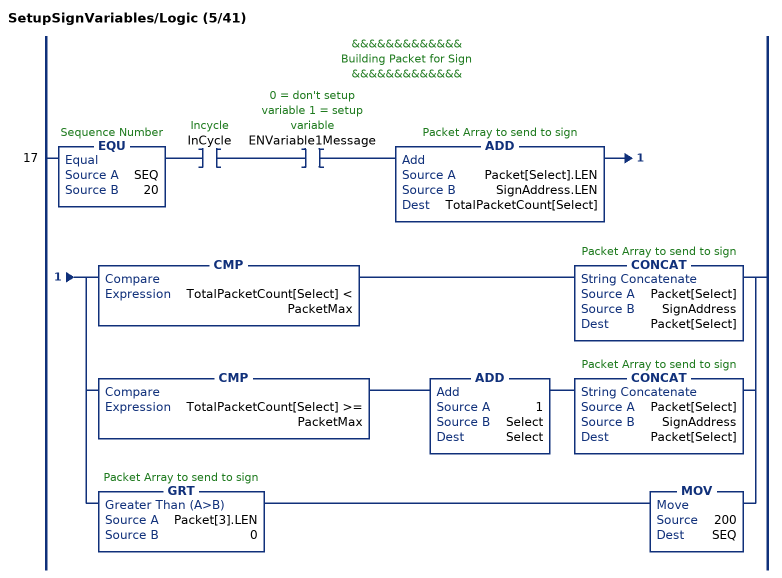
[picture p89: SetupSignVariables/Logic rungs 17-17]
   // &&&&&&&&&&&&&
   // Building Packet for Sign
   // &&&&&&&&&&&&&
   17: EQU(SEQ,20)XIC(InCycle)XIC(ENVariable1Message)ADD(Packet[Select].LEN,SignAddress.LEN,TotalPacketCount[Select])[CMP(TotalPacketCount[Select] < PacketMax) CONCAT(Packet[Select],SignAddress,Packet[Select]) ,CMP(TotalPacketCount[Select] >= PacketMax) ADD(1,Select,Select) CONCAT(Packet[Select],SignAddress,Packet[Select]) ,GRT(Packet[3].LEN,0) MOV(200,SEQ) ];
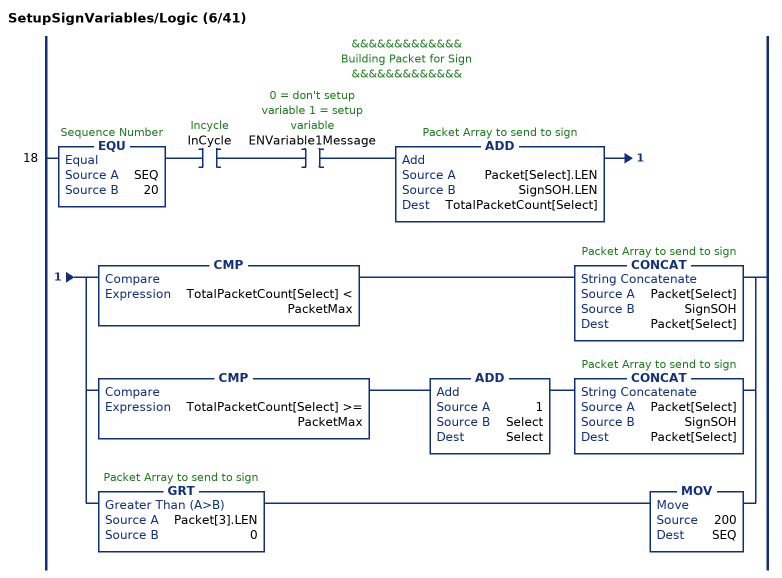
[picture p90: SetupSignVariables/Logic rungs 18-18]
   // &&&&&&&&&&&&&
   // Building Packet for Sign
   // &&&&&&&&&&&&&
   18: EQU(SEQ,20)XIC(InCycle)XIC(ENVariable1Message)ADD(Packet[Select].LEN,SignSOH.LEN,TotalPacketCount[Select])[CMP(TotalPacketCount[Select] < PacketMax) CONCAT(Packet[Select],SignSOH,Packet[Select]) ,CMP(TotalPacketCount[Select] >= PacketMax) ADD(1,Select,Select) CONCAT(Packet[Select],SignSOH,Packet[Select]) ,GRT(Packet[3].LEN,0) MOV(200,SEQ) ];
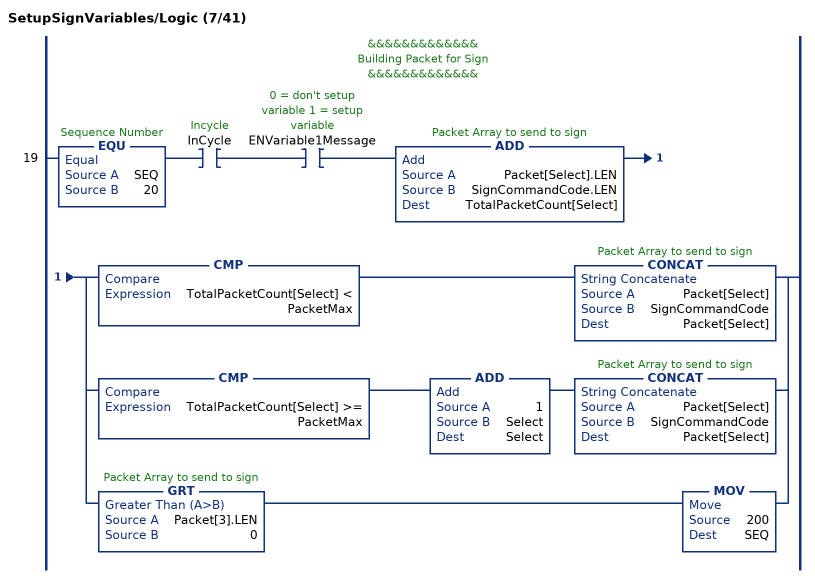
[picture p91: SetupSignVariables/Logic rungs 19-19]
   // &&&&&&&&&&&&&
   // Building Packet for Sign
   // &&&&&&&&&&&&&
   19: EQU(SEQ,20)XIC(InCycle)XIC(ENVariable1Message)ADD(Packet[Select].LEN,SignCommandCode.LEN,TotalPacketCount[Select])[CMP(TotalPacketCount[Select] < PacketMax) CONCAT(Packet[Select],SignCommandCode,Packet[Select]) ,CMP(TotalPacketCount[Select] >= PacketMax) ADD(1,Select,Select) CONCAT(Packet[Select],SignCommandCode,Packet[Select]) ,GRT(Packet[3].LEN,0) MOV(200,SEQ) ];
(* Logix 5000 project; controller Electronic_Displays vendor 1 type 14 code 65 rev 17.4; software revision 17.01; part 5 of 8 *)
(* tags used below, declared in another part *)
   ENVariable1Message : BOOL;   // 0 = don't setup variable 1 = setup variable
   ENVariable2Message : BOOL;   // 0 = don't setup variable 1 = setup variable
   ENVariable3Message : BOOL;   // 0 = don't setup variable 1 = setup variable
   ENVariable4Message : BOOL;   // 0 = don't setup variable 1 = setup variable
   SEQ : DINT;   // Sequence Number
   InCycle : BOOL;   // Incycle
   SignETX : STRING;   // DO NOT EDIT = ^C
   SignSOH : STRING;   // DO NOT EDIT = ^A
   SignAddress : STRING;
   SignSTX : STRING;   // DO NOT EDIT = ^B
   SignVariable3 : STRING;
   SignVariable2 : STRING;
   SignVariable1 : STRING;
   SignSetMemoryCommand : STRING;   // DO NOT EDIT = SM
   SignCommandCode : STRING;   // DO NOT EDIT = C
   SignSizeVariableCommand : STRING;   // DO NOT EDIT = 0010 (16 bytes of memory) enough for 16 characters
   SignFileVariableCommand : STRING;   // DO NOT EDIT = V
   TotalPacketCount : DINT[7];   // Total Character Count
   Select : DINT;   // Packet Array Select
   PacketMax : DINT;   // Max Packet Count
   Packet : STRING[7];   // Packet Array to send to sign
(* SetupSignVariables, continued *)

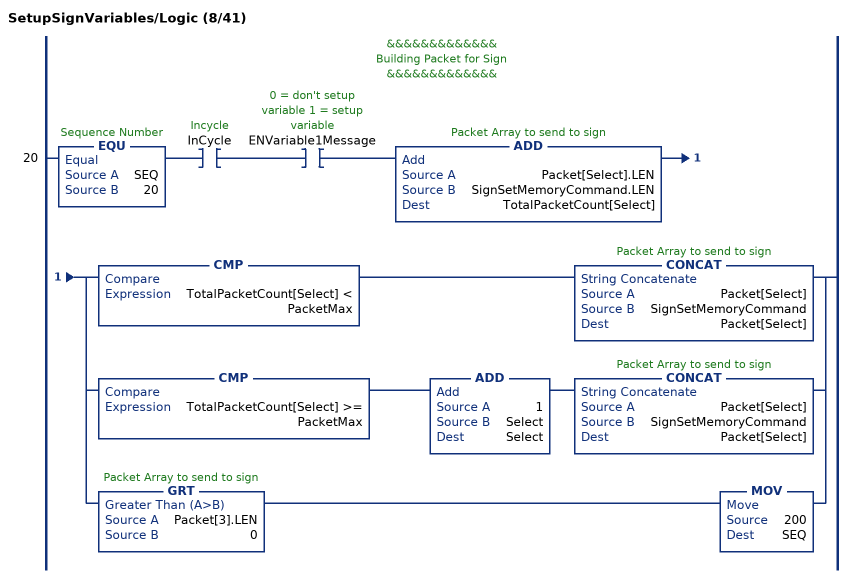
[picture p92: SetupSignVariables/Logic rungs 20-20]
   // &&&&&&&&&&&&&
   // Building Packet for Sign
   // &&&&&&&&&&&&&
   20: EQU(SEQ,20)XIC(InCycle)XIC(ENVariable1Message)ADD(Packet[Select].LEN,SignSetMemoryCommand.LEN,TotalPacketCount[Select])[CMP(TotalPacketCount[Select] < PacketMax) CONCAT(Packet[Select],SignSetMemoryCommand,Packet[Select]) ,CMP(TotalPacketCount[Select] >= PacketMax) ADD(1,Select,Select) CONCAT(Packet[Select],SignSetMemoryCommand,Packet[Select]) ,GRT(Packet[3].LEN,0) MOV(200,SEQ) ];
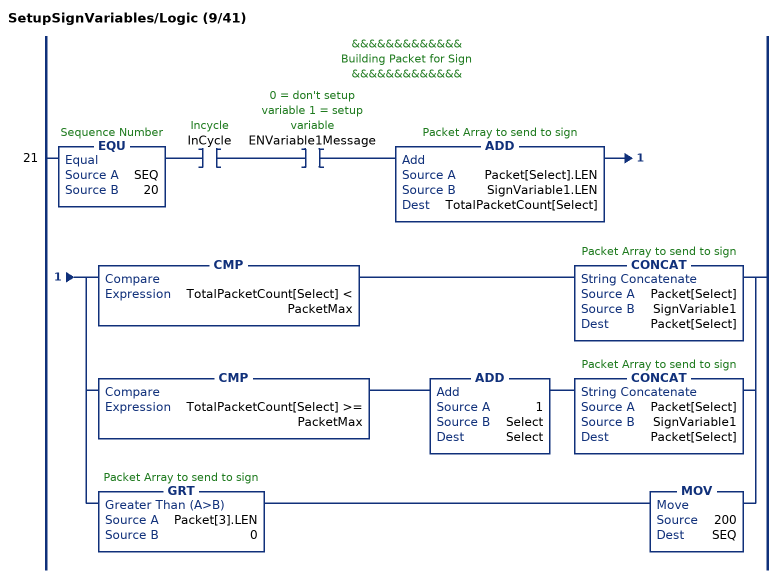
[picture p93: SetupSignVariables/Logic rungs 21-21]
   // &&&&&&&&&&&&&
   // Building Packet for Sign
   // &&&&&&&&&&&&&
   21: EQU(SEQ,20)XIC(InCycle)XIC(ENVariable1Message)ADD(Packet[Select].LEN,SignVariable1.LEN,TotalPacketCount[Select])[CMP(TotalPacketCount[Select] < PacketMax) CONCAT(Packet[Select],SignVariable1,Packet[Select]) ,CMP(TotalPacketCount[Select] >= PacketMax) ADD(1,Select,Select) CONCAT(Packet[Select],SignVariable1,Packet[Select]) ,GRT(Packet[3].LEN,0) MOV(200,SEQ) ];
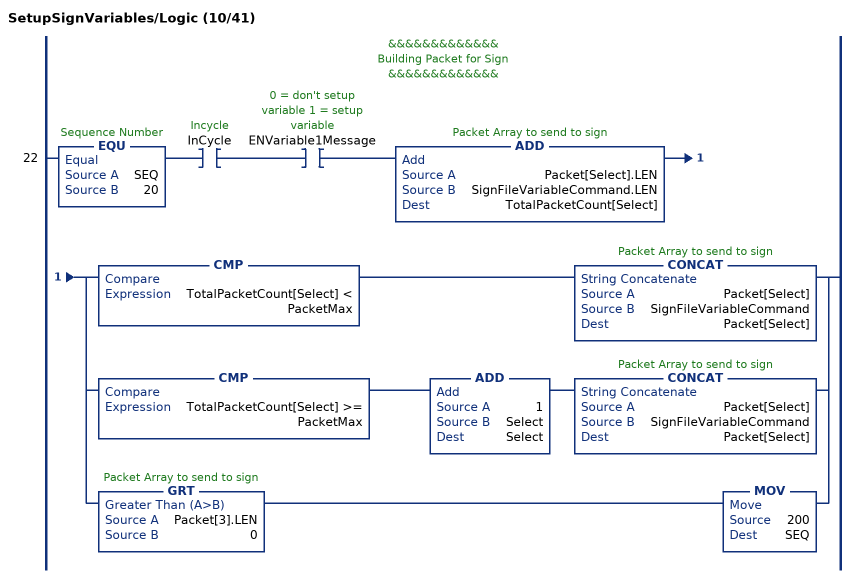
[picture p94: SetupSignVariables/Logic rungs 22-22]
   // &&&&&&&&&&&&&
   // Building Packet for Sign
   // &&&&&&&&&&&&&
   22: EQU(SEQ,20)XIC(InCycle)XIC(ENVariable1Message)ADD(Packet[Select].LEN,SignFileVariableCommand.LEN,TotalPacketCount[Select])[CMP(TotalPacketCount[Select] < PacketMax) CONCAT(Packet[Select],SignFileVariableCommand,Packet[Select]) ,CMP(TotalPacketCount[Select] >= PacketMax) ADD(1,Select,Select) CONCAT(Packet[Select],SignFileVariableCommand,Packet[Select]) ,GRT(Packet[3].LEN,0) MOV(200,SEQ) ];
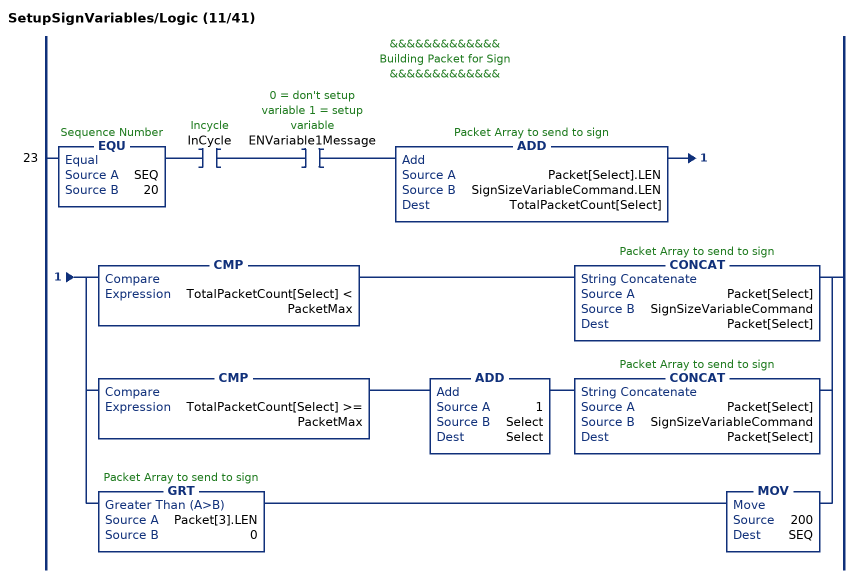
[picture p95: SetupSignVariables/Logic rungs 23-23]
   // &&&&&&&&&&&&&
   // Building Packet for Sign
   // &&&&&&&&&&&&&
   23: EQU(SEQ,20)XIC(InCycle)XIC(ENVariable1Message)ADD(Packet[Select].LEN,SignSizeVariableCommand.LEN,TotalPacketCount[Select])[CMP(TotalPacketCount[Select] < PacketMax) CONCAT(Packet[Select],SignSizeVariableCommand,Packet[Select]) ,CMP(TotalPacketCount[Select] >= PacketMax) ADD(1,Select,Select) CONCAT(Packet[Select],SignSizeVariableCommand,Packet[Select]) ,GRT(Packet[3].LEN,0) MOV(200,SEQ) ];
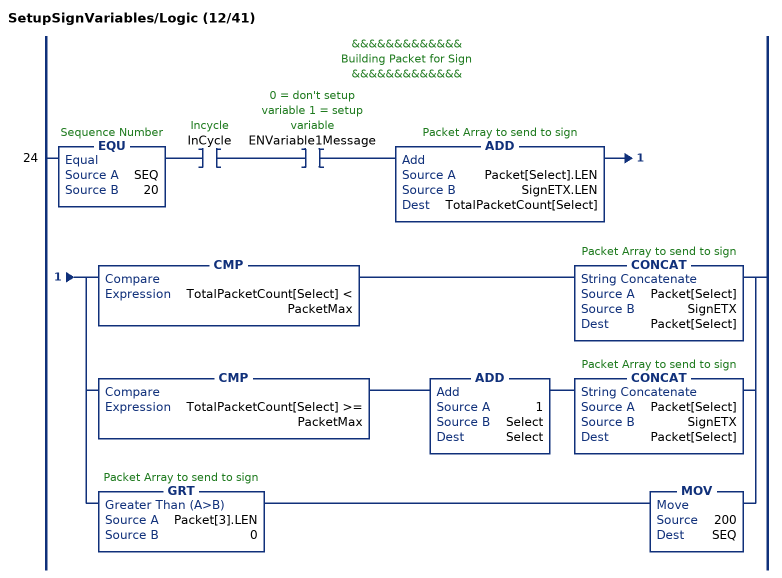
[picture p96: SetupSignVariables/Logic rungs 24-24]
   // &&&&&&&&&&&&&
   // Building Packet for Sign
   // &&&&&&&&&&&&&
   24: EQU(SEQ,20)XIC(InCycle)XIC(ENVariable1Message)ADD(Packet[Select].LEN,SignETX.LEN,TotalPacketCount[Select])[CMP(TotalPacketCount[Select] < PacketMax) CONCAT(Packet[Select],SignETX,Packet[Select]) ,CMP(TotalPacketCount[Select] >= PacketMax) ADD(1,Select,Select) CONCAT(Packet[Select],SignETX,Packet[Select]) ,GRT(Packet[3].LEN,0) MOV(200,SEQ) ];
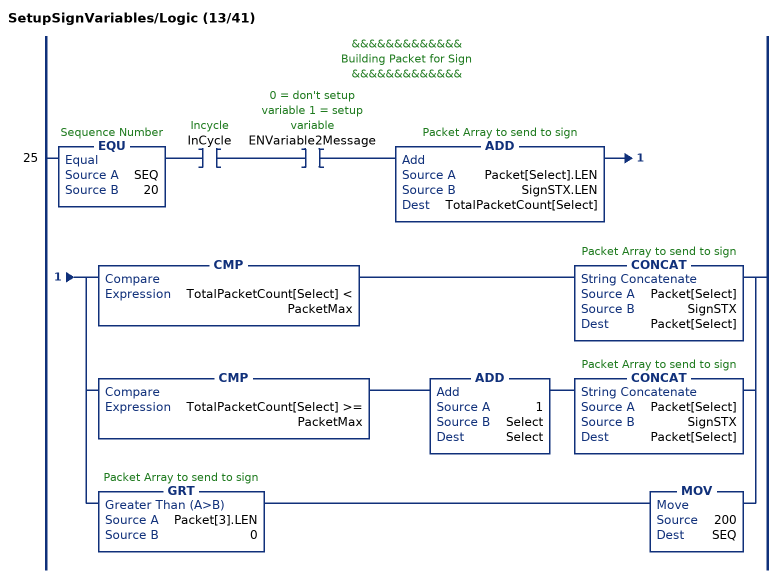
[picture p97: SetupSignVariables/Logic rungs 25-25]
   // &&&&&&&&&&&&&
   // Building Packet for Sign
   // &&&&&&&&&&&&&
   25: EQU(SEQ,20)XIC(InCycle)XIC(ENVariable2Message)ADD(Packet[Select].LEN,SignSTX.LEN,TotalPacketCount[Select])[CMP(TotalPacketCount[Select] < PacketMax) CONCAT(Packet[Select],SignSTX,Packet[Select]) ,CMP(TotalPacketCount[Select] >= PacketMax) ADD(1,Select,Select) CONCAT(Packet[Select],SignSTX,Packet[Select]) ,GRT(Packet[3].LEN,0) MOV(200,SEQ) ];
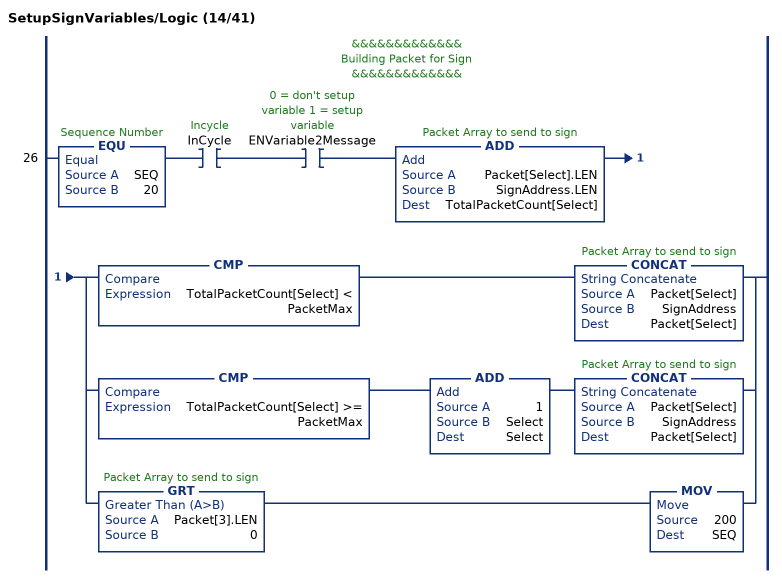
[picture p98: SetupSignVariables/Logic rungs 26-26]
   // &&&&&&&&&&&&&
   // Building Packet for Sign
   // &&&&&&&&&&&&&
   26: EQU(SEQ,20)XIC(InCycle)XIC(ENVariable2Message)ADD(Packet[Select].LEN,SignAddress.LEN,TotalPacketCount[Select])[CMP(TotalPacketCount[Select] < PacketMax) CONCAT(Packet[Select],SignAddress,Packet[Select]) ,CMP(TotalPacketCount[Select] >= PacketMax) ADD(1,Select,Select) CONCAT(Packet[Select],SignAddress,Packet[Select]) ,GRT(Packet[3].LEN,0) MOV(200,SEQ) ];
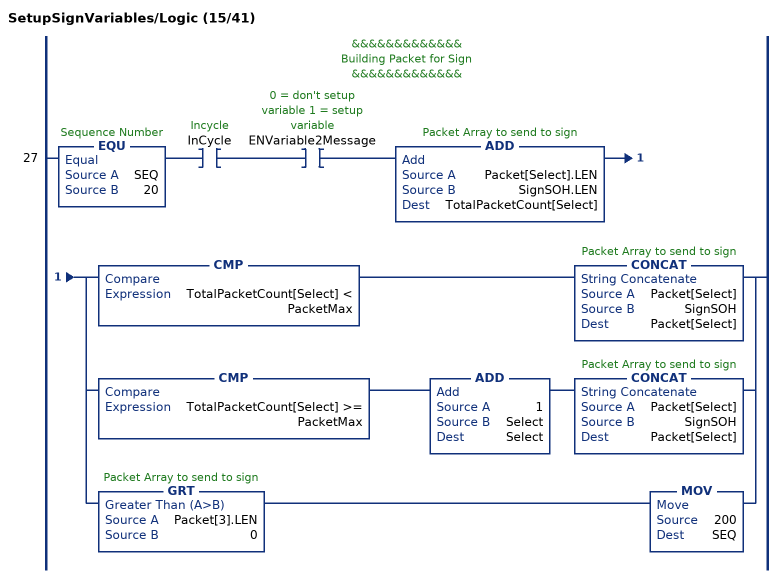
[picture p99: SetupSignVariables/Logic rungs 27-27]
   // &&&&&&&&&&&&&
   // Building Packet for Sign
   // &&&&&&&&&&&&&
   27: EQU(SEQ,20)XIC(InCycle)XIC(ENVariable2Message)ADD(Packet[Select].LEN,SignSOH.LEN,TotalPacketCount[Select])[CMP(TotalPacketCount[Select] < PacketMax) CONCAT(Packet[Select],SignSOH,Packet[Select]) ,CMP(TotalPacketCount[Select] >= PacketMax) ADD(1,Select,Select) CONCAT(Packet[Select],SignSOH,Packet[Select]) ,GRT(Packet[3].LEN,0) MOV(200,SEQ) ];
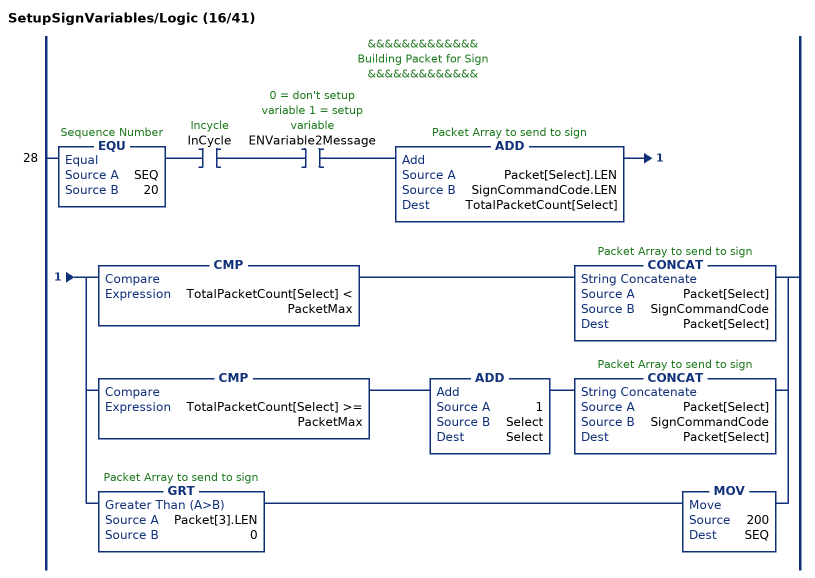
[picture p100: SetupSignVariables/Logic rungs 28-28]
   // &&&&&&&&&&&&&
   // Building Packet for Sign
   // &&&&&&&&&&&&&
   28: EQU(SEQ,20)XIC(InCycle)XIC(ENVariable2Message)ADD(Packet[Select].LEN,SignCommandCode.LEN,TotalPacketCount[Select])[CMP(TotalPacketCount[Select] < PacketMax) CONCAT(Packet[Select],SignCommandCode,Packet[Select]) ,CMP(TotalPacketCount[Select] >= PacketMax) ADD(1,Select,Select) CONCAT(Packet[Select],SignCommandCode,Packet[Select]) ,GRT(Packet[3].LEN,0) MOV(200,SEQ) ];
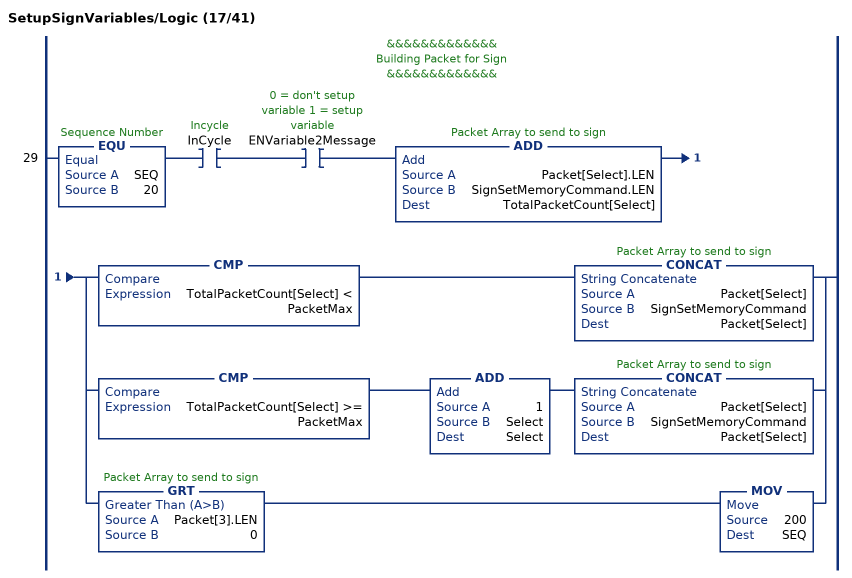
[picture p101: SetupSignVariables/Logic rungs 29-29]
   // &&&&&&&&&&&&&
   // Building Packet for Sign
   // &&&&&&&&&&&&&
   29: EQU(SEQ,20)XIC(InCycle)XIC(ENVariable2Message)ADD(Packet[Select].LEN,SignSetMemoryCommand.LEN,TotalPacketCount[Select])[CMP(TotalPacketCount[Select] < PacketMax) CONCAT(Packet[Select],SignSetMemoryCommand,Packet[Select]) ,CMP(TotalPacketCount[Select] >= PacketMax) ADD(1,Select,Select) CONCAT(Packet[Select],SignSetMemoryCommand,Packet[Select]) ,GRT(Packet[3].LEN,0) MOV(200,SEQ) ];
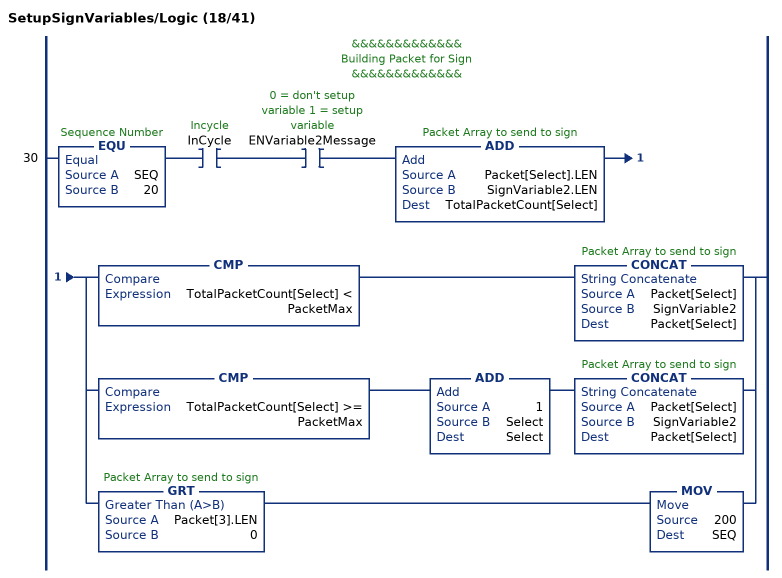
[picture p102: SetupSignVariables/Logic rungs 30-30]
   // &&&&&&&&&&&&&
   // Building Packet for Sign
   // &&&&&&&&&&&&&
   30: EQU(SEQ,20)XIC(InCycle)XIC(ENVariable2Message)ADD(Packet[Select].LEN,SignVariable2.LEN,TotalPacketCount[Select])[CMP(TotalPacketCount[Select] < PacketMax) CONCAT(Packet[Select],SignVariable2,Packet[Select]) ,CMP(TotalPacketCount[Select] >= PacketMax) ADD(1,Select,Select) CONCAT(Packet[Select],SignVariable2,Packet[Select]) ,GRT(Packet[3].LEN,0) MOV(200,SEQ) ];
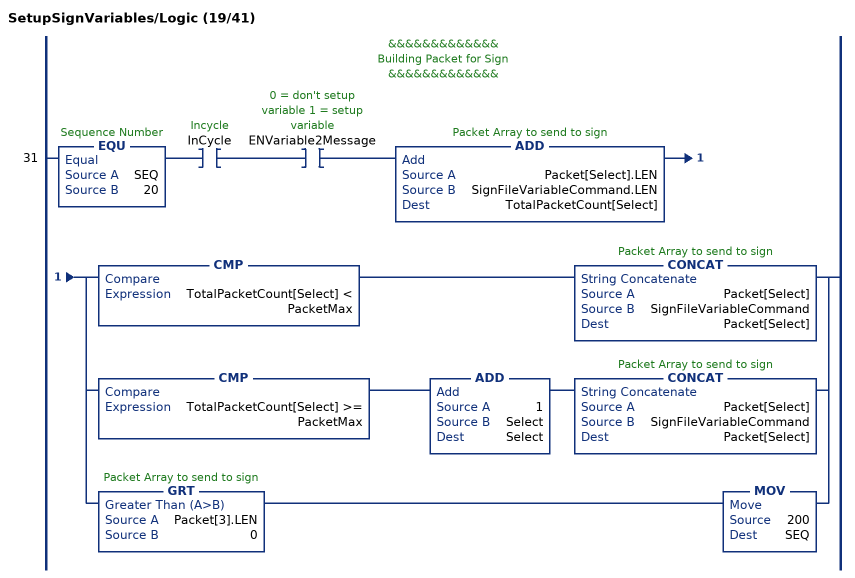
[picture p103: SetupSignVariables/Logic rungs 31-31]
   // &&&&&&&&&&&&&
   // Building Packet for Sign
   // &&&&&&&&&&&&&
   31: EQU(SEQ,20)XIC(InCycle)XIC(ENVariable2Message)ADD(Packet[Select].LEN,SignFileVariableCommand.LEN,TotalPacketCount[Select])[CMP(TotalPacketCount[Select] < PacketMax) CONCAT(Packet[Select],SignFileVariableCommand,Packet[Select]) ,CMP(TotalPacketCount[Select] >= PacketMax) ADD(1,Select,Select) CONCAT(Packet[Select],SignFileVariableCommand,Packet[Select]) ,GRT(Packet[3].LEN,0) MOV(200,SEQ) ];
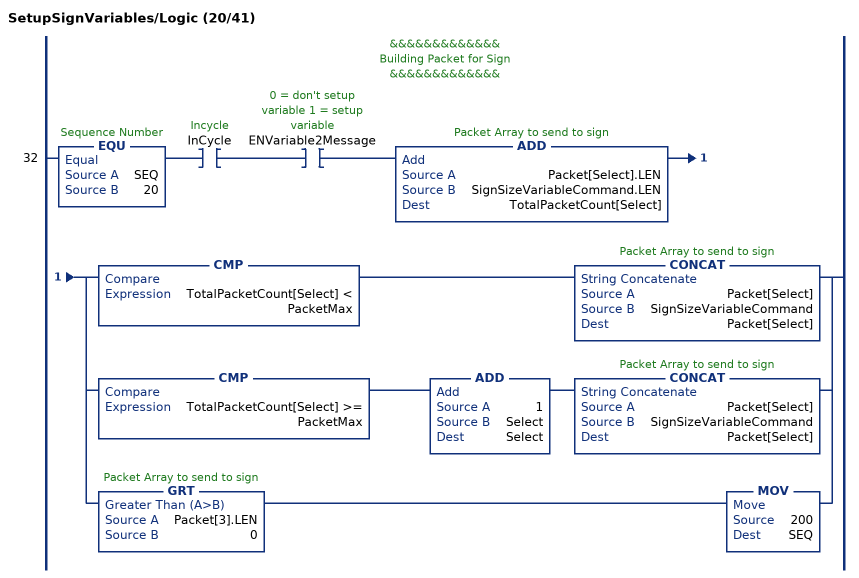
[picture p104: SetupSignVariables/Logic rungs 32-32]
   // &&&&&&&&&&&&&
   // Building Packet for Sign
   // &&&&&&&&&&&&&
   32: EQU(SEQ,20)XIC(InCycle)XIC(ENVariable2Message)ADD(Packet[Select].LEN,SignSizeVariableCommand.LEN,TotalPacketCount[Select])[CMP(TotalPacketCount[Select] < PacketMax) CONCAT(Packet[Select],SignSizeVariableCommand,Packet[Select]) ,CMP(TotalPacketCount[Select] >= PacketMax) ADD(1,Select,Select) CONCAT(Packet[Select],SignSizeVariableCommand,Packet[Select]) ,GRT(Packet[3].LEN,0) MOV(200,SEQ) ];
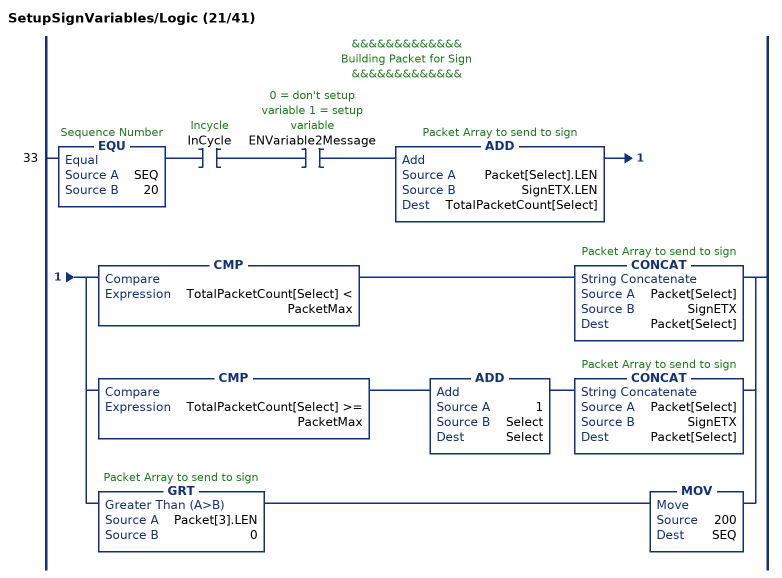
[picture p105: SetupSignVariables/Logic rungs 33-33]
   // &&&&&&&&&&&&&
   // Building Packet for Sign
   // &&&&&&&&&&&&&
   33: EQU(SEQ,20)XIC(InCycle)XIC(ENVariable2Message)ADD(Packet[Select].LEN,SignETX.LEN,TotalPacketCount[Select])[CMP(TotalPacketCount[Select] < PacketMax) CONCAT(Packet[Select],SignETX,Packet[Select]) ,CMP(TotalPacketCount[Select] >= PacketMax) ADD(1,Select,Select) CONCAT(Packet[Select],SignETX,Packet[Select]) ,GRT(Packet[3].LEN,0) MOV(200,SEQ) ];
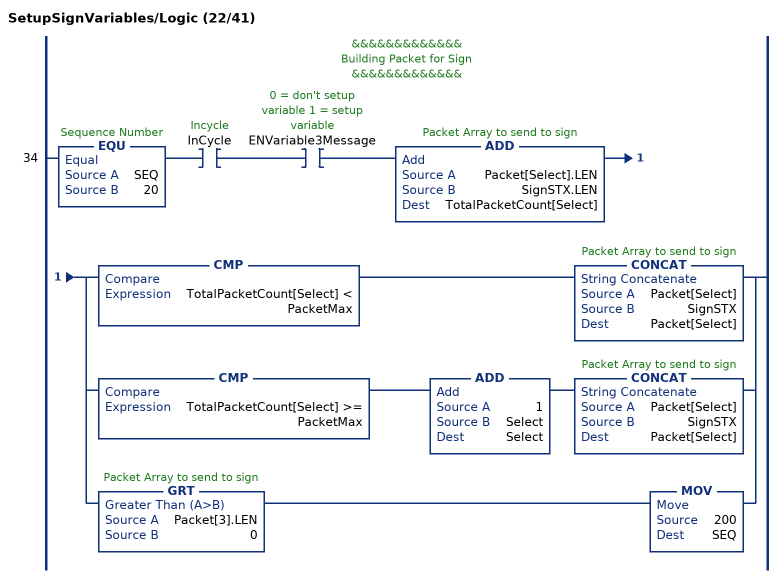
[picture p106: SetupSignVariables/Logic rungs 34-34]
   // &&&&&&&&&&&&&
   // Building Packet for Sign
   // &&&&&&&&&&&&&
   34: EQU(SEQ,20)XIC(InCycle)XIC(ENVariable3Message)ADD(Packet[Select].LEN,SignSTX.LEN,TotalPacketCount[Select])[CMP(TotalPacketCount[Select] < PacketMax) CONCAT(Packet[Select],SignSTX,Packet[Select]) ,CMP(TotalPacketCount[Select] >= PacketMax) ADD(1,Select,Select) CONCAT(Packet[Select],SignSTX,Packet[Select]) ,GRT(Packet[3].LEN,0) MOV(200,SEQ) ];
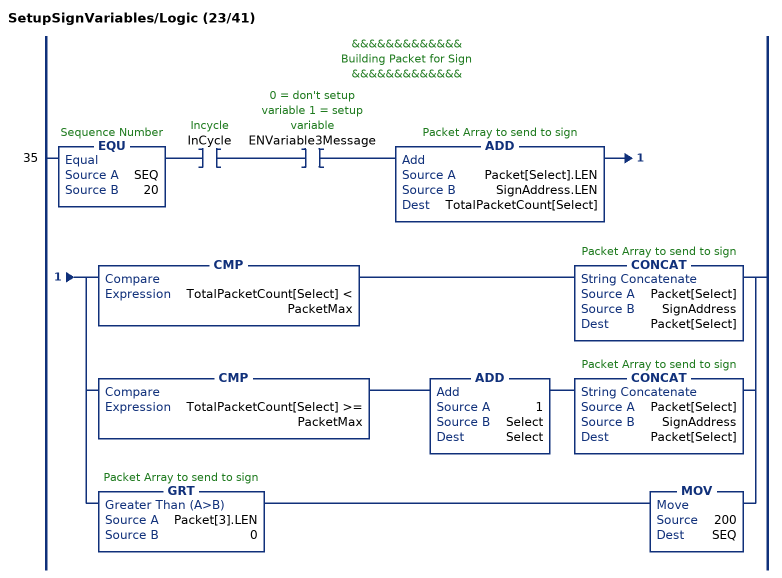
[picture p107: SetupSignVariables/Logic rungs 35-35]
   // &&&&&&&&&&&&&
   // Building Packet for Sign
   // &&&&&&&&&&&&&
   35: EQU(SEQ,20)XIC(InCycle)XIC(ENVariable3Message)ADD(Packet[Select].LEN,SignAddress.LEN,TotalPacketCount[Select])[CMP(TotalPacketCount[Select] < PacketMax) CONCAT(Packet[Select],SignAddress,Packet[Select]) ,CMP(TotalPacketCount[Select] >= PacketMax) ADD(1,Select,Select) CONCAT(Packet[Select],SignAddress,Packet[Select]) ,GRT(Packet[3].LEN,0) MOV(200,SEQ) ];
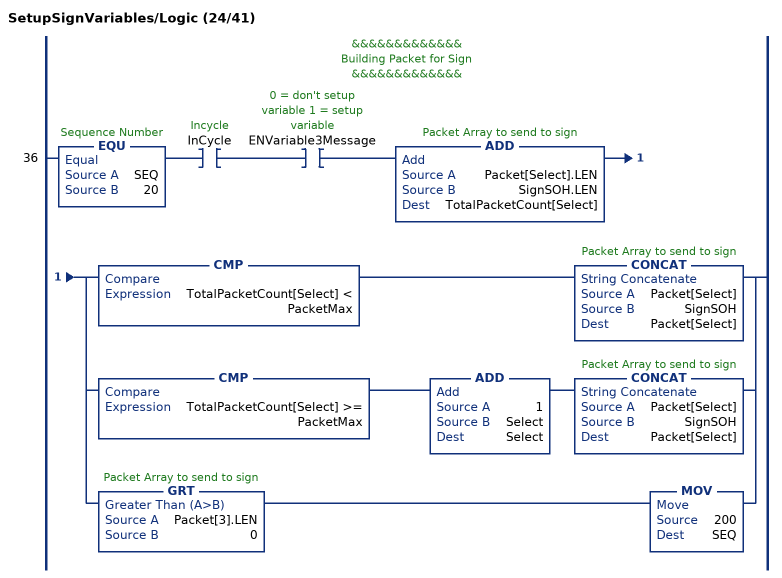
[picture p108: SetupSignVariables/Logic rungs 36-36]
   // &&&&&&&&&&&&&
   // Building Packet for Sign
   // &&&&&&&&&&&&&
   36: EQU(SEQ,20)XIC(InCycle)XIC(ENVariable3Message)ADD(Packet[Select].LEN,SignSOH.LEN,TotalPacketCount[Select])[CMP(TotalPacketCount[Select] < PacketMax) CONCAT(Packet[Select],SignSOH,Packet[Select]) ,CMP(TotalPacketCount[Select] >= PacketMax) ADD(1,Select,Select) CONCAT(Packet[Select],SignSOH,Packet[Select]) ,GRT(Packet[3].LEN,0) MOV(200,SEQ) ];
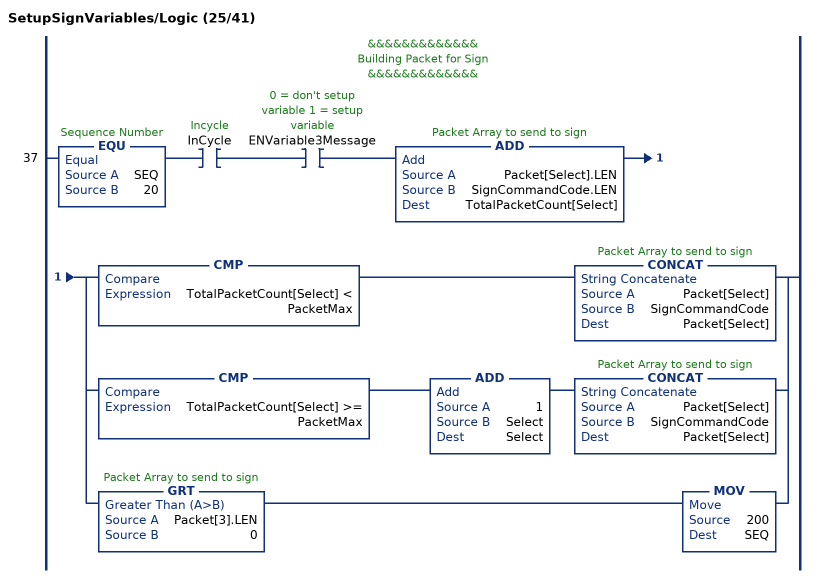
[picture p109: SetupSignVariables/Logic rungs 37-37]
   // &&&&&&&&&&&&&
   // Building Packet for Sign
   // &&&&&&&&&&&&&
   37: EQU(SEQ,20)XIC(InCycle)XIC(ENVariable3Message)ADD(Packet[Select].LEN,SignCommandCode.LEN,TotalPacketCount[Select])[CMP(TotalPacketCount[Select] < PacketMax) CONCAT(Packet[Select],SignCommandCode,Packet[Select]) ,CMP(TotalPacketCount[Select] >= PacketMax) ADD(1,Select,Select) CONCAT(Packet[Select],SignCommandCode,Packet[Select]) ,GRT(Packet[3].LEN,0) MOV(200,SEQ) ];
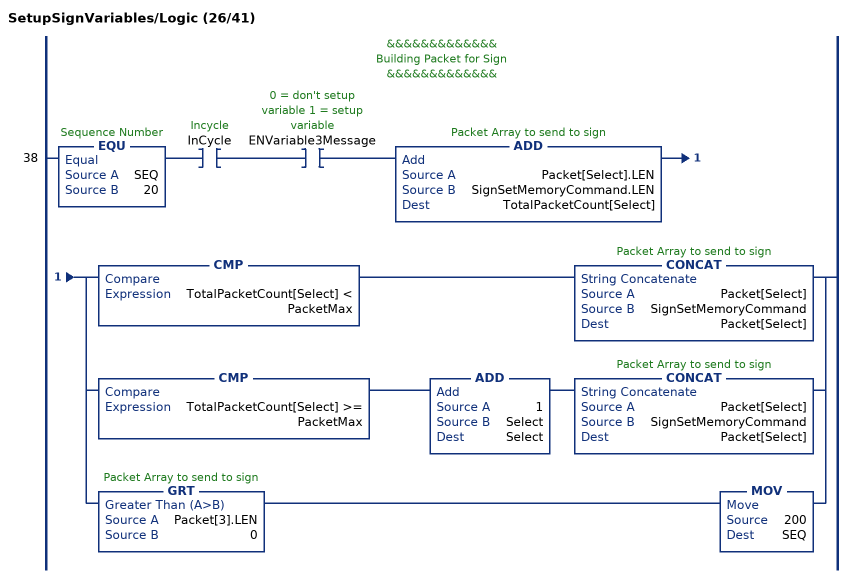
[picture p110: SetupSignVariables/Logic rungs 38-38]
   // &&&&&&&&&&&&&
   // Building Packet for Sign
   // &&&&&&&&&&&&&
   38: EQU(SEQ,20)XIC(InCycle)XIC(ENVariable3Message)ADD(Packet[Select].LEN,SignSetMemoryCommand.LEN,TotalPacketCount[Select])[CMP(TotalPacketCount[Select] < PacketMax) CONCAT(Packet[Select],SignSetMemoryCommand,Packet[Select]) ,CMP(TotalPacketCount[Select] >= PacketMax) ADD(1,Select,Select) CONCAT(Packet[Select],SignSetMemoryCommand,Packet[Select]) ,GRT(Packet[3].LEN,0) MOV(200,SEQ) ];
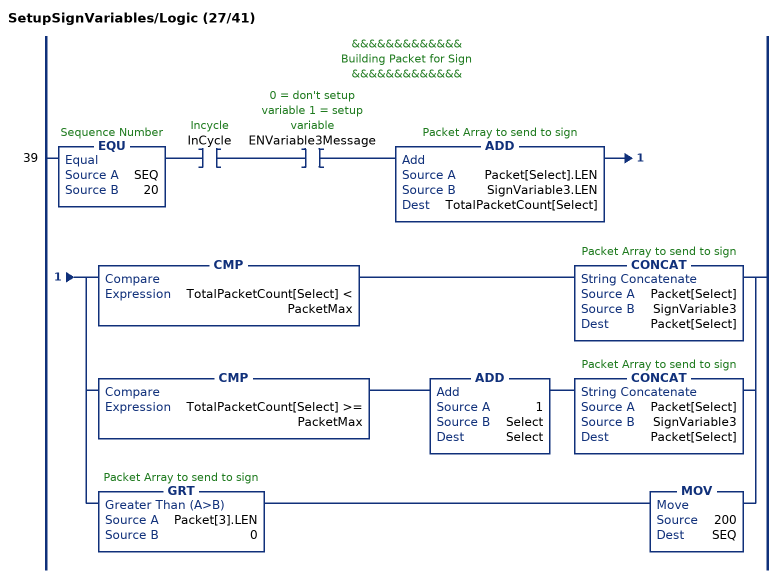
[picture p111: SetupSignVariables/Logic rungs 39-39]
   // &&&&&&&&&&&&&
   // Building Packet for Sign
   // &&&&&&&&&&&&&
   39: EQU(SEQ,20)XIC(InCycle)XIC(ENVariable3Message)ADD(Packet[Select].LEN,SignVariable3.LEN,TotalPacketCount[Select])[CMP(TotalPacketCount[Select] < PacketMax) CONCAT(Packet[Select],SignVariable3,Packet[Select]) ,CMP(TotalPacketCount[Select] >= PacketMax) ADD(1,Select,Select) CONCAT(Packet[Select],SignVariable3,Packet[Select]) ,GRT(Packet[3].LEN,0) MOV(200,SEQ) ];
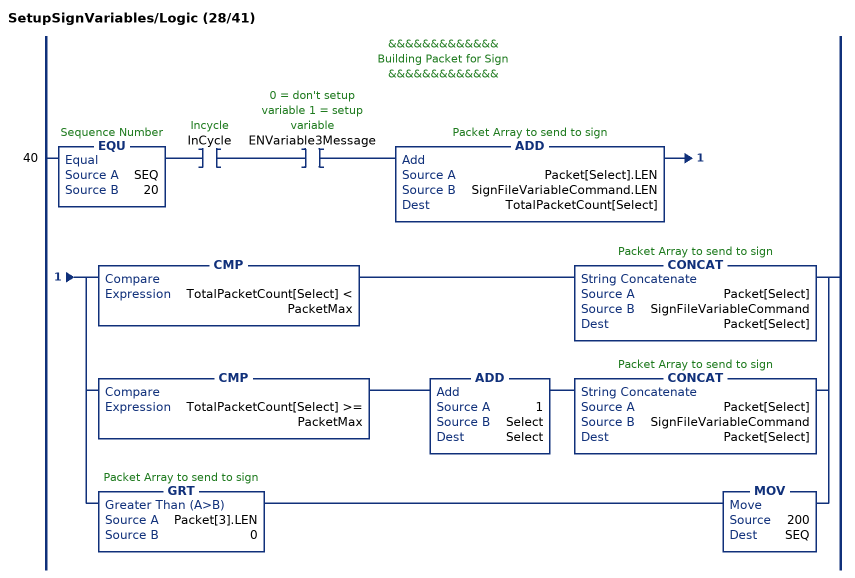
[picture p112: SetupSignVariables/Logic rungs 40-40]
   // &&&&&&&&&&&&&
   // Building Packet for Sign
   // &&&&&&&&&&&&&
   40: EQU(SEQ,20)XIC(InCycle)XIC(ENVariable3Message)ADD(Packet[Select].LEN,SignFileVariableCommand.LEN,TotalPacketCount[Select])[CMP(TotalPacketCount[Select] < PacketMax) CONCAT(Packet[Select],SignFileVariableCommand,Packet[Select]) ,CMP(TotalPacketCount[Select] >= PacketMax) ADD(1,Select,Select) CONCAT(Packet[Select],SignFileVariableCommand,Packet[Select]) ,GRT(Packet[3].LEN,0) MOV(200,SEQ) ];
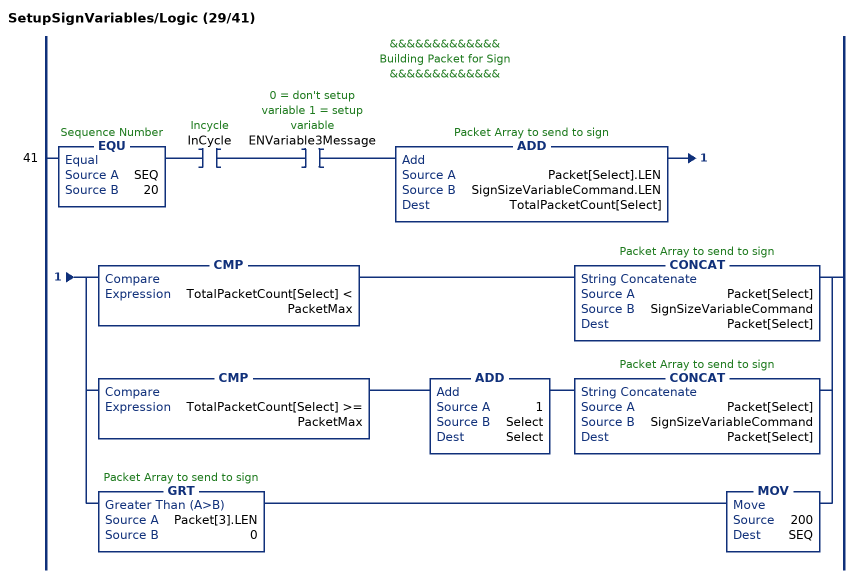
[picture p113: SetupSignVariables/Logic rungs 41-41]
   // &&&&&&&&&&&&&
   // Building Packet for Sign
   // &&&&&&&&&&&&&
   41: EQU(SEQ,20)XIC(InCycle)XIC(ENVariable3Message)ADD(Packet[Select].LEN,SignSizeVariableCommand.LEN,TotalPacketCount[Select])[CMP(TotalPacketCount[Select] < PacketMax) CONCAT(Packet[Select],SignSizeVariableCommand,Packet[Select]) ,CMP(TotalPacketCount[Select] >= PacketMax) ADD(1,Select,Select) CONCAT(Packet[Select],SignSizeVariableCommand,Packet[Select]) ,GRT(Packet[3].LEN,0) MOV(200,SEQ) ];
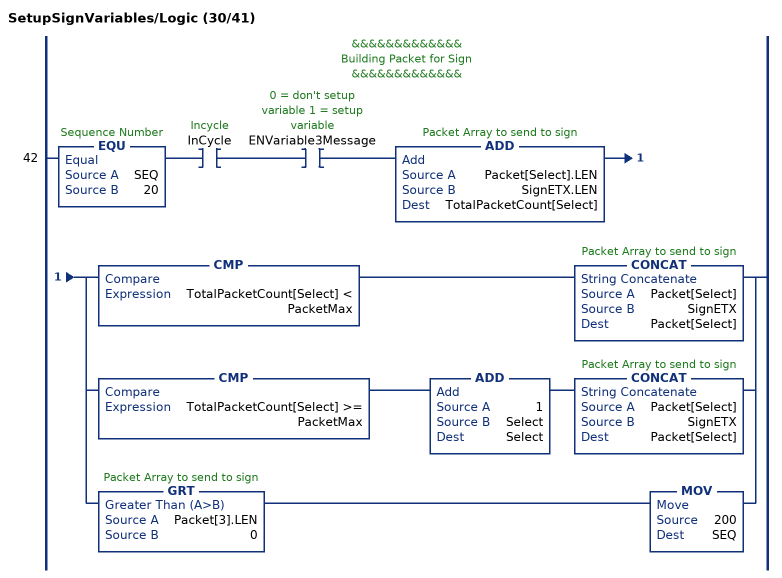
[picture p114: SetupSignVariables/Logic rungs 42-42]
   // &&&&&&&&&&&&&
   // Building Packet for Sign
   // &&&&&&&&&&&&&
   42: EQU(SEQ,20)XIC(InCycle)XIC(ENVariable3Message)ADD(Packet[Select].LEN,SignETX.LEN,TotalPacketCount[Select])[CMP(TotalPacketCount[Select] < PacketMax) CONCAT(Packet[Select],SignETX,Packet[Select]) ,CMP(TotalPacketCount[Select] >= PacketMax) ADD(1,Select,Select) CONCAT(Packet[Select],SignETX,Packet[Select]) ,GRT(Packet[3].LEN,0) MOV(200,SEQ) ];
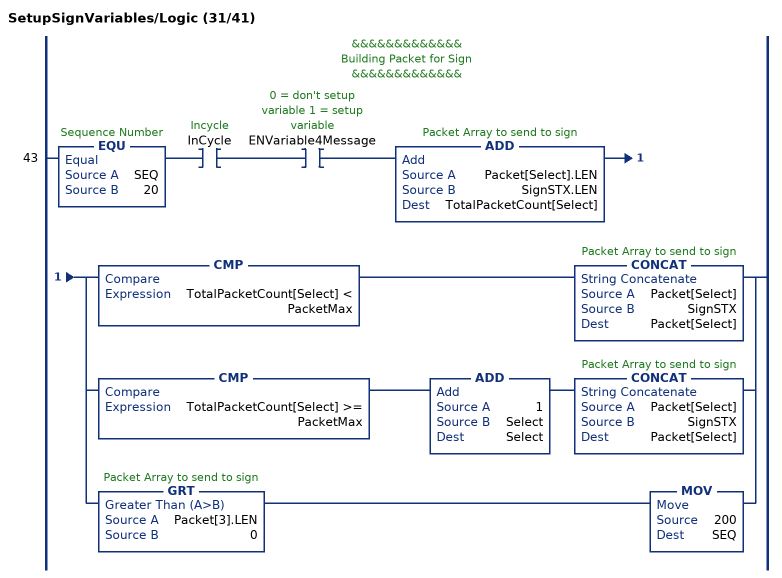
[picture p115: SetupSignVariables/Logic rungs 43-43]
   // &&&&&&&&&&&&&
   // Building Packet for Sign
   // &&&&&&&&&&&&&
   43: EQU(SEQ,20)XIC(InCycle)XIC(ENVariable4Message)ADD(Packet[Select].LEN,SignSTX.LEN,TotalPacketCount[Select])[CMP(TotalPacketCount[Select] < PacketMax) CONCAT(Packet[Select],SignSTX,Packet[Select]) ,CMP(TotalPacketCount[Select] >= PacketMax) ADD(1,Select,Select) CONCAT(Packet[Select],SignSTX,Packet[Select]) ,GRT(Packet[3].LEN,0) MOV(200,SEQ) ];
(* Logix 5000 project; controller Electronic_Displays vendor 1 type 14 code 65 rev 17.4; software revision 17.01; part 6 of 8 *)
(* tags used below, declared in another part *)
   ENVariable4Message : BOOL;   // 0 = don't setup variable 1 = setup variable
   SignVariable4 : STRING;
   SignSetMemoryCommand : STRING;   // DO NOT EDIT = SM
   SignSizeVariableCommand : STRING;   // DO NOT EDIT = 0010 (16 bytes of memory) enough for 16 characters
   SignFileVariableCommand : STRING;   // DO NOT EDIT = V
(* SetupSignVariables, continued *)

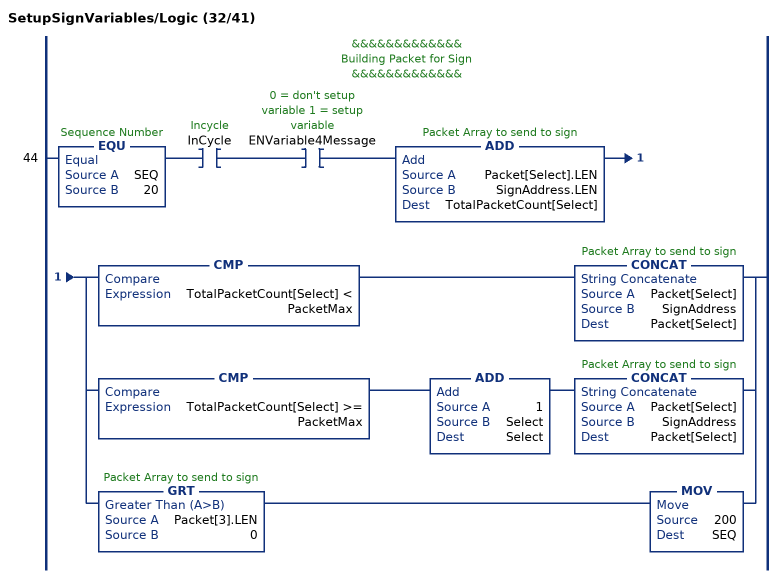
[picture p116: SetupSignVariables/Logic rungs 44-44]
   // &&&&&&&&&&&&&
   // Building Packet for Sign
   // &&&&&&&&&&&&&
   44: EQU(SEQ,20)XIC(InCycle)XIC(ENVariable4Message)ADD(Packet[Select].LEN,SignAddress.LEN,TotalPacketCount[Select])[CMP(TotalPacketCount[Select] < PacketMax) CONCAT(Packet[Select],SignAddress,Packet[Select]) ,CMP(TotalPacketCount[Select] >= PacketMax) ADD(1,Select,Select) CONCAT(Packet[Select],SignAddress,Packet[Select]) ,GRT(Packet[3].LEN,0) MOV(200,SEQ) ];
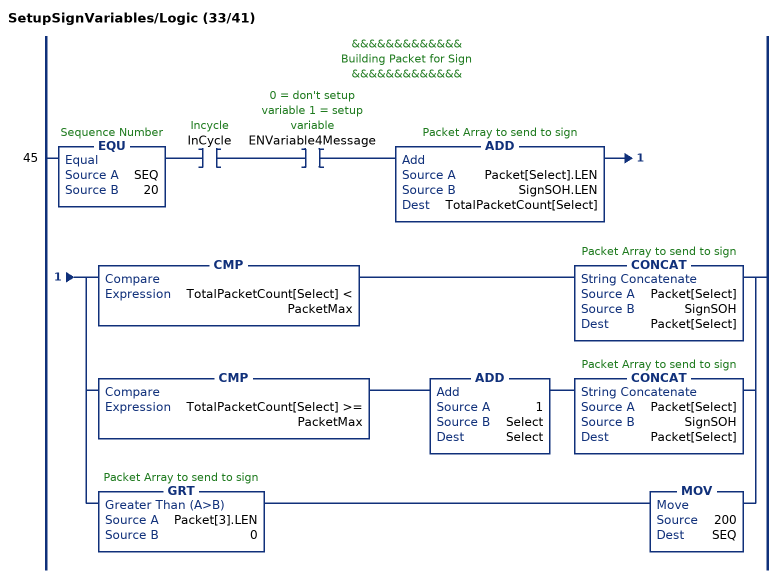
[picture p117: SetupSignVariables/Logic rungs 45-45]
   // &&&&&&&&&&&&&
   // Building Packet for Sign
   // &&&&&&&&&&&&&
   45: EQU(SEQ,20)XIC(InCycle)XIC(ENVariable4Message)ADD(Packet[Select].LEN,SignSOH.LEN,TotalPacketCount[Select])[CMP(TotalPacketCount[Select] < PacketMax) CONCAT(Packet[Select],SignSOH,Packet[Select]) ,CMP(TotalPacketCount[Select] >= PacketMax) ADD(1,Select,Select) CONCAT(Packet[Select],SignSOH,Packet[Select]) ,GRT(Packet[3].LEN,0) MOV(200,SEQ) ];
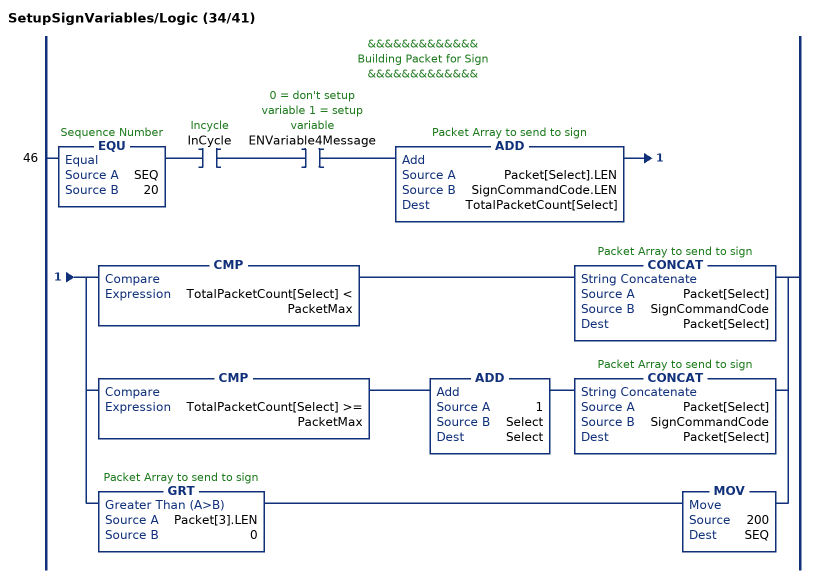
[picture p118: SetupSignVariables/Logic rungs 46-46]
   // &&&&&&&&&&&&&
   // Building Packet for Sign
   // &&&&&&&&&&&&&
   46: EQU(SEQ,20)XIC(InCycle)XIC(ENVariable4Message)ADD(Packet[Select].LEN,SignCommandCode.LEN,TotalPacketCount[Select])[CMP(TotalPacketCount[Select] < PacketMax) CONCAT(Packet[Select],SignCommandCode,Packet[Select]) ,CMP(TotalPacketCount[Select] >= PacketMax) ADD(1,Select,Select) CONCAT(Packet[Select],SignCommandCode,Packet[Select]) ,GRT(Packet[3].LEN,0) MOV(200,SEQ) ];
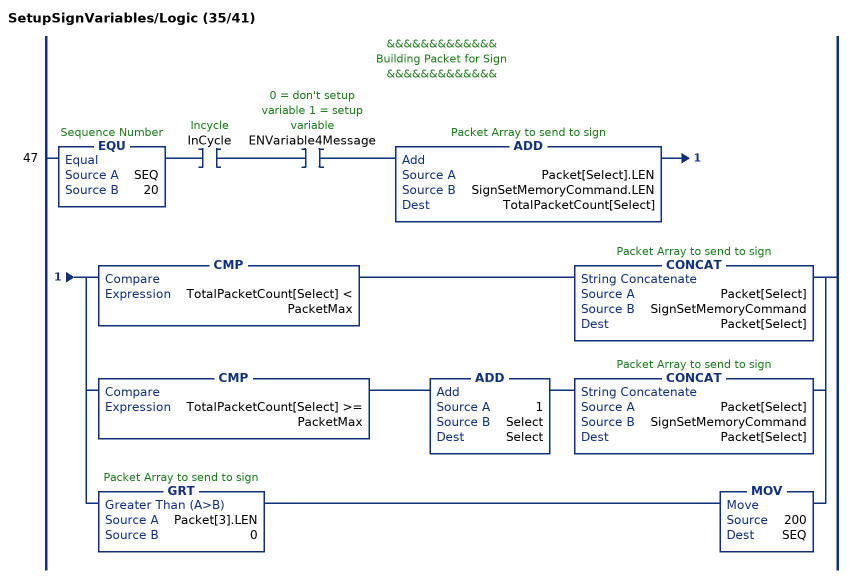
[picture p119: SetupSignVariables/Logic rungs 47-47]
   // &&&&&&&&&&&&&
   // Building Packet for Sign
   // &&&&&&&&&&&&&
   47: EQU(SEQ,20)XIC(InCycle)XIC(ENVariable4Message)ADD(Packet[Select].LEN,SignSetMemoryCommand.LEN,TotalPacketCount[Select])[CMP(TotalPacketCount[Select] < PacketMax) CONCAT(Packet[Select],SignSetMemoryCommand,Packet[Select]) ,CMP(TotalPacketCount[Select] >= PacketMax) ADD(1,Select,Select) CONCAT(Packet[Select],SignSetMemoryCommand,Packet[Select]) ,GRT(Packet[3].LEN,0) MOV(200,SEQ) ];
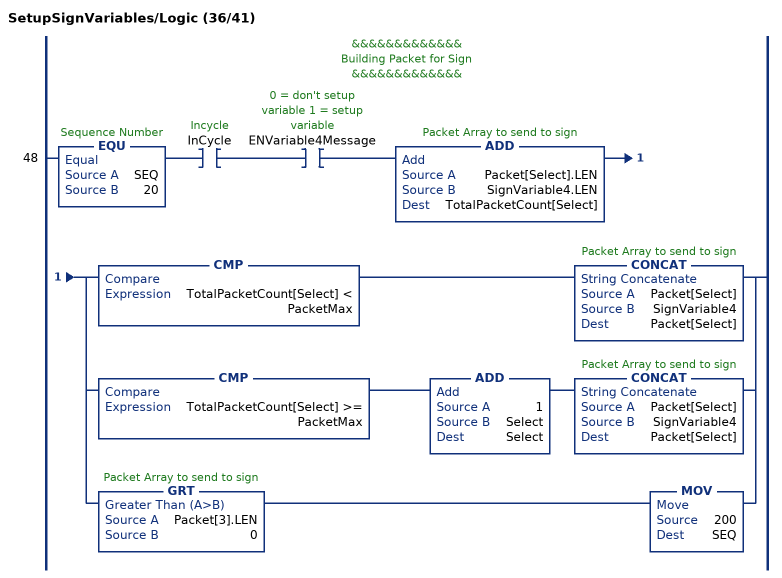
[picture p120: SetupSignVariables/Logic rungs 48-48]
   // &&&&&&&&&&&&&
   // Building Packet for Sign
   // &&&&&&&&&&&&&
   48: EQU(SEQ,20)XIC(InCycle)XIC(ENVariable4Message)ADD(Packet[Select].LEN,SignVariable4.LEN,TotalPacketCount[Select])[CMP(TotalPacketCount[Select] < PacketMax) CONCAT(Packet[Select],SignVariable4,Packet[Select]) ,CMP(TotalPacketCount[Select] >= PacketMax) ADD(1,Select,Select) CONCAT(Packet[Select],SignVariable4,Packet[Select]) ,GRT(Packet[3].LEN,0) MOV(200,SEQ) ];
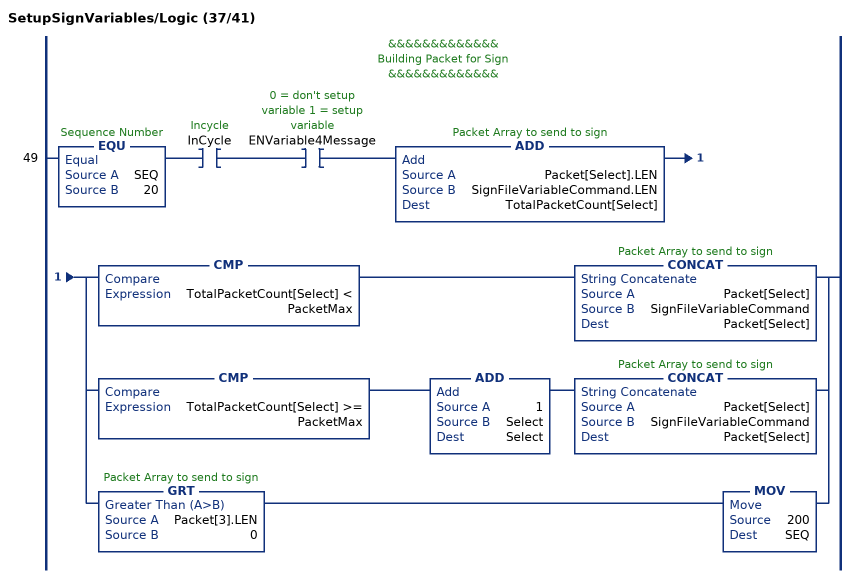
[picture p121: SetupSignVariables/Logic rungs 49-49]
   // &&&&&&&&&&&&&
   // Building Packet for Sign
   // &&&&&&&&&&&&&
   49: EQU(SEQ,20)XIC(InCycle)XIC(ENVariable4Message)ADD(Packet[Select].LEN,SignFileVariableCommand.LEN,TotalPacketCount[Select])[CMP(TotalPacketCount[Select] < PacketMax) CONCAT(Packet[Select],SignFileVariableCommand,Packet[Select]) ,CMP(TotalPacketCount[Select] >= PacketMax) ADD(1,Select,Select) CONCAT(Packet[Select],SignFileVariableCommand,Packet[Select]) ,GRT(Packet[3].LEN,0) MOV(200,SEQ) ];
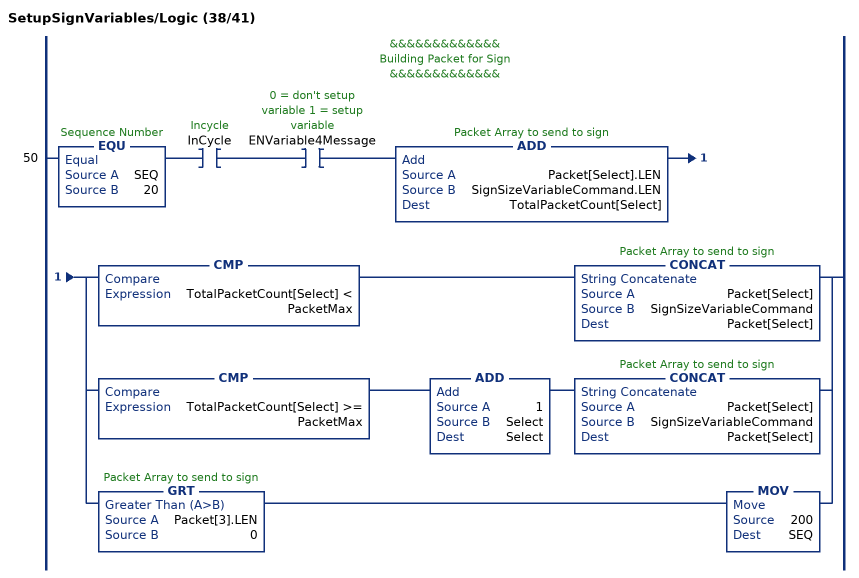
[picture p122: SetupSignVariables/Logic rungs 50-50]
   // &&&&&&&&&&&&&
   // Building Packet for Sign
   // &&&&&&&&&&&&&
   50: EQU(SEQ,20)XIC(InCycle)XIC(ENVariable4Message)ADD(Packet[Select].LEN,SignSizeVariableCommand.LEN,TotalPacketCount[Select])[CMP(TotalPacketCount[Select] < PacketMax) CONCAT(Packet[Select],SignSizeVariableCommand,Packet[Select]) ,CMP(TotalPacketCount[Select] >= PacketMax) ADD(1,Select,Select) CONCAT(Packet[Select],SignSizeVariableCommand,Packet[Select]) ,GRT(Packet[3].LEN,0) MOV(200,SEQ) ];
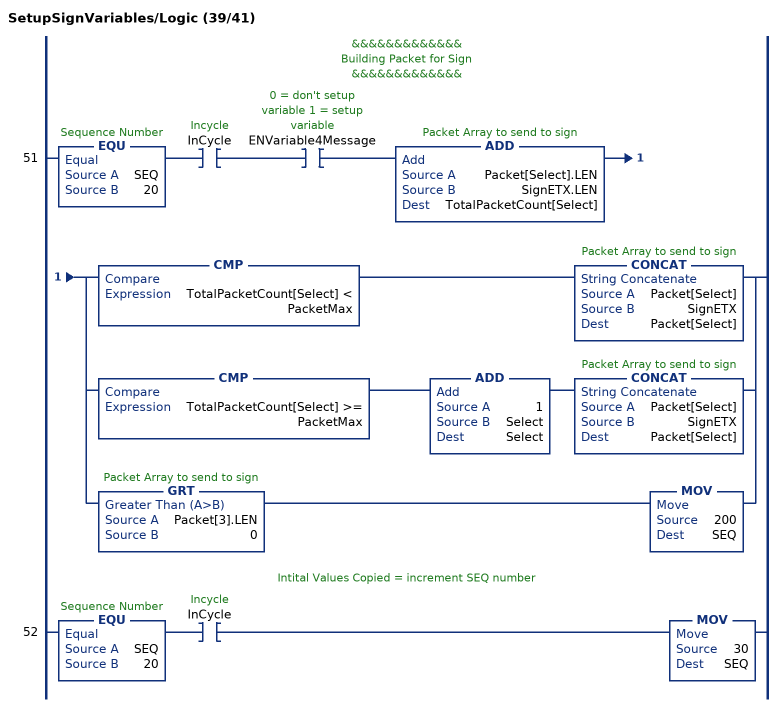
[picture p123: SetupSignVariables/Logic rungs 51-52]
   // &&&&&&&&&&&&&
   // Building Packet for Sign
   // &&&&&&&&&&&&&
   51: EQU(SEQ,20)XIC(InCycle)XIC(ENVariable4Message)ADD(Packet[Select].LEN,SignETX.LEN,TotalPacketCount[Select])[CMP(TotalPacketCount[Select] < PacketMax) CONCAT(Packet[Select],SignETX,Packet[Select]) ,CMP(TotalPacketCount[Select] >= PacketMax) ADD(1,Select,Select) CONCAT(Packet[Select],SignETX,Packet[Select]) ,GRT(Packet[3].LEN,0) MOV(200,SEQ) ];
   // Intital Values Copied = increment SEQ number
   52: EQU(SEQ,20)XIC(InCycle)MOV(30,SEQ);
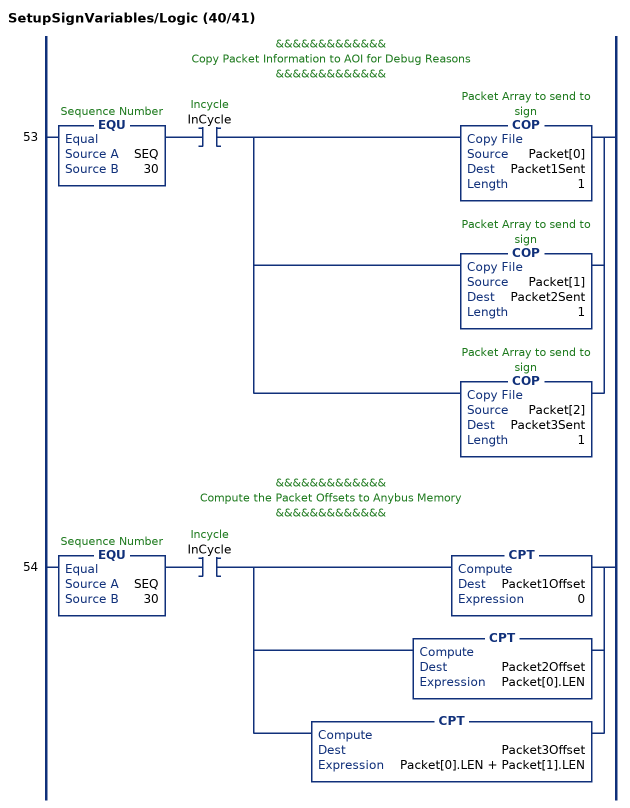
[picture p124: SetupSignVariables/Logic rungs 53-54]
   // &&&&&&&&&&&&&
   // Copy Packet Information to AOI for Debug Reasons
   // &&&&&&&&&&&&&
   53: EQU(SEQ,30)XIC(InCycle)[COP(Packet[0],Packet1Sent,1) ,COP(Packet[1],Packet2Sent,1) ,COP(Packet[2],Packet3Sent,1) ];
   // &&&&&&&&&&&&&
   // Compute the Packet Offsets to Anybus Memory
   // &&&&&&&&&&&&&
   54: EQU(SEQ,30)XIC(InCycle)[CPT(Packet1Offset,0) ,CPT(Packet2Offset,Packet[0].LEN) ,CPT(Packet3Offset,Packet[0].LEN + Packet[1].LEN) ];
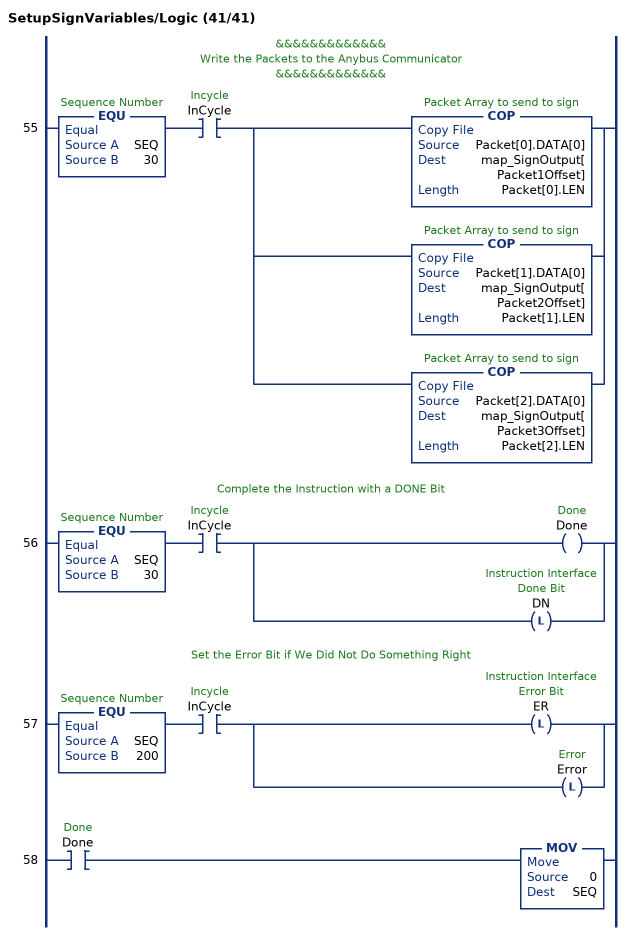
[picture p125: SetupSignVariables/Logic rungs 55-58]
   // &&&&&&&&&&&&&
   // Write the Packets to the Anybus Communicator
   // &&&&&&&&&&&&&
   55: EQU(SEQ,30)XIC(InCycle)[COP(Packet[0].DATA[0],map_SignOutput[Packet1Offset],Packet[0].LEN) ,COP(Packet[1].DATA[0],map_SignOutput[Packet2Offset],Packet[1].LEN) ,COP(Packet[2].DATA[0],map_SignOutput[Packet3Offset],Packet[2].LEN) ];
   // Complete the Instruction with a DONE Bit
   56: EQU(SEQ,30)XIC(InCycle)[OTE(Done) ,OTL(DN) ];
   // Set the Error Bit if We Did Not Do Something Right
   57: EQU(SEQ,200)XIC(InCycle)[OTL(ER) ,OTL(Error) ];
   58: XIC(Done)MOV(0,SEQ);
END_ROUTINE
END_ADD_ON_INSTRUCTION

ADD_ON_INSTRUCTION UpdateSignVariables   (* revision 1.0, ExecuteEnableInFalse *)
// Update
// Four Variables
// to LED Sign
// Revision note:
// Original Release
// 11-01-2012
// c.elston
VAR_IN_OUT
   Address : STRING; {required}   // "00" = all signs "01" = address 01 "02" = address 02 etc...(see protocol)
   FileLabel : STRING; {required}   // "A" = default etc...(see protocol)
END_VAR
VAR_INPUT
   ENVariable1Update : BOOL; {visible}   // 0 = don't update this variable 1 = update this variable
END_VAR
VAR_IN_OUT
   Variable1Name : STRING; {required}   // Name of variable Default is = U
   Variable1Value : STRING; {required}   // Actual variable1 value, this need to be text format here.
END_VAR
VAR_INPUT
   ENVariable2Update : BOOL; {visible}   // 0 = don't update this variable 1 = update this variable
END_VAR
VAR_IN_OUT
   Variable2Name : STRING; {required}   // Name of variable Default is = V
   Variable2Value : STRING; {required}   // Actual variable2 value, this need to be text format here.
END_VAR
VAR_INPUT
   ENVariable3Update : BOOL; {visible}   // 0 = don't update this variable 1 = update this variable
END_VAR
VAR_IN_OUT
   Variable3Name : STRING; {required}   // Name of variable Default is = W
   Variable3Value : STRING; {required}   // Actual variable3 value, this need to be text format here.
END_VAR
VAR_INPUT
   ENVariable4Update : BOOL; {visible}   // 0 = don't update this variable 1 = update this variable
END_VAR
VAR_IN_OUT
   Variable4Name : STRING; {required}   // Name of variable Default is = X
   Variable4Value : STRING; {required}   // Actual variable4 value, this need to be text format here.
END_VAR
VAR_OUTPUT
   EN : BOOL; {visible}   // Instruction Interface Enable Bit
   DN : BOOL; {visible}   // Instruction Interface Done Bit
   ER : BOOL; {visible}   // Instruction Interface Error Bit
   IP : BOOL; {visible}   // Instruction Interface InProcess Bit
END_VAR
VAR_IN_OUT
   map_SignInput : SINT[32]; {required}   // Ethernet/IP LEDSIGN.I Data I/O Mapping
   map_SignOutput : SINT[496]; {required}   // Ethernet/IP LEDSIGN.O Data I/O Mapping
   Packet1Sent : STRING; {required}   // The actual packet sent to the sign (Packet1)
   Packet2Sent : STRING; {required}   // The actual packet sent to the sign (Packet2)
   Packet3Sent : STRING; {required}   // The actual packet sent to the sign (Packet3)
END_VAR
VAR
   SEQ : DINT;   // Sequence Number
   OktoCycle : BOOL;   // Ok to Cycle
   InCycle : BOOL;   // Incycle
   Error : BOOL;   // Error
   Enabled : BOOL;   // Enable ON Bit
   Done : BOOL;   // Done
   Disabled : BOOL;   // Disabled OFF Bit
   SignETX : STRING := '^C';   // DO NOT EDIT = ^C
   SignFileLabel : STRING;
   SignSOH : STRING := '^A';   // DO NOT EDIT = ^A
   SignAddress : STRING;
   SignSTX : STRING := '^B';   // DO NOT EDIT = ^B
   SignNULL : STRING;
   SignVariable4Name : STRING;
   SignVariable3Name : STRING;
   SignVariable2Name : STRING;
   SignVariable1Name : STRING;
   SignCommandCode : STRING := 'B';   // DO NOT EDIT = B
   SignVariable4Value : STRING;
   SignVariable3Value : STRING;
   SignVariable2Value : STRING;
   SignVariable1Value : STRING;
   TotalPacketCount : DINT[7];   // Total Character Count
   Select : DINT;   // Packet Array Select
   PacketMax : DINT := 82;   // Max Packet Count
   PacketCount : DINT[7];
   Packet6Offset : DINT;
   Packet5Offset : DINT;
   Packet4Offset : DINT;
   Packet3Offset : DINT;
   Packet2Offset : DINT;
   Packet1Offset : DINT;
   Packet : STRING[7];   // Packet Array to send to sign
END_VAR

ROUTINE EnableInFalse   (* ladder *)
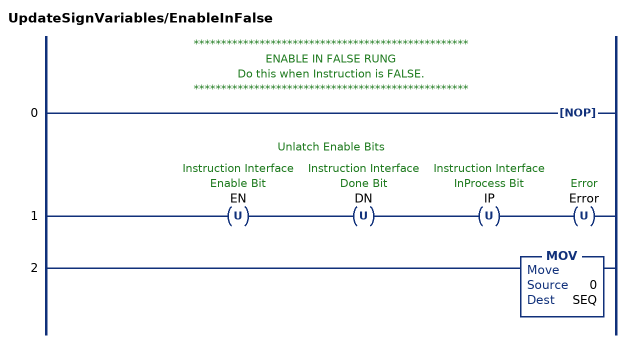
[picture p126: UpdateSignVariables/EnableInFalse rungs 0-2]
   // **************************************************
   // ENABLE IN FALSE RUNG
   // Do this when Instruction is FALSE.
   // **************************************************
   0: NOP();
   // Unlatch Enable Bits
   1: OTU(EN)OTU(DN)OTU(IP)OTU(Error);
   2: MOV(0,SEQ);
END_ROUTINE

ROUTINE Logic   (* ladder *)
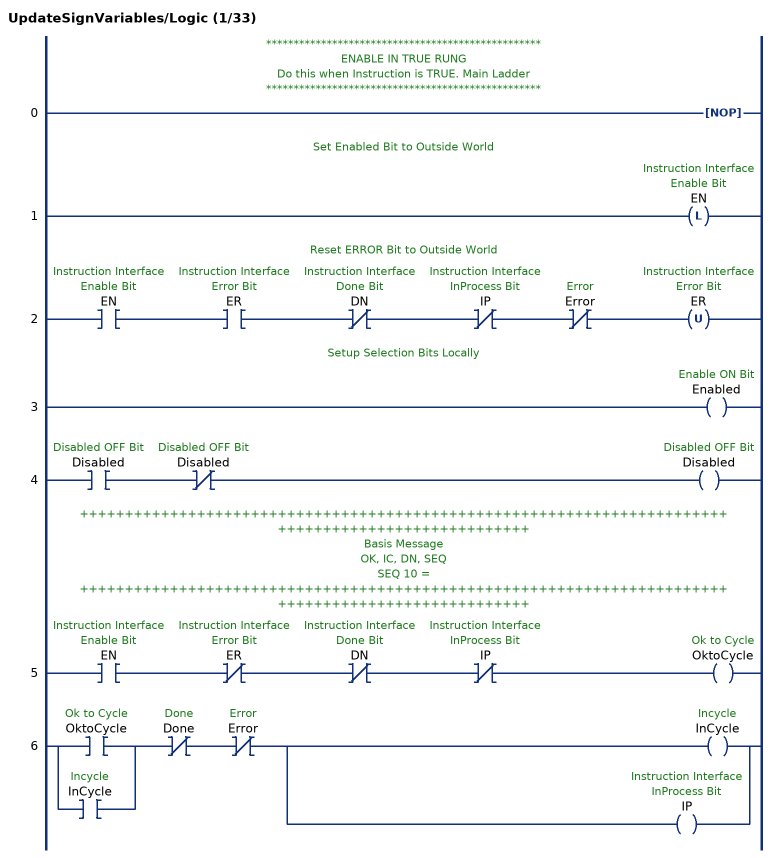
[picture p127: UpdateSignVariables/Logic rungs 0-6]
   // **************************************************
   // ENABLE IN TRUE RUNG
   // Do this when Instruction is TRUE. Main Ladder
   // **************************************************
   0: NOP();
   // Set Enabled Bit to Outside World
   1: OTL(EN);
   // Reset ERROR Bit to Outside World
   2: XIC(EN)XIC(ER)XIO(DN)XIO(IP)XIO(Error)OTU(ER);
   // Setup Selection Bits Locally
   3: OTE(Enabled);
   4: XIC(Disabled)XIO(Disabled)OTE(Disabled);
   // ++++++++++++++++++++++++++++++++++++++++++++++++++++++++++++++++++++++++++++++++++++++++++++++++++++
   // Basis Message
   // OK, IC, DN, SEQ
   // SEQ 10 =
   // ++++++++++++++++++++++++++++++++++++++++++++++++++++++++++++++++++++++++++++++++++++++++++++++++++++
   5: XIC(EN)XIO(ER)XIO(DN)XIO(IP)OTE(OktoCycle);
   6: [XIC(OktoCycle) ,XIC(InCycle) ]XIO(Done)XIO(Error)[OTE(InCycle) ,OTE(IP) ];
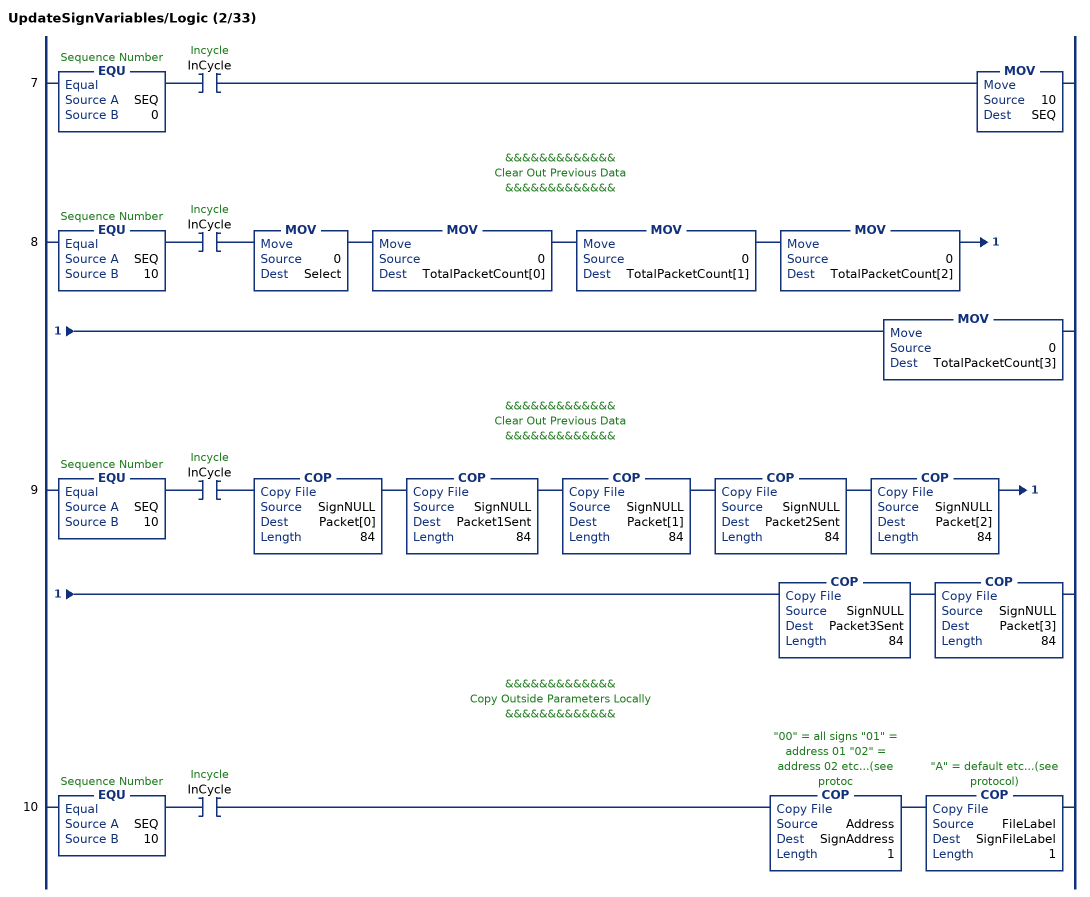
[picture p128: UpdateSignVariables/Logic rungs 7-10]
   7: EQU(SEQ,0)XIC(InCycle)MOV(10,SEQ);
   // &&&&&&&&&&&&&
   // Clear Out Previous Data
   // &&&&&&&&&&&&&
   8: EQU(SEQ,10)XIC(InCycle)MOV(0,Select)MOV(0,TotalPacketCount[0])MOV(0,TotalPacketCount[1])MOV(0,TotalPacketCount[2])MOV(0,TotalPacketCount[3]);
   // &&&&&&&&&&&&&
   // Clear Out Previous Data
   // &&&&&&&&&&&&&
   9: EQU(SEQ,10)XIC(InCycle)COP(SignNULL,Packet[0],84)COP(SignNULL,Packet1Sent,84)COP(SignNULL,Packet[1],84)COP(SignNULL,Packet2Sent,84)COP(SignNULL,Packet[2],84)COP(SignNULL,Packet3Sent,84)COP(SignNULL,Packet[3],84);
   // &&&&&&&&&&&&&
   // Copy Outside Parameters Locally
   // &&&&&&&&&&&&&
   10: EQU(SEQ,10)XIC(InCycle)COP(Address,SignAddress,1)COP(FileLabel,SignFileLabel,1);
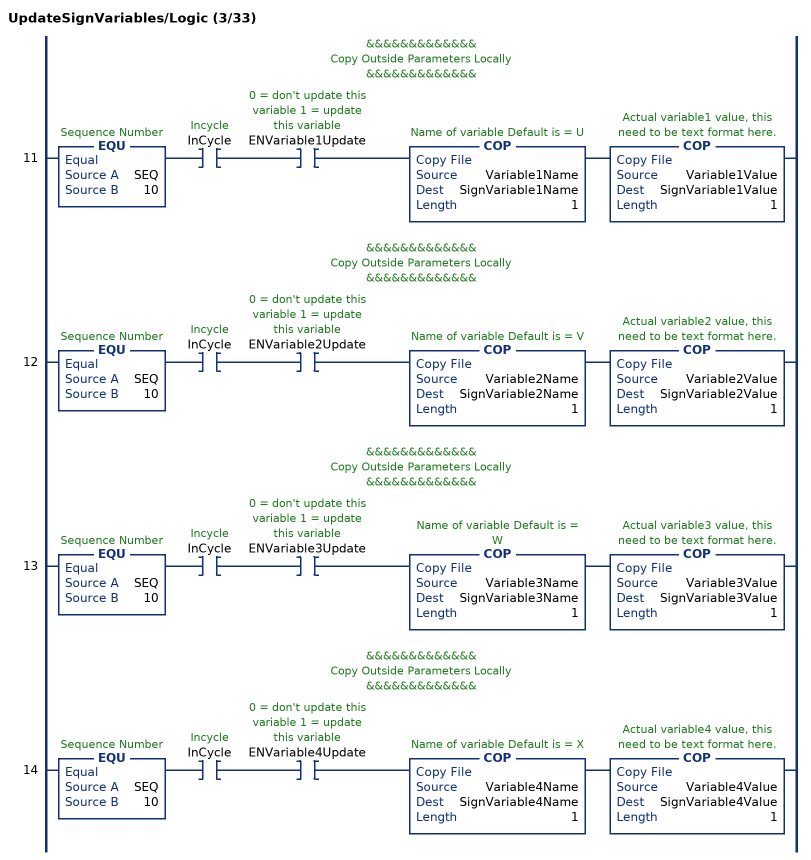
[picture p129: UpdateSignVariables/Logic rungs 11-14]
   // &&&&&&&&&&&&&
   // Copy Outside Parameters Locally
   // &&&&&&&&&&&&&
   11: EQU(SEQ,10)XIC(InCycle)XIC(ENVariable1Update)COP(Variable1Name,SignVariable1Name,1)COP(Variable1Value,SignVariable1Value,1);
   // &&&&&&&&&&&&&
   // Copy Outside Parameters Locally
   // &&&&&&&&&&&&&
   12: EQU(SEQ,10)XIC(InCycle)XIC(ENVariable2Update)COP(Variable2Name,SignVariable2Name,1)COP(Variable2Value,SignVariable2Value,1);
   // &&&&&&&&&&&&&
   // Copy Outside Parameters Locally
   // &&&&&&&&&&&&&
   13: EQU(SEQ,10)XIC(InCycle)XIC(ENVariable3Update)COP(Variable3Name,SignVariable3Name,1)COP(Variable3Value,SignVariable3Value,1);
   // &&&&&&&&&&&&&
   // Copy Outside Parameters Locally
   // &&&&&&&&&&&&&
   14: EQU(SEQ,10)XIC(InCycle)XIC(ENVariable4Update)COP(Variable4Name,SignVariable4Name,1)COP(Variable4Value,SignVariable4Value,1);
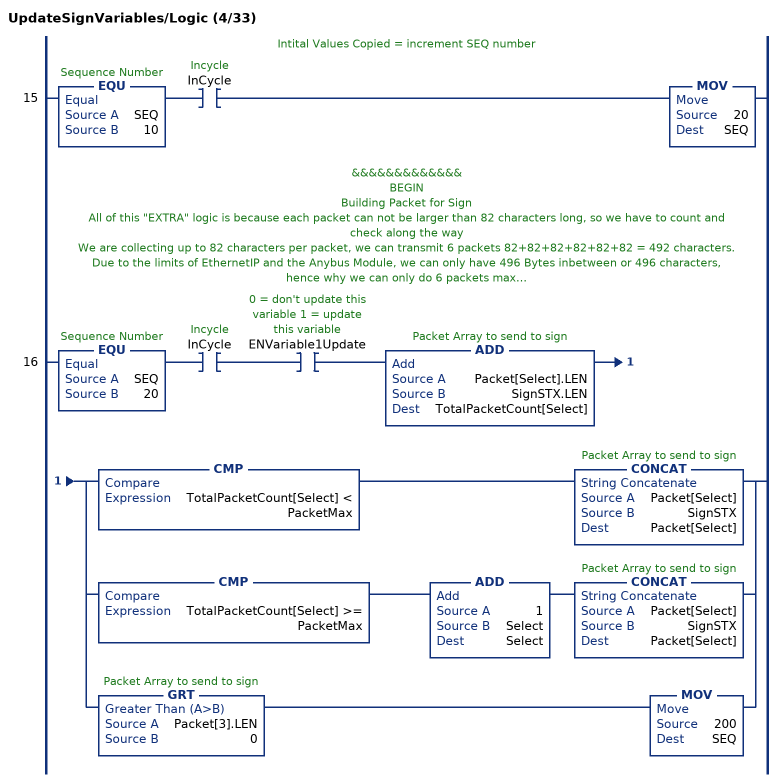
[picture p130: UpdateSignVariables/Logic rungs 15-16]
   // Intital Values Copied = increment SEQ number
   15: EQU(SEQ,10)XIC(InCycle)MOV(20,SEQ);
   // &&&&&&&&&&&&&
   // BEGIN
   // Building Packet for Sign
   // All of this "EXTRA" logic is because each packet can not be larger than 82 characters long, so we have to count and check along the way
   // We are collecting up to 82 characters per packet, we can transmit 6 packets 82+82+82+82+82+82 = 492 characters.
   // Due to the limits of EthernetIP and the Anybus Module, we can only have 496 Bytes inbetween or 496 characters, hence why we can only do 6 packets max.
   // Once we exceed this, we will fault and ERROR trap any windy typing people.
   // In this instruction below, it's so small, we are only using 3 packets max.
   // &&&&&&&&&&&&&
   16: EQU(SEQ,20)XIC(InCycle)XIC(ENVariable1Update)ADD(Packet[Select].LEN,SignSTX.LEN,TotalPacketCount[Select])[CMP(TotalPacketCount[Select] < PacketMax) CONCAT(Packet[Select],SignSTX,Packet[Select]) ,CMP(TotalPacketCount[Select] >= PacketMax) ADD(1,Select,Select) CONCAT(Packet[Select],SignSTX,Packet[Select]) ,GRT(Packet[3].LEN,0) MOV(200,SEQ) ];
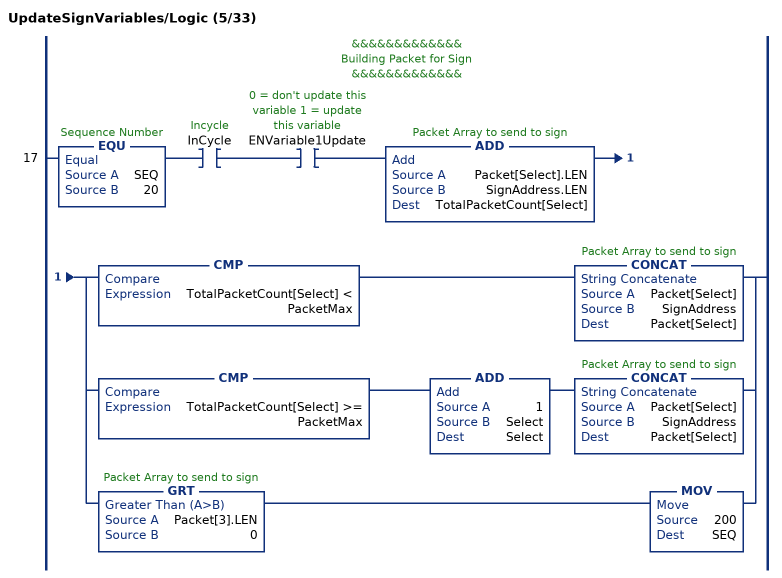
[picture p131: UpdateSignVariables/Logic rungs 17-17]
   // &&&&&&&&&&&&&
   // Building Packet for Sign
   // &&&&&&&&&&&&&
   17: EQU(SEQ,20)XIC(InCycle)XIC(ENVariable1Update)ADD(Packet[Select].LEN,SignAddress.LEN,TotalPacketCount[Select])[CMP(TotalPacketCount[Select] < PacketMax) CONCAT(Packet[Select],SignAddress,Packet[Select]) ,CMP(TotalPacketCount[Select] >= PacketMax) ADD(1,Select,Select) CONCAT(Packet[Select],SignAddress,Packet[Select]) ,GRT(Packet[3].LEN,0) MOV(200,SEQ) ];
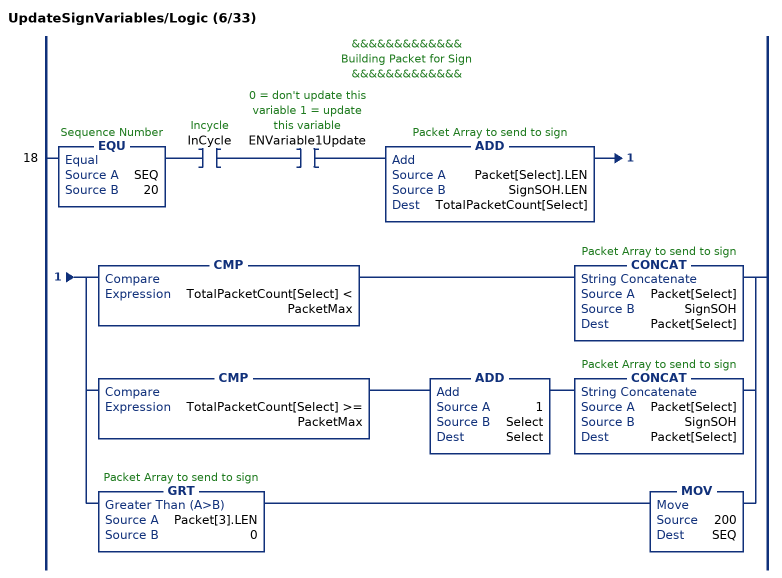
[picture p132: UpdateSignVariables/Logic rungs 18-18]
   // &&&&&&&&&&&&&
   // Building Packet for Sign
   // &&&&&&&&&&&&&
   18: EQU(SEQ,20)XIC(InCycle)XIC(ENVariable1Update)ADD(Packet[Select].LEN,SignSOH.LEN,TotalPacketCount[Select])[CMP(TotalPacketCount[Select] < PacketMax) CONCAT(Packet[Select],SignSOH,Packet[Select]) ,CMP(TotalPacketCount[Select] >= PacketMax) ADD(1,Select,Select) CONCAT(Packet[Select],SignSOH,Packet[Select]) ,GRT(Packet[3].LEN,0) MOV(200,SEQ) ];
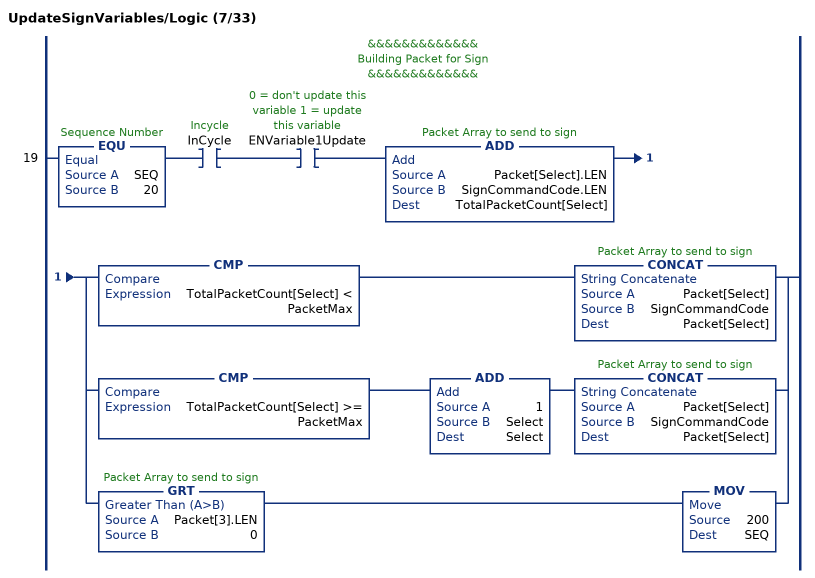
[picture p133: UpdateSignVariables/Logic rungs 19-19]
   // &&&&&&&&&&&&&
   // Building Packet for Sign
   // &&&&&&&&&&&&&
   19: EQU(SEQ,20)XIC(InCycle)XIC(ENVariable1Update)ADD(Packet[Select].LEN,SignCommandCode.LEN,TotalPacketCount[Select])[CMP(TotalPacketCount[Select] < PacketMax) CONCAT(Packet[Select],SignCommandCode,Packet[Select]) ,CMP(TotalPacketCount[Select] >= PacketMax) ADD(1,Select,Select) CONCAT(Packet[Select],SignCommandCode,Packet[Select]) ,GRT(Packet[3].LEN,0) MOV(200,SEQ) ];
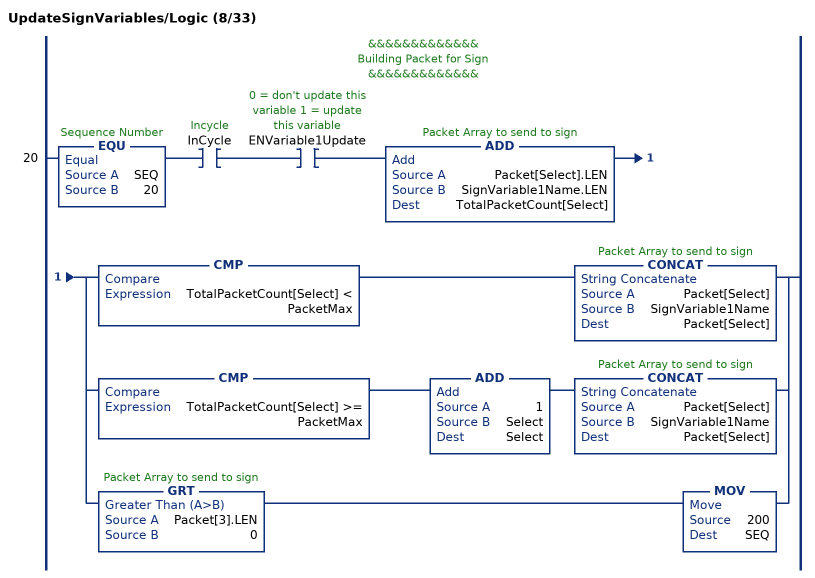
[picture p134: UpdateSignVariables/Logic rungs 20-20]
   // &&&&&&&&&&&&&
   // Building Packet for Sign
   // &&&&&&&&&&&&&
   20: EQU(SEQ,20)XIC(InCycle)XIC(ENVariable1Update)ADD(Packet[Select].LEN,SignVariable1Name.LEN,TotalPacketCount[Select])[CMP(TotalPacketCount[Select] < PacketMax) CONCAT(Packet[Select],SignVariable1Name,Packet[Select]) ,CMP(TotalPacketCount[Select] >= PacketMax) ADD(1,Select,Select) CONCAT(Packet[Select],SignVariable1Name,Packet[Select]) ,GRT(Packet[3].LEN,0) MOV(200,SEQ) ];
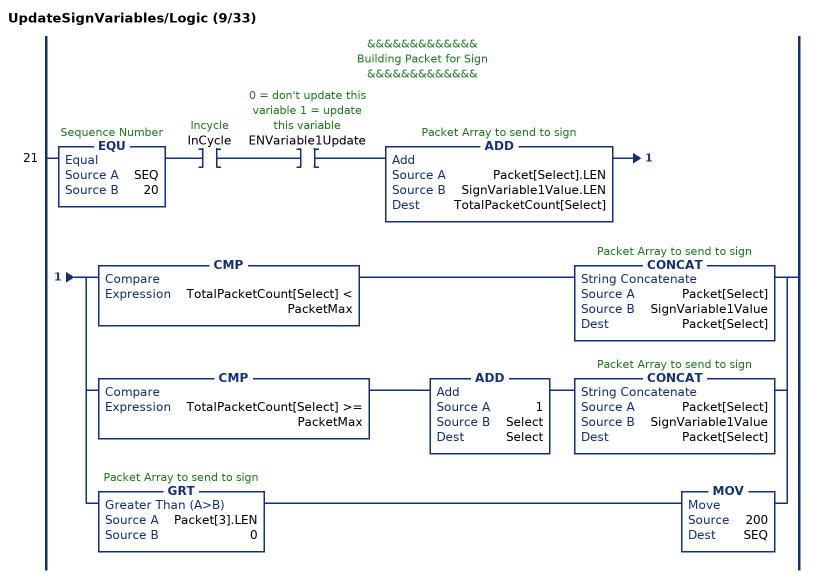
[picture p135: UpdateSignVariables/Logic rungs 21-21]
   // &&&&&&&&&&&&&
   // Building Packet for Sign
   // &&&&&&&&&&&&&
   21: EQU(SEQ,20)XIC(InCycle)XIC(ENVariable1Update)ADD(Packet[Select].LEN,SignVariable1Value.LEN,TotalPacketCount[Select])[CMP(TotalPacketCount[Select] < PacketMax) CONCAT(Packet[Select],SignVariable1Value,Packet[Select]) ,CMP(TotalPacketCount[Select] >= PacketMax) ADD(1,Select,Select) CONCAT(Packet[Select],SignVariable1Value,Packet[Select]) ,GRT(Packet[3].LEN,0) MOV(200,SEQ) ];
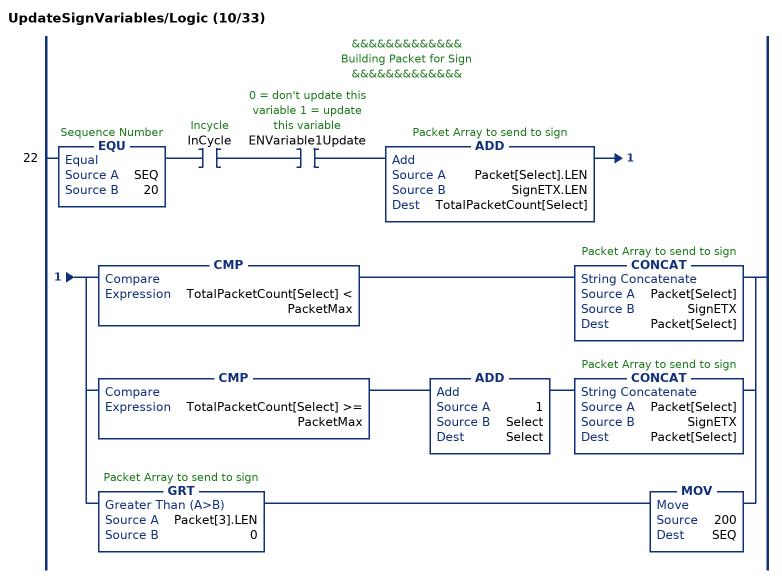
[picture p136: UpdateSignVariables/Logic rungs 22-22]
   // &&&&&&&&&&&&&
   // Building Packet for Sign
   // &&&&&&&&&&&&&
   22: EQU(SEQ,20)XIC(InCycle)XIC(ENVariable1Update)ADD(Packet[Select].LEN,SignETX.LEN,TotalPacketCount[Select])[CMP(TotalPacketCount[Select] < PacketMax) CONCAT(Packet[Select],SignETX,Packet[Select]) ,CMP(TotalPacketCount[Select] >= PacketMax) ADD(1,Select,Select) CONCAT(Packet[Select],SignETX,Packet[Select]) ,GRT(Packet[3].LEN,0) MOV(200,SEQ) ];
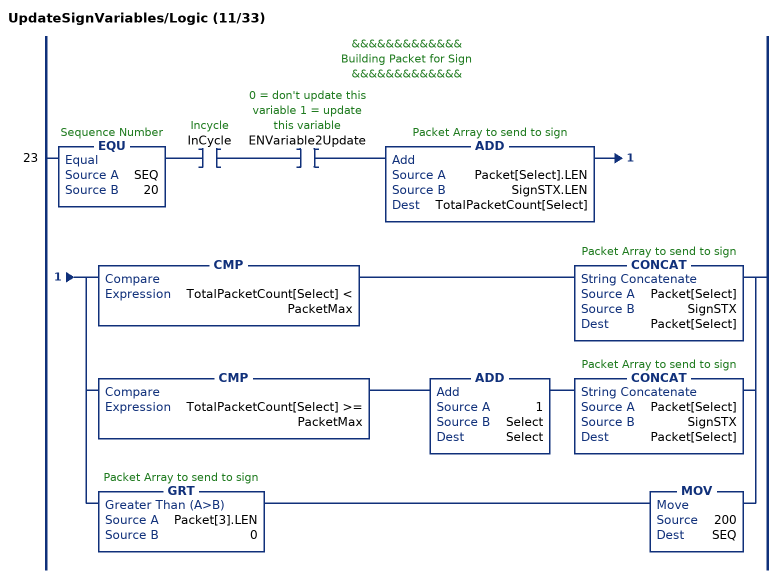
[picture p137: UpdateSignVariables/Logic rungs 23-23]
   // &&&&&&&&&&&&&
   // Building Packet for Sign
   // &&&&&&&&&&&&&
   23: EQU(SEQ,20)XIC(InCycle)XIC(ENVariable2Update)ADD(Packet[Select].LEN,SignSTX.LEN,TotalPacketCount[Select])[CMP(TotalPacketCount[Select] < PacketMax) CONCAT(Packet[Select],SignSTX,Packet[Select]) ,CMP(TotalPacketCount[Select] >= PacketMax) ADD(1,Select,Select) CONCAT(Packet[Select],SignSTX,Packet[Select]) ,GRT(Packet[3].LEN,0) MOV(200,SEQ) ];
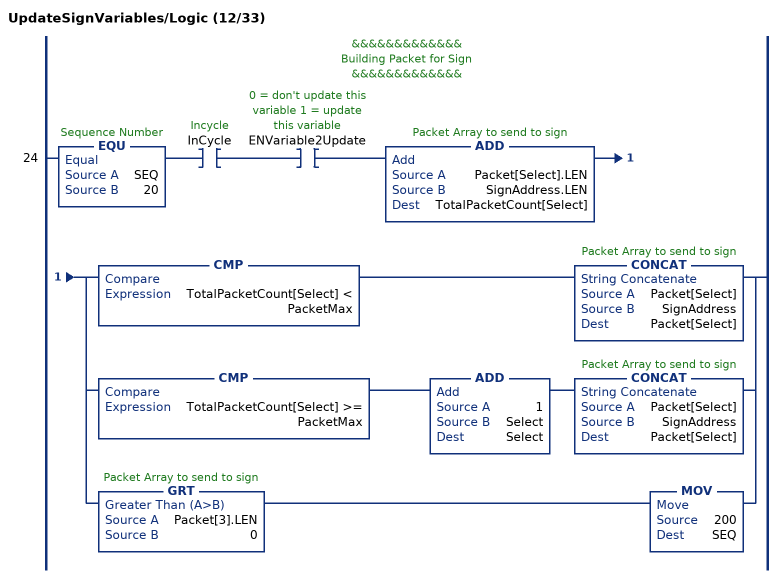
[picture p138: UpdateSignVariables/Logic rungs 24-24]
   // &&&&&&&&&&&&&
   // Building Packet for Sign
   // &&&&&&&&&&&&&
   24: EQU(SEQ,20)XIC(InCycle)XIC(ENVariable2Update)ADD(Packet[Select].LEN,SignAddress.LEN,TotalPacketCount[Select])[CMP(TotalPacketCount[Select] < PacketMax) CONCAT(Packet[Select],SignAddress,Packet[Select]) ,CMP(TotalPacketCount[Select] >= PacketMax) ADD(1,Select,Select) CONCAT(Packet[Select],SignAddress,Packet[Select]) ,GRT(Packet[3].LEN,0) MOV(200,SEQ) ];
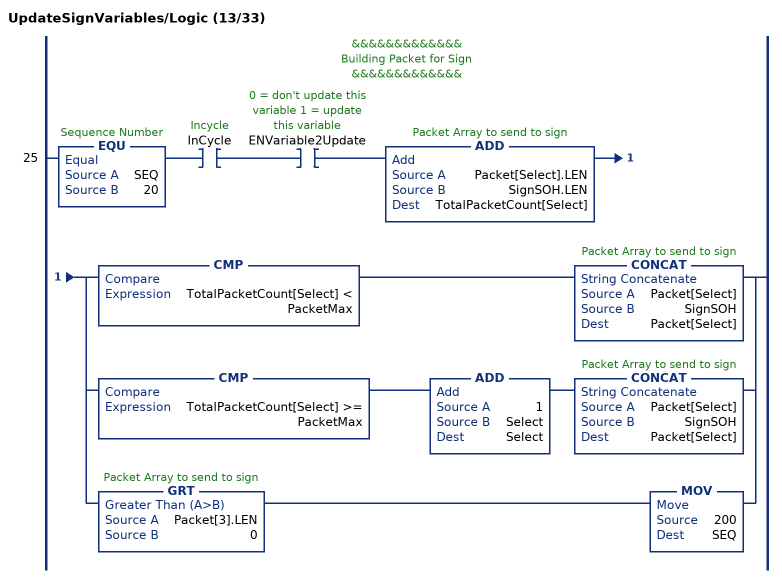
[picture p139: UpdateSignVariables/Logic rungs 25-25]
   // &&&&&&&&&&&&&
   // Building Packet for Sign
   // &&&&&&&&&&&&&
   25: EQU(SEQ,20)XIC(InCycle)XIC(ENVariable2Update)ADD(Packet[Select].LEN,SignSOH.LEN,TotalPacketCount[Select])[CMP(TotalPacketCount[Select] < PacketMax) CONCAT(Packet[Select],SignSOH,Packet[Select]) ,CMP(TotalPacketCount[Select] >= PacketMax) ADD(1,Select,Select) CONCAT(Packet[Select],SignSOH,Packet[Select]) ,GRT(Packet[3].LEN,0) MOV(200,SEQ) ];
(* Logix 5000 project; controller Electronic_Displays vendor 1 type 14 code 65 rev 17.4; software revision 17.01; part 7 of 8 *)
(* tags used below, declared in another part *)
   ENVariable2Update : BOOL;   // 0 = don't update this variable 1 = update this variable
   ENVariable3Update : BOOL;   // 0 = don't update this variable 1 = update this variable
   ENVariable4Update : BOOL;   // 0 = don't update this variable 1 = update this variable
   DN : BOOL;   // Instruction Interface Done Bit
   ER : BOOL;   // Instruction Interface Error Bit
   map_SignOutput : SINT[496];   // Ethernet/IP LEDSIGN.O Data I/O Mapping
   Packet1Sent : STRING;   // The actual packet sent to the sign (Packet1)
   Packet2Sent : STRING;   // The actual packet sent to the sign (Packet2)
   Packet3Sent : STRING;   // The actual packet sent to the sign (Packet3)
   SEQ : DINT;   // Sequence Number
   InCycle : BOOL;   // Incycle
   Error : BOOL;   // Error
   Done : BOOL;   // Done
   SignETX : STRING;   // DO NOT EDIT = ^C
   SignSOH : STRING;   // DO NOT EDIT = ^A
   SignAddress : STRING;
   SignSTX : STRING;   // DO NOT EDIT = ^B
   SignVariable4Name : STRING;
   SignVariable3Name : STRING;
   SignVariable2Name : STRING;
   SignCommandCode : STRING;   // DO NOT EDIT = B
   SignVariable4Value : STRING;
   SignVariable3Value : STRING;
   SignVariable2Value : STRING;
   TotalPacketCount : DINT[7];   // Total Character Count
   Select : DINT;   // Packet Array Select
   PacketMax : DINT;   // Max Packet Count
   Packet3Offset : DINT;
   Packet2Offset : DINT;
   Packet1Offset : DINT;
   Packet : STRING[7];   // Packet Array to send to sign
(* UpdateSignVariables, continued *)

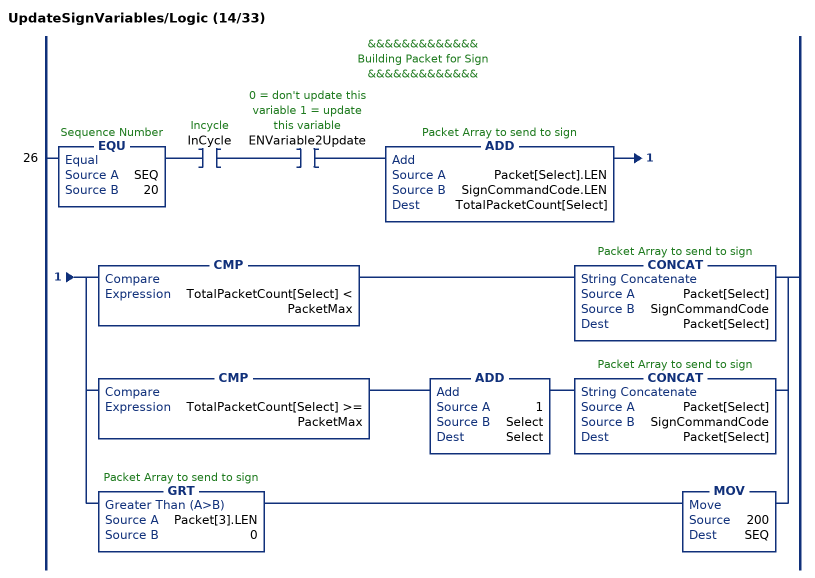
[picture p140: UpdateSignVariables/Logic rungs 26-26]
   // &&&&&&&&&&&&&
   // Building Packet for Sign
   // &&&&&&&&&&&&&
   26: EQU(SEQ,20)XIC(InCycle)XIC(ENVariable2Update)ADD(Packet[Select].LEN,SignCommandCode.LEN,TotalPacketCount[Select])[CMP(TotalPacketCount[Select] < PacketMax) CONCAT(Packet[Select],SignCommandCode,Packet[Select]) ,CMP(TotalPacketCount[Select] >= PacketMax) ADD(1,Select,Select) CONCAT(Packet[Select],SignCommandCode,Packet[Select]) ,GRT(Packet[3].LEN,0) MOV(200,SEQ) ];
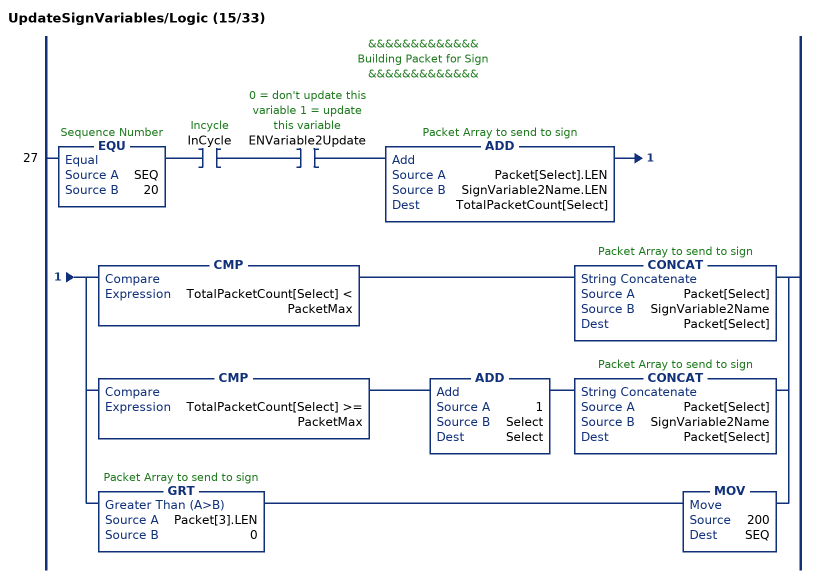
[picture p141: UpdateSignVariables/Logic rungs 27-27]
   // &&&&&&&&&&&&&
   // Building Packet for Sign
   // &&&&&&&&&&&&&
   27: EQU(SEQ,20)XIC(InCycle)XIC(ENVariable2Update)ADD(Packet[Select].LEN,SignVariable2Name.LEN,TotalPacketCount[Select])[CMP(TotalPacketCount[Select] < PacketMax) CONCAT(Packet[Select],SignVariable2Name,Packet[Select]) ,CMP(TotalPacketCount[Select] >= PacketMax) ADD(1,Select,Select) CONCAT(Packet[Select],SignVariable2Name,Packet[Select]) ,GRT(Packet[3].LEN,0) MOV(200,SEQ) ];
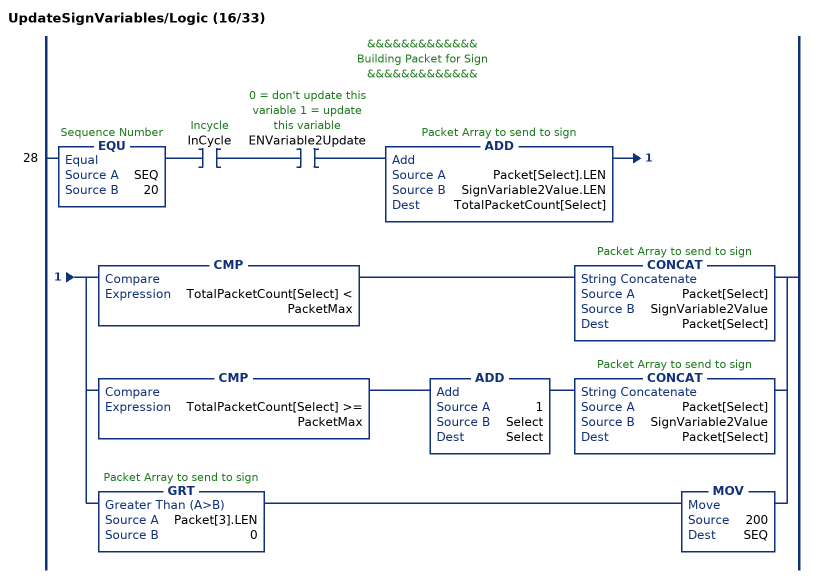
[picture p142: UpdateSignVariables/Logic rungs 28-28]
   // &&&&&&&&&&&&&
   // Building Packet for Sign
   // &&&&&&&&&&&&&
   28: EQU(SEQ,20)XIC(InCycle)XIC(ENVariable2Update)ADD(Packet[Select].LEN,SignVariable2Value.LEN,TotalPacketCount[Select])[CMP(TotalPacketCount[Select] < PacketMax) CONCAT(Packet[Select],SignVariable2Value,Packet[Select]) ,CMP(TotalPacketCount[Select] >= PacketMax) ADD(1,Select,Select) CONCAT(Packet[Select],SignVariable2Value,Packet[Select]) ,GRT(Packet[3].LEN,0) MOV(200,SEQ) ];
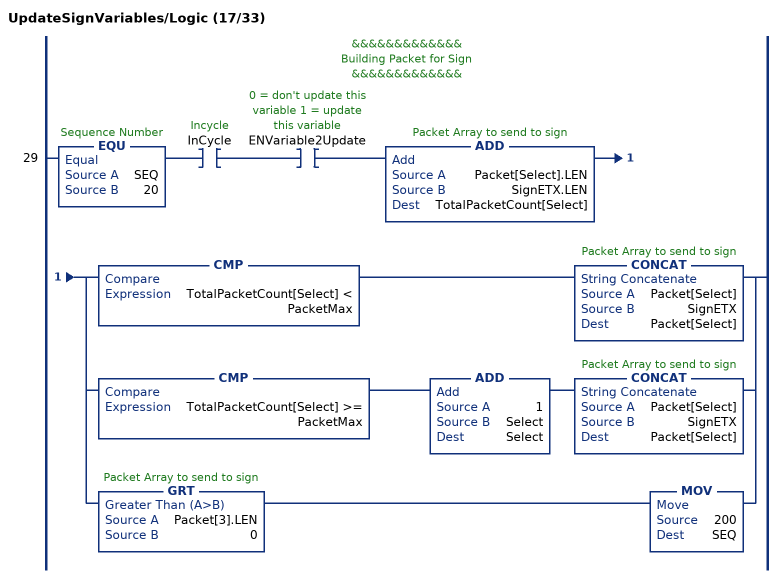
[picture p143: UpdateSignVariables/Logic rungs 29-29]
   // &&&&&&&&&&&&&
   // Building Packet for Sign
   // &&&&&&&&&&&&&
   29: EQU(SEQ,20)XIC(InCycle)XIC(ENVariable2Update)ADD(Packet[Select].LEN,SignETX.LEN,TotalPacketCount[Select])[CMP(TotalPacketCount[Select] < PacketMax) CONCAT(Packet[Select],SignETX,Packet[Select]) ,CMP(TotalPacketCount[Select] >= PacketMax) ADD(1,Select,Select) CONCAT(Packet[Select],SignETX,Packet[Select]) ,GRT(Packet[3].LEN,0) MOV(200,SEQ) ];
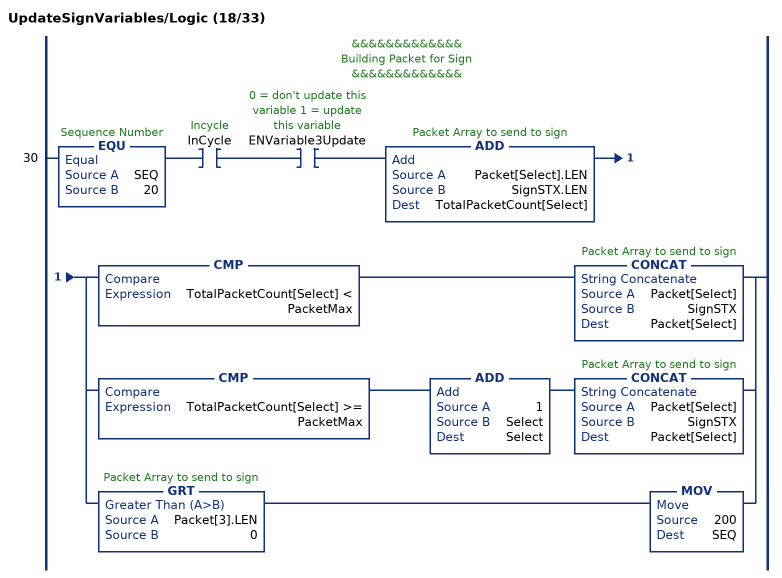
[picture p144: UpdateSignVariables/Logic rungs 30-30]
   // &&&&&&&&&&&&&
   // Building Packet for Sign
   // &&&&&&&&&&&&&
   30: EQU(SEQ,20)XIC(InCycle)XIC(ENVariable3Update)ADD(Packet[Select].LEN,SignSTX.LEN,TotalPacketCount[Select])[CMP(TotalPacketCount[Select] < PacketMax) CONCAT(Packet[Select],SignSTX,Packet[Select]) ,CMP(TotalPacketCount[Select] >= PacketMax) ADD(1,Select,Select) CONCAT(Packet[Select],SignSTX,Packet[Select]) ,GRT(Packet[3].LEN,0) MOV(200,SEQ) ];
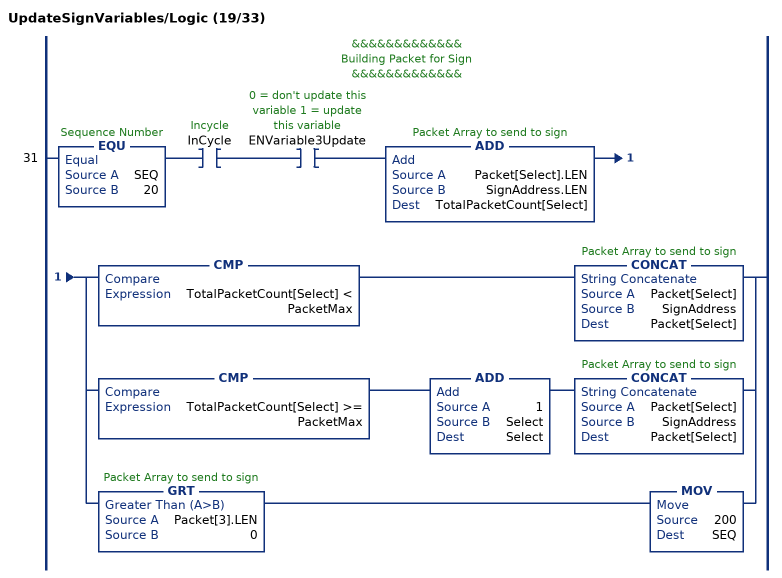
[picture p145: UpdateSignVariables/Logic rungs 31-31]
   // &&&&&&&&&&&&&
   // Building Packet for Sign
   // &&&&&&&&&&&&&
   31: EQU(SEQ,20)XIC(InCycle)XIC(ENVariable3Update)ADD(Packet[Select].LEN,SignAddress.LEN,TotalPacketCount[Select])[CMP(TotalPacketCount[Select] < PacketMax) CONCAT(Packet[Select],SignAddress,Packet[Select]) ,CMP(TotalPacketCount[Select] >= PacketMax) ADD(1,Select,Select) CONCAT(Packet[Select],SignAddress,Packet[Select]) ,GRT(Packet[3].LEN,0) MOV(200,SEQ) ];
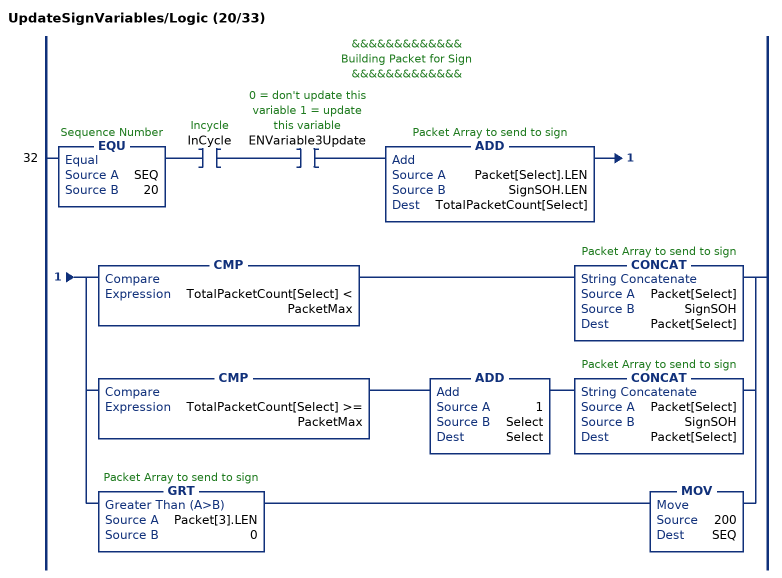
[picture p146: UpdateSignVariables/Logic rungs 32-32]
   // &&&&&&&&&&&&&
   // Building Packet for Sign
   // &&&&&&&&&&&&&
   32: EQU(SEQ,20)XIC(InCycle)XIC(ENVariable3Update)ADD(Packet[Select].LEN,SignSOH.LEN,TotalPacketCount[Select])[CMP(TotalPacketCount[Select] < PacketMax) CONCAT(Packet[Select],SignSOH,Packet[Select]) ,CMP(TotalPacketCount[Select] >= PacketMax) ADD(1,Select,Select) CONCAT(Packet[Select],SignSOH,Packet[Select]) ,GRT(Packet[3].LEN,0) MOV(200,SEQ) ];
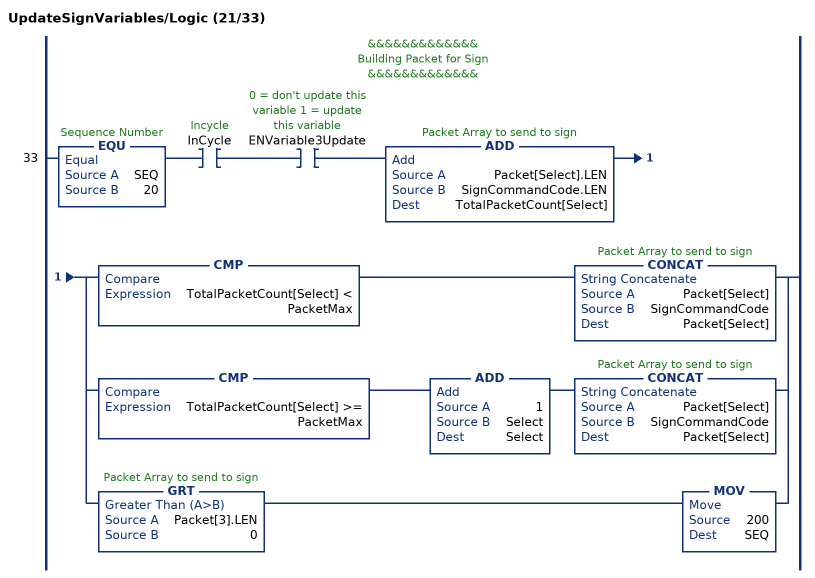
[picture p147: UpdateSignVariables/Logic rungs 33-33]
   // &&&&&&&&&&&&&
   // Building Packet for Sign
   // &&&&&&&&&&&&&
   33: EQU(SEQ,20)XIC(InCycle)XIC(ENVariable3Update)ADD(Packet[Select].LEN,SignCommandCode.LEN,TotalPacketCount[Select])[CMP(TotalPacketCount[Select] < PacketMax) CONCAT(Packet[Select],SignCommandCode,Packet[Select]) ,CMP(TotalPacketCount[Select] >= PacketMax) ADD(1,Select,Select) CONCAT(Packet[Select],SignCommandCode,Packet[Select]) ,GRT(Packet[3].LEN,0) MOV(200,SEQ) ];
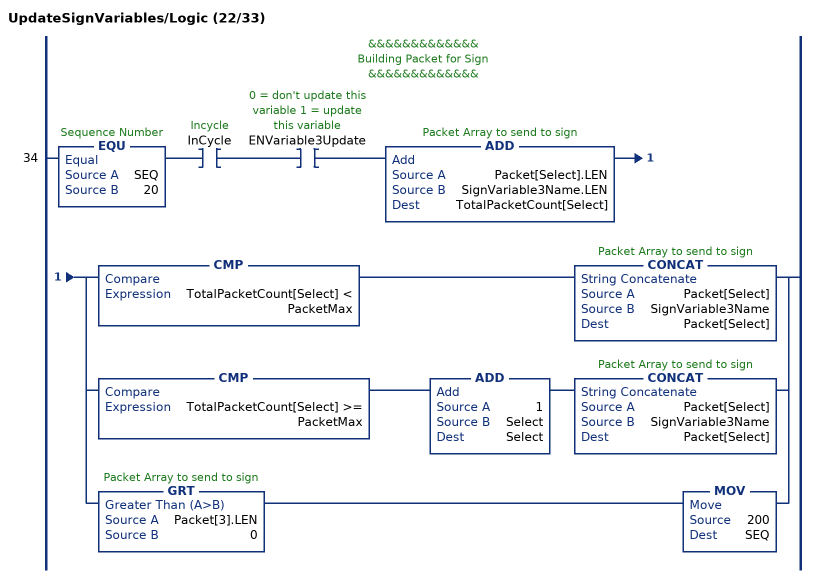
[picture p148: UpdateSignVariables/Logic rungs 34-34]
   // &&&&&&&&&&&&&
   // Building Packet for Sign
   // &&&&&&&&&&&&&
   34: EQU(SEQ,20)XIC(InCycle)XIC(ENVariable3Update)ADD(Packet[Select].LEN,SignVariable3Name.LEN,TotalPacketCount[Select])[CMP(TotalPacketCount[Select] < PacketMax) CONCAT(Packet[Select],SignVariable3Name,Packet[Select]) ,CMP(TotalPacketCount[Select] >= PacketMax) ADD(1,Select,Select) CONCAT(Packet[Select],SignVariable3Name,Packet[Select]) ,GRT(Packet[3].LEN,0) MOV(200,SEQ) ];
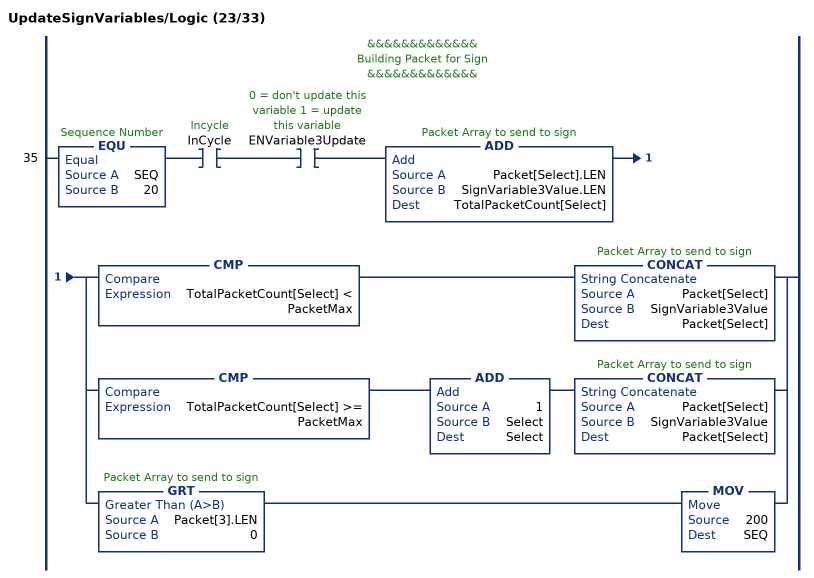
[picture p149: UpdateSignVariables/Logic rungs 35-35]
   // &&&&&&&&&&&&&
   // Building Packet for Sign
   // &&&&&&&&&&&&&
   35: EQU(SEQ,20)XIC(InCycle)XIC(ENVariable3Update)ADD(Packet[Select].LEN,SignVariable3Value.LEN,TotalPacketCount[Select])[CMP(TotalPacketCount[Select] < PacketMax) CONCAT(Packet[Select],SignVariable3Value,Packet[Select]) ,CMP(TotalPacketCount[Select] >= PacketMax) ADD(1,Select,Select) CONCAT(Packet[Select],SignVariable3Value,Packet[Select]) ,GRT(Packet[3].LEN,0) MOV(200,SEQ) ];
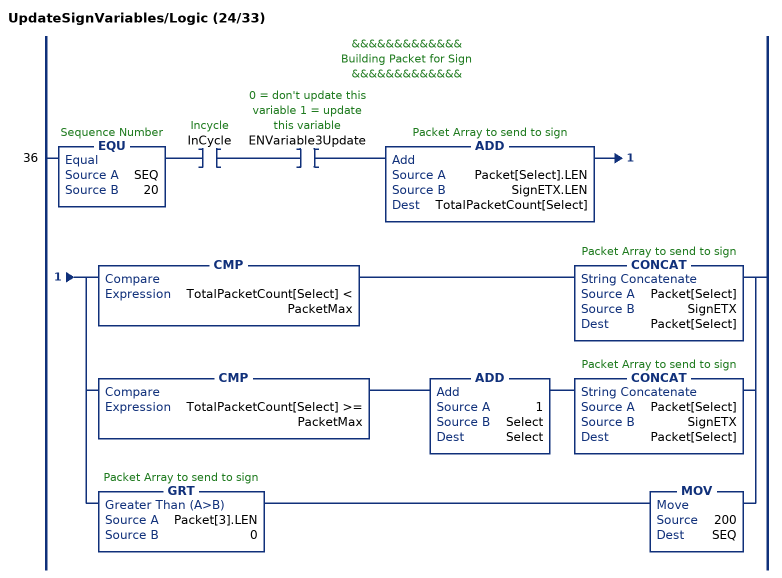
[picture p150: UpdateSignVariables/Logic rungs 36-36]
   // &&&&&&&&&&&&&
   // Building Packet for Sign
   // &&&&&&&&&&&&&
   36: EQU(SEQ,20)XIC(InCycle)XIC(ENVariable3Update)ADD(Packet[Select].LEN,SignETX.LEN,TotalPacketCount[Select])[CMP(TotalPacketCount[Select] < PacketMax) CONCAT(Packet[Select],SignETX,Packet[Select]) ,CMP(TotalPacketCount[Select] >= PacketMax) ADD(1,Select,Select) CONCAT(Packet[Select],SignETX,Packet[Select]) ,GRT(Packet[3].LEN,0) MOV(200,SEQ) ];
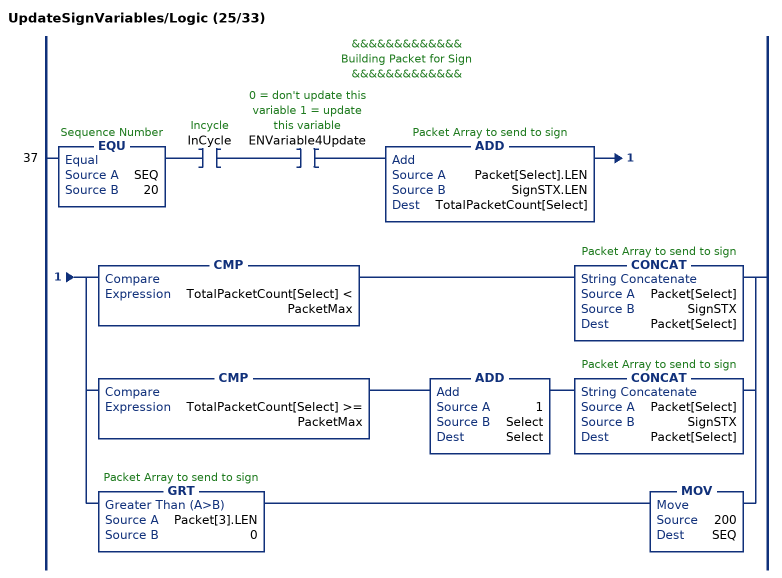
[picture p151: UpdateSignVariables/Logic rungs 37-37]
   // &&&&&&&&&&&&&
   // Building Packet for Sign
   // &&&&&&&&&&&&&
   37: EQU(SEQ,20)XIC(InCycle)XIC(ENVariable4Update)ADD(Packet[Select].LEN,SignSTX.LEN,TotalPacketCount[Select])[CMP(TotalPacketCount[Select] < PacketMax) CONCAT(Packet[Select],SignSTX,Packet[Select]) ,CMP(TotalPacketCount[Select] >= PacketMax) ADD(1,Select,Select) CONCAT(Packet[Select],SignSTX,Packet[Select]) ,GRT(Packet[3].LEN,0) MOV(200,SEQ) ];
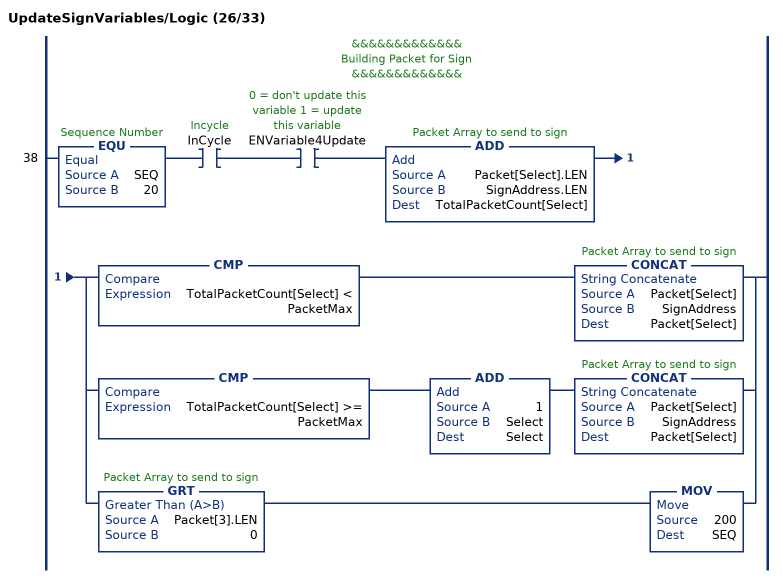
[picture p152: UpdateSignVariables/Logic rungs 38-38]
   // &&&&&&&&&&&&&
   // Building Packet for Sign
   // &&&&&&&&&&&&&
   38: EQU(SEQ,20)XIC(InCycle)XIC(ENVariable4Update)ADD(Packet[Select].LEN,SignAddress.LEN,TotalPacketCount[Select])[CMP(TotalPacketCount[Select] < PacketMax) CONCAT(Packet[Select],SignAddress,Packet[Select]) ,CMP(TotalPacketCount[Select] >= PacketMax) ADD(1,Select,Select) CONCAT(Packet[Select],SignAddress,Packet[Select]) ,GRT(Packet[3].LEN,0) MOV(200,SEQ) ];
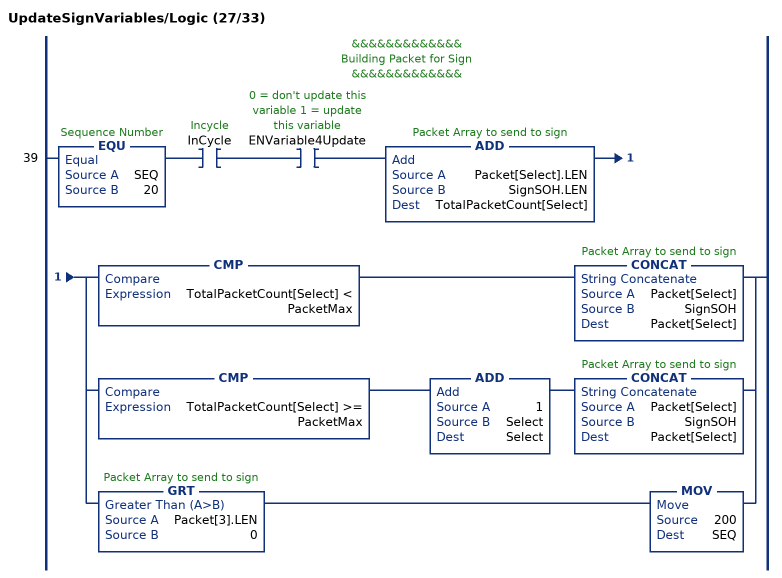
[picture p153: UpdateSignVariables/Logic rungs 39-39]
   // &&&&&&&&&&&&&
   // Building Packet for Sign
   // &&&&&&&&&&&&&
   39: EQU(SEQ,20)XIC(InCycle)XIC(ENVariable4Update)ADD(Packet[Select].LEN,SignSOH.LEN,TotalPacketCount[Select])[CMP(TotalPacketCount[Select] < PacketMax) CONCAT(Packet[Select],SignSOH,Packet[Select]) ,CMP(TotalPacketCount[Select] >= PacketMax) ADD(1,Select,Select) CONCAT(Packet[Select],SignSOH,Packet[Select]) ,GRT(Packet[3].LEN,0) MOV(200,SEQ) ];
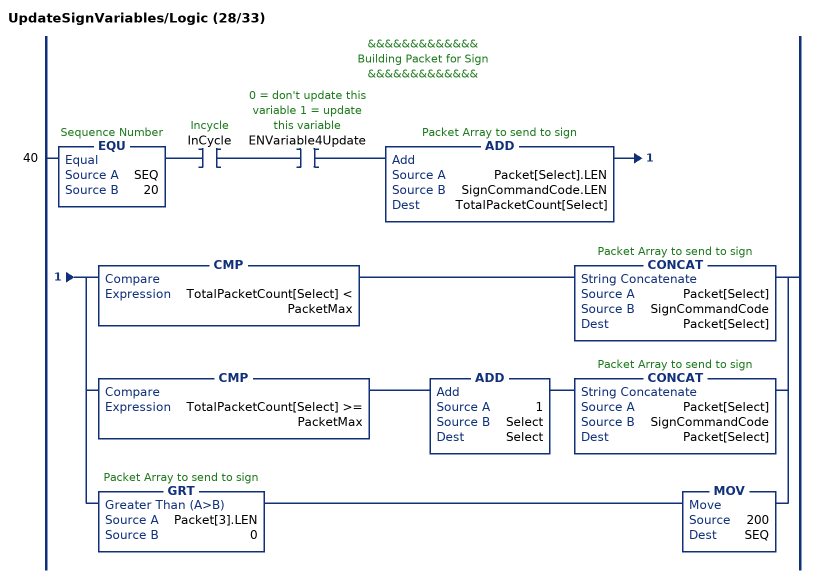
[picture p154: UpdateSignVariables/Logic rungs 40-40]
   // &&&&&&&&&&&&&
   // Building Packet for Sign
   // &&&&&&&&&&&&&
   40: EQU(SEQ,20)XIC(InCycle)XIC(ENVariable4Update)ADD(Packet[Select].LEN,SignCommandCode.LEN,TotalPacketCount[Select])[CMP(TotalPacketCount[Select] < PacketMax) CONCAT(Packet[Select],SignCommandCode,Packet[Select]) ,CMP(TotalPacketCount[Select] >= PacketMax) ADD(1,Select,Select) CONCAT(Packet[Select],SignCommandCode,Packet[Select]) ,GRT(Packet[3].LEN,0) MOV(200,SEQ) ];
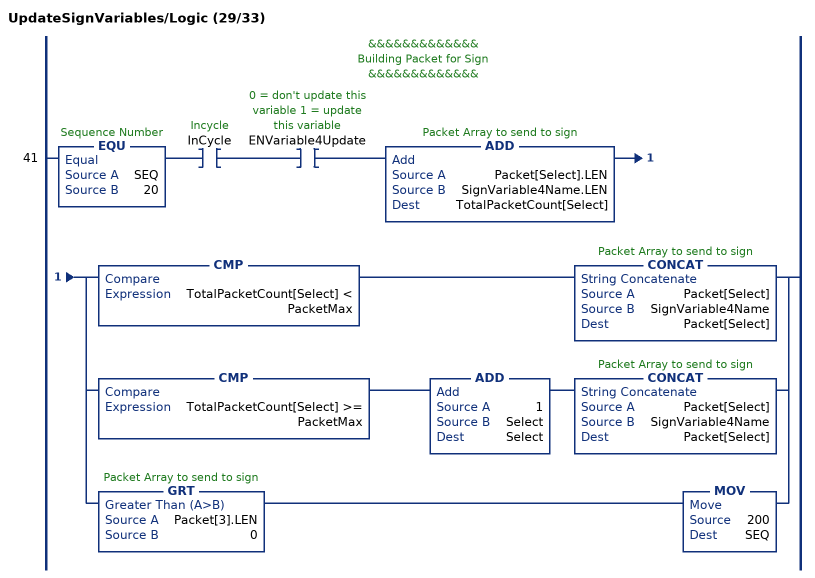
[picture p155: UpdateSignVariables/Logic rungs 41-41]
   // &&&&&&&&&&&&&
   // Building Packet for Sign
   // &&&&&&&&&&&&&
   41: EQU(SEQ,20)XIC(InCycle)XIC(ENVariable4Update)ADD(Packet[Select].LEN,SignVariable4Name.LEN,TotalPacketCount[Select])[CMP(TotalPacketCount[Select] < PacketMax) CONCAT(Packet[Select],SignVariable4Name,Packet[Select]) ,CMP(TotalPacketCount[Select] >= PacketMax) ADD(1,Select,Select) CONCAT(Packet[Select],SignVariable4Name,Packet[Select]) ,GRT(Packet[3].LEN,0) MOV(200,SEQ) ];
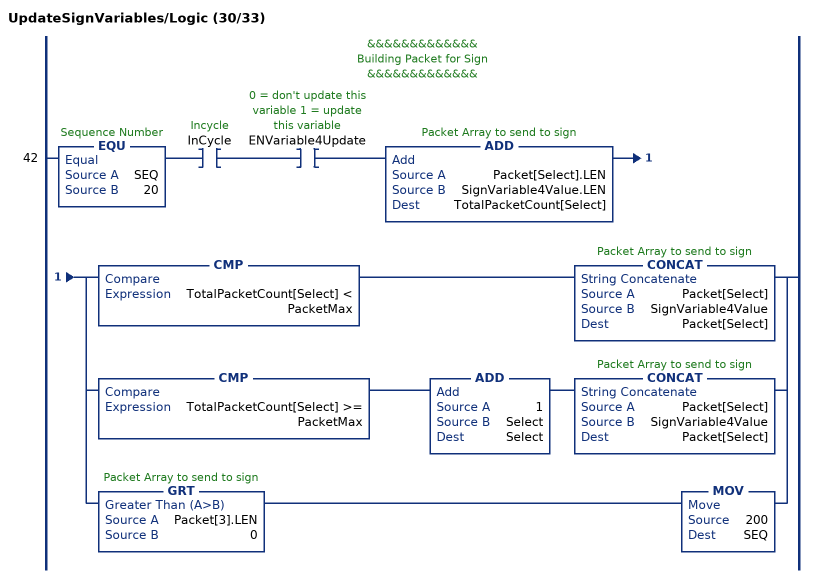
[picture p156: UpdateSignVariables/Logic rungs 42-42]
   // &&&&&&&&&&&&&
   // Building Packet for Sign
   // &&&&&&&&&&&&&
   42: EQU(SEQ,20)XIC(InCycle)XIC(ENVariable4Update)ADD(Packet[Select].LEN,SignVariable4Value.LEN,TotalPacketCount[Select])[CMP(TotalPacketCount[Select] < PacketMax) CONCAT(Packet[Select],SignVariable4Value,Packet[Select]) ,CMP(TotalPacketCount[Select] >= PacketMax) ADD(1,Select,Select) CONCAT(Packet[Select],SignVariable4Value,Packet[Select]) ,GRT(Packet[3].LEN,0) MOV(200,SEQ) ];
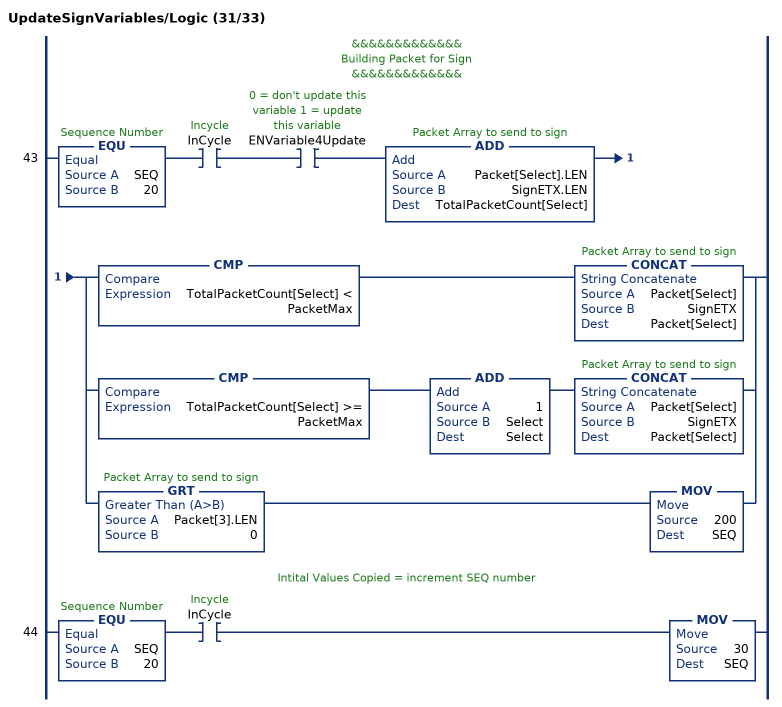
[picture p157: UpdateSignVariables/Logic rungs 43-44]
   // &&&&&&&&&&&&&
   // Building Packet for Sign
   // &&&&&&&&&&&&&
   43: EQU(SEQ,20)XIC(InCycle)XIC(ENVariable4Update)ADD(Packet[Select].LEN,SignETX.LEN,TotalPacketCount[Select])[CMP(TotalPacketCount[Select] < PacketMax) CONCAT(Packet[Select],SignETX,Packet[Select]) ,CMP(TotalPacketCount[Select] >= PacketMax) ADD(1,Select,Select) CONCAT(Packet[Select],SignETX,Packet[Select]) ,GRT(Packet[3].LEN,0) MOV(200,SEQ) ];
   // Intital Values Copied = increment SEQ number
   44: EQU(SEQ,20)XIC(InCycle)MOV(30,SEQ);
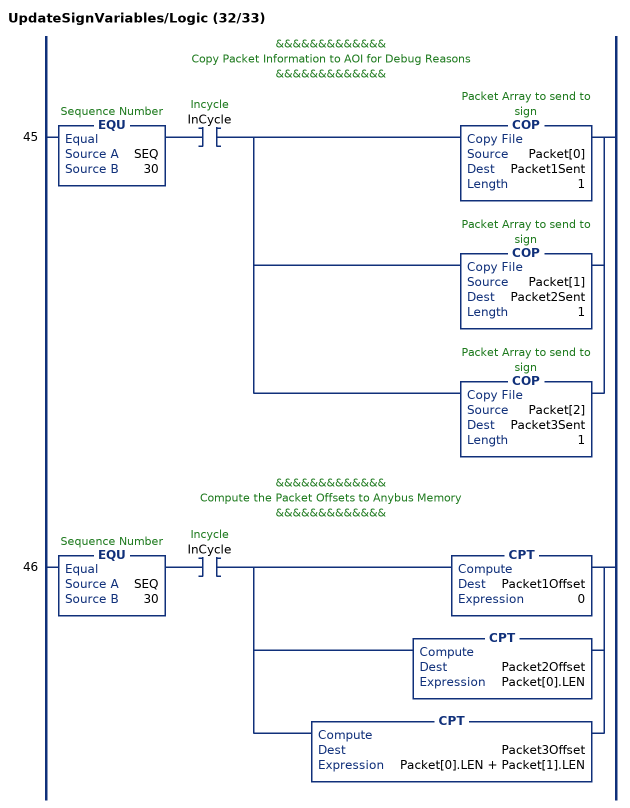
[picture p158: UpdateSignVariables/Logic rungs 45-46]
   // &&&&&&&&&&&&&
   // Copy Packet Information to AOI for Debug Reasons
   // &&&&&&&&&&&&&
   45: EQU(SEQ,30)XIC(InCycle)[COP(Packet[0],Packet1Sent,1) ,COP(Packet[1],Packet2Sent,1) ,COP(Packet[2],Packet3Sent,1) ];
   // &&&&&&&&&&&&&
   // Compute the Packet Offsets to Anybus Memory
   // &&&&&&&&&&&&&
   46: EQU(SEQ,30)XIC(InCycle)[CPT(Packet1Offset,0) ,CPT(Packet2Offset,Packet[0].LEN) ,CPT(Packet3Offset,Packet[0].LEN + Packet[1].LEN) ];
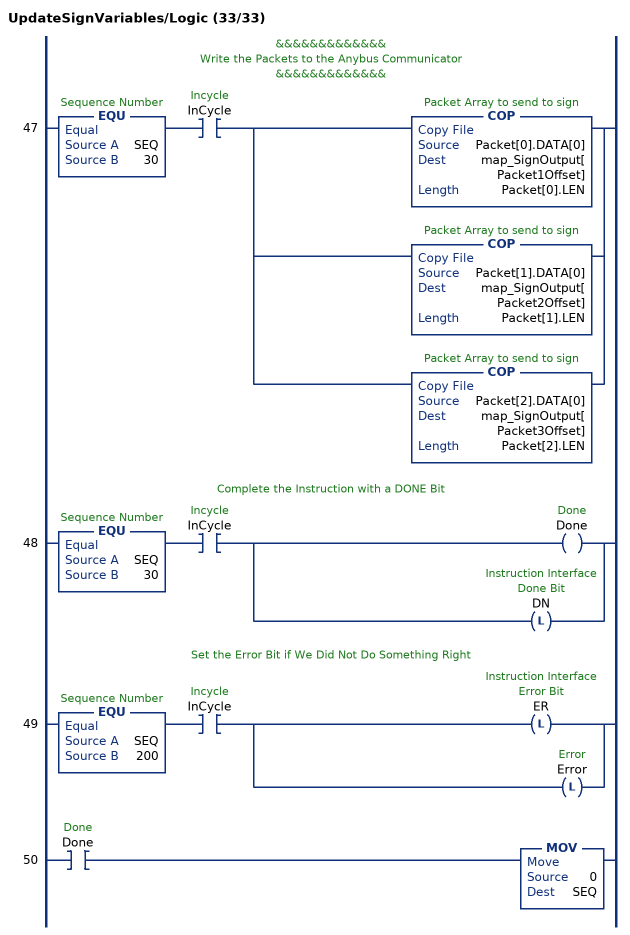
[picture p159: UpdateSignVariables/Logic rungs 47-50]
   // &&&&&&&&&&&&&
   // Write the Packets to the Anybus Communicator
   // &&&&&&&&&&&&&
   47: EQU(SEQ,30)XIC(InCycle)[COP(Packet[0].DATA[0],map_SignOutput[Packet1Offset],Packet[0].LEN) ,COP(Packet[1].DATA[0],map_SignOutput[Packet2Offset],Packet[1].LEN) ,COP(Packet[2].DATA[0],map_SignOutput[Packet3Offset],Packet[2].LEN) ];
   // Complete the Instruction with a DONE Bit
   48: EQU(SEQ,30)XIC(InCycle)[OTE(Done) ,OTL(DN) ];
   // Set the Error Bit if We Did Not Do Something Right
   49: EQU(SEQ,200)XIC(InCycle)[OTL(ER) ,OTL(Error) ];
   50: XIC(Done)MOV(0,SEQ);
END_ROUTINE
END_ADD_ON_INSTRUCTION
(* Logix 5000 project; controller Electronic_Displays vendor 1 type 14 code 65 rev 17.4; software revision 17.01; part 8 of 8 *)

VAR_GLOBAL   (* controller tags *)
   ALWAYS_ON : BOOL;
   ColorGreen : STRING := '1';
   ColorRed : STRING := '0';
   Counts_BadParts : DINT := 31;
   Counts_Cycle : STRING := '1.389';
   Counts_GoodParts : DINT := 288;
   Counts_OEE : STRING := '90.28';
   Counts_TotalParts : DINT := 319;
   CycleTime : STRING := '0.03500000';
   CycleTimeReal : REAL := 1.377;
   NEVER_ON : BOOL;
   NumberSign : NUMSIGN := (Address := '01', NumberValue := 31.0, PacketSent := '$020131$03');
   NumSign01Tag1 : NumberSign;
   OEE_String : STRING := '90.2821274';
   OEEScore : REAL := 90.28213;
   Sign01 : LEDSIGN := (Address := '01', CommandCode := 'A', FileLabel := 'A', Text1Message := 'Total ', Text2Message := 'Rejects ', Text3Message := 'Cycle Time   ', Text4Message := 'OEE Score    ', TextFont := '0', TextColor := '1', TextAlign := 'L', TextAttribute := '5', TextEffect := 'H', TextSpeed := '3', TextPause := '02', Variable1Name := 'U', Variable2Name := 'V', Variable3Name := 'W', Variable4Name := 'X', Variable1Value := '321', Variable2Value := '32', Variable3Value := '0.010', Variable4Value := '90.03', VariableFont := '0', VariableColor := '0', VariableAttribute := '4', Packet1Sent := '^B01^ABU10280^C^B01^ABV42^C^B01^ABW1.723^C^B01^ABX99.59^C');
   Sign01Tag0 : ResetSign;
   Sign01Tag1 : SetupSignVariables := (ENVariable1Message := 1, ENVariable2Message := 1, ENVariable3Message := 1, ENVariable4Message := 1);
   Sign01Tag2 : SendSignMessage := (ENText1Message := 1, ENText2Message := 1, ENText3Message := 1, ENText4Message := 1, ENTextFormats := 1, ENVariable1Message := 1, ENVariable2Message := 1, ENVariable3Message := 1, ENVariable4Message := 1, ENVariableFormats := 1);
   Sign01Tag3 : UpdateSignVariables := (ENVariable1Update := 1, ENVariable2Update := 1, ENVariable3Update := 1, ENVariable4Update := 1);
   Sign01Tag4 : ExpertSign;
   Sign02_LD : LEDSIGN := (Address := '02', CommandCode := 'D', FileLabel := 'A', Text1Message := 'Line is Down', TextFont := '3', TextColor := '0', TextAlign := 'F', TextAttribute := '0', TextEffect := 'H', TextSpeed := '2', TextPause := '05', VariableFont := '3', VariableColor := '0', VariableAttribute := '0', Packet1Sent := '^B02^ADA^F3^O0^GFH^H0Line is Down^C');
   Sign02_LineDown : SendSignMessage := (ENText1Message := 1, ENTextFormats := 1);
   Sign02_LineUp : SendSignMessage := (ENText1Message := 1, ENTextFormats := 1);
   Sign02_LU : LEDSIGN := (Address := '02', CommandCode := 'D', FileLabel := 'A', Text1Message := 'Line is Running', TextFont := '2', TextColor := '1', TextAlign := 'F', TextAttribute := '5', TextEffect := 'H', TextSpeed := '3', TextPause := '02', VariableFont := '3', VariableColor := '0', VariableAttribute := '0', Packet1Sent := '^B02^ADA^F2^O1^GFH^H5Line is Running^C');
   Timer02 : TIMER := (PRE := 10000);
   Timer02_1 : TIMER := (PRE := 2000);
   Timer_BadParts : TIMER := (PRE := 10000);
   Timer_GoodParts : TIMER := (PRE := 2000);
   TOGGLE : DINT := 1048584;
   Toggle02 : BOOL;
   UpdateSign01Timer : TIMER := (PRE := 1000);
END_VAR

PROGRAM MainProgram   (* main routine MainRoutine *)

ROUTINE MainRoutine   (* ladder *)
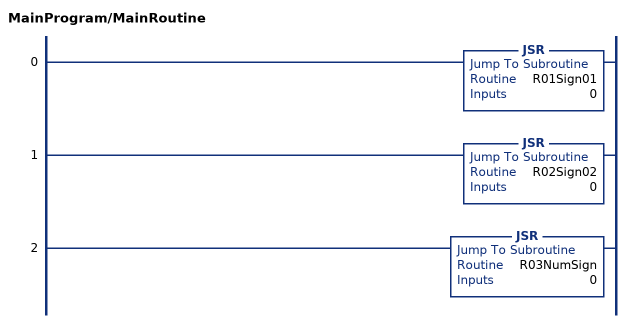
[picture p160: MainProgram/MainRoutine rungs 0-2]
   0: JSR(R01Sign01,0);
   1: JSR(R02Sign02,0);
   2: JSR(R03NumSign,0);
END_ROUTINE

ROUTINE R01Sign01   (* ladder *)
// Sign Address 01
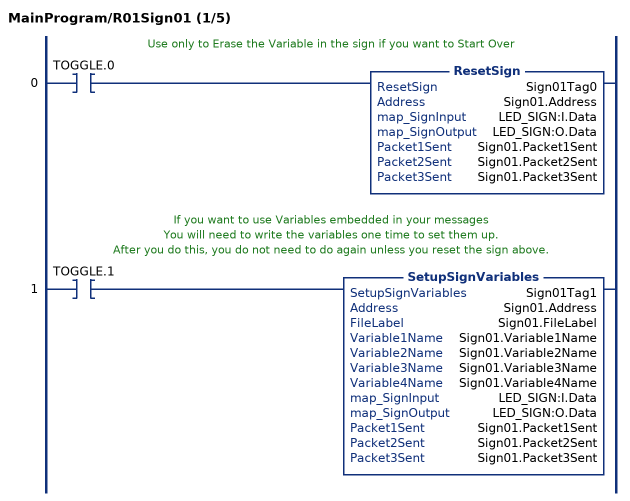
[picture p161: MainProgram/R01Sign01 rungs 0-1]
   // Use only to Erase the Variable in the sign if you want to Start Over
   0: XIC(TOGGLE.0)ResetSign(Sign01Tag0,Sign01.Address,LED_SIGN:I.Data,LED_SIGN:O.Data,Sign01.Packet1Sent,Sign01.Packet2Sent,Sign01.Packet3Sent);
   // If you want to use Variables embedded in your messages
   // You will need to write the variables one time to set them up.
   // After you do this, you do not need to do again unless you reset the sign above.
   1: XIC(TOGGLE.1)SetupSignVariables(Sign01Tag1,Sign01.Address,Sign01.FileLabel,Sign01.Variable1Name,Sign01.Variable2Name,Sign01.Variable3Name,Sign01.Variable4Name,LED_SIGN:I.Data,LED_SIGN:O.Data,Sign01.Packet1Sent,Sign01.Packet2Sent,Sign01.Packet3Sent);
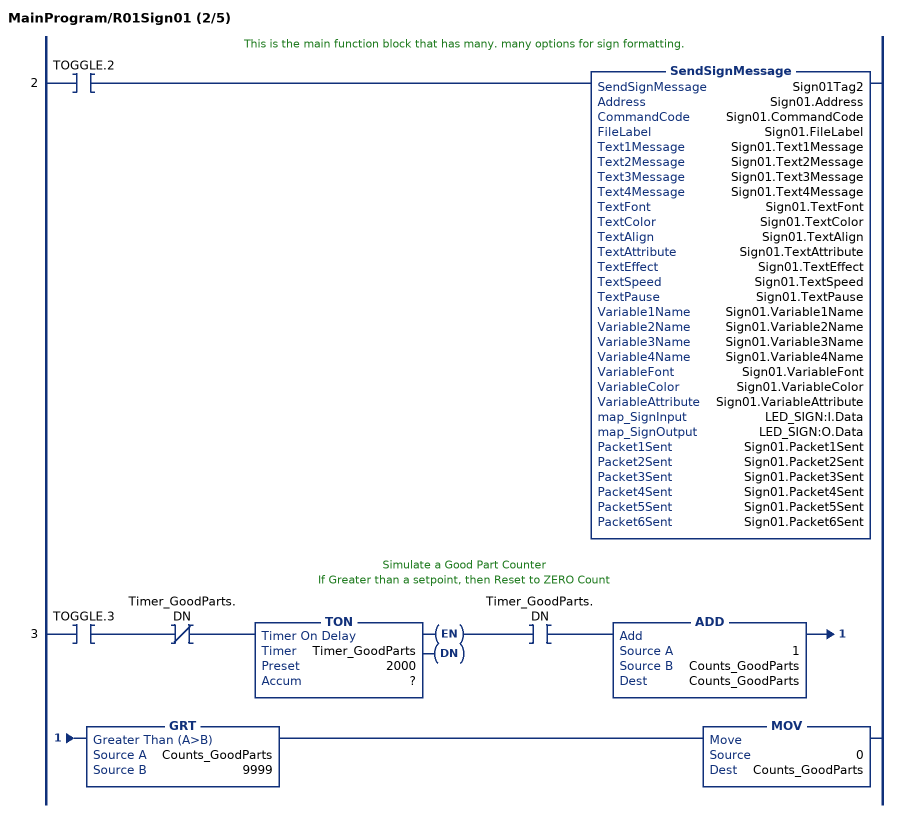
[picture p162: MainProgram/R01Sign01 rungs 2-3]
   // This is the main function block that has many. many options for sign formatting.
   2: XIC(TOGGLE.2)SendSignMessage(Sign01Tag2,Sign01.Address,Sign01.CommandCode,Sign01.FileLabel,Sign01.Text1Message,Sign01.Text2Message,Sign01.Text3Message,Sign01.Text4Message,Sign01.TextFont,Sign01.TextColor,Sign01.TextAlign,Sign01.TextAttribute,Sign01.TextEffect,Sign01.TextSpeed,Sign01.TextPause,Sign01.Variable1Name,Sign01.Variable2Name,Sign01.Variable3Name,Sign01.Variable4Name,Sign01.VariableFont,Sign01.VariableColor,Sign01.VariableAttribute,LED_SIGN:I.Data,LED_SIGN:O.Data,Sign01.Packet1Sent,Sign01.Packet2Sent,Sign01.Packet3Sent,Sign01.Packet4Sent,Sign01.Packet5Sent,Sign01.Packet6Sent);
   // Simulate a Good Part Counter
   // If Greater than a setpoint, then Reset to ZERO Count
   3: XIC(TOGGLE.3)XIO(Timer_GoodParts.DN)TON(Timer_GoodParts,?,?)XIC(Timer_GoodParts.DN)ADD(1,Counts_GoodParts,Counts_GoodParts)GRT(Counts_GoodParts,9999)MOV(0,Counts_GoodParts);
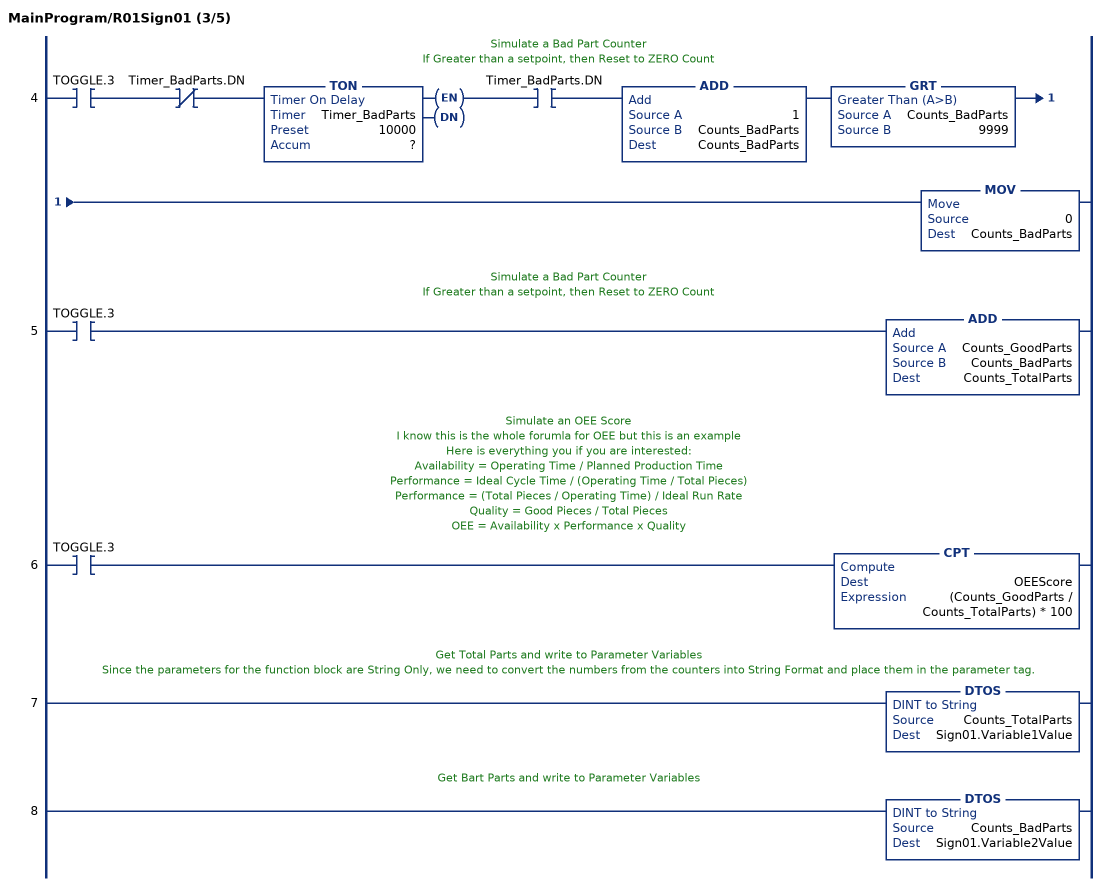
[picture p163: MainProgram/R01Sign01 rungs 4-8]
   // Simulate a Bad Part Counter
   // If Greater than a setpoint, then Reset to ZERO Count
   4: XIC(TOGGLE.3)XIO(Timer_BadParts.DN)TON(Timer_BadParts,?,?)XIC(Timer_BadParts.DN)ADD(1,Counts_BadParts,Counts_BadParts)GRT(Counts_BadParts,9999)MOV(0,Counts_BadParts);
   // Simulate a Bad Part Counter
   // If Greater than a setpoint, then Reset to ZERO Count
   5: XIC(TOGGLE.3)ADD(Counts_GoodParts,Counts_BadParts,Counts_TotalParts);
   // Simulate an OEE Score
   // I know this is the whole forumla for OEE but this is an example
   // Here is everything you if you are interested:
   // Availability = Operating Time / Planned Production Time
   // Performance = Ideal Cycle Time / (Operating Time / Total Pieces)
   // Performance = (Total Pieces / Operating Time) / Ideal Run Rate
   // Quality = Good Pieces / Total Pieces
   // OEE = Availability x Performance x Quality
   6: XIC(TOGGLE.3)CPT(OEEScore,(Counts_GoodParts / Counts_TotalParts) * 100);
   // Get Total Parts and write to Parameter Variables
   // Since the parameters for the function block are String Only, we need to convert the numbers from the counters into String Format and place them in the parameter tag.
   7: DTOS(Counts_TotalParts,Sign01.Variable1Value);
   // Get Bart Parts and write to Parameter Variables
   8: DTOS(Counts_BadParts,Sign01.Variable2Value);
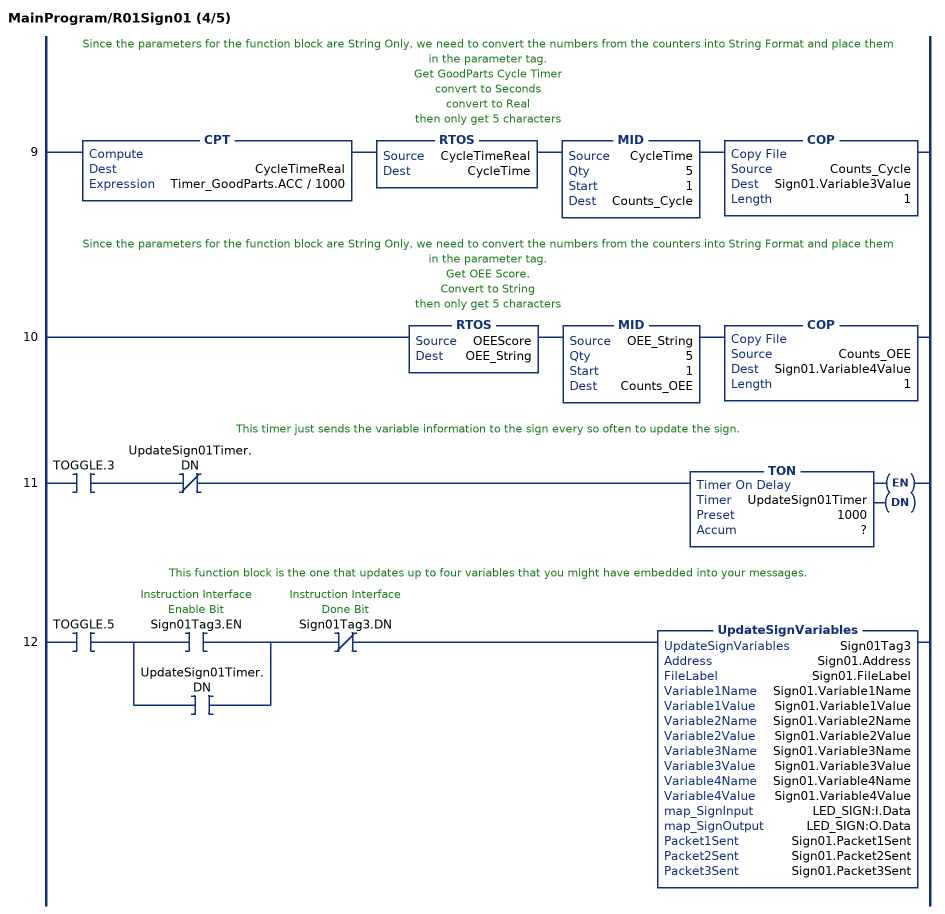
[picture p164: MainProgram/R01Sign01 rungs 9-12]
   // Since the parameters for the function block are String Only, we need to convert the numbers from the counters into String Format and place them in the parameter tag.
   // Get GoodParts Cycle Timer
   // convert to Seconds
   // convert to Real
   // then only get 5 characters
   9: CPT(CycleTimeReal,Timer_GoodParts.ACC / 1000)RTOS(CycleTimeReal,CycleTime)MID(CycleTime,5,1,Counts_Cycle)COP(Counts_Cycle,Sign01.Variable3Value,1);
   // Since the parameters for the function block are String Only, we need to convert the numbers from the counters into String Format and place them in the parameter tag.
   // Get OEE Score.
   // Convert to String
   // then only get 5 characters
   10: RTOS(OEEScore,OEE_String)MID(OEE_String,5,1,Counts_OEE)COP(Counts_OEE,Sign01.Variable4Value,1);
   // This timer just sends the variable information to the sign every so often to update the sign.
   11: XIC(TOGGLE.3)XIO(UpdateSign01Timer.DN)TON(UpdateSign01Timer,?,?);
   // This function block is the one that updates up to four variables that you might have embedded into your messages.
   12: XIC(TOGGLE.5)[XIC(Sign01Tag3.EN) ,XIC(UpdateSign01Timer.DN) ]XIO(Sign01Tag3.DN)UpdateSignVariables(Sign01Tag3,Sign01.Address,Sign01.FileLabel,Sign01.Variable1Name,Sign01.Variable1Value,Sign01.Variable2Name,Sign01.Variable2Value,Sign01.Variable3Name,Sign01.Variable3Value,Sign01.Variable4Name,Sign01.Variable4Value,LED_SIGN:I.Data,LED_SIGN:O.Data,Sign01.Packet1Sent,Sign01.Packet2Sent,Sign01.Packet3Sent);
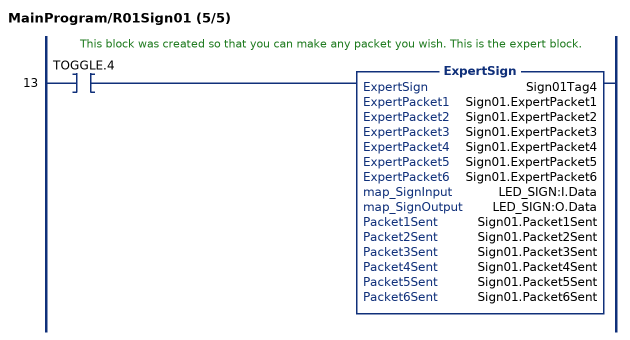
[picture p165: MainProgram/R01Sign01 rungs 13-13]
   // This block was created so that you can make any packet you wish. This is the expert block.
   13: XIC(TOGGLE.4)ExpertSign(Sign01Tag4,Sign01.ExpertPacket1,Sign01.ExpertPacket2,Sign01.ExpertPacket3,Sign01.ExpertPacket4,Sign01.ExpertPacket5,Sign01.ExpertPacket6,LED_SIGN:I.Data,LED_SIGN:O.Data,Sign01.Packet1Sent,Sign01.Packet2Sent,Sign01.Packet3Sent,Sign01.Packet4Sent,Sign01.Packet5Sent,Sign01.Packet6Sent);
END_ROUTINE

ROUTINE R02Sign02   (* ladder *)
// Sign Address 02
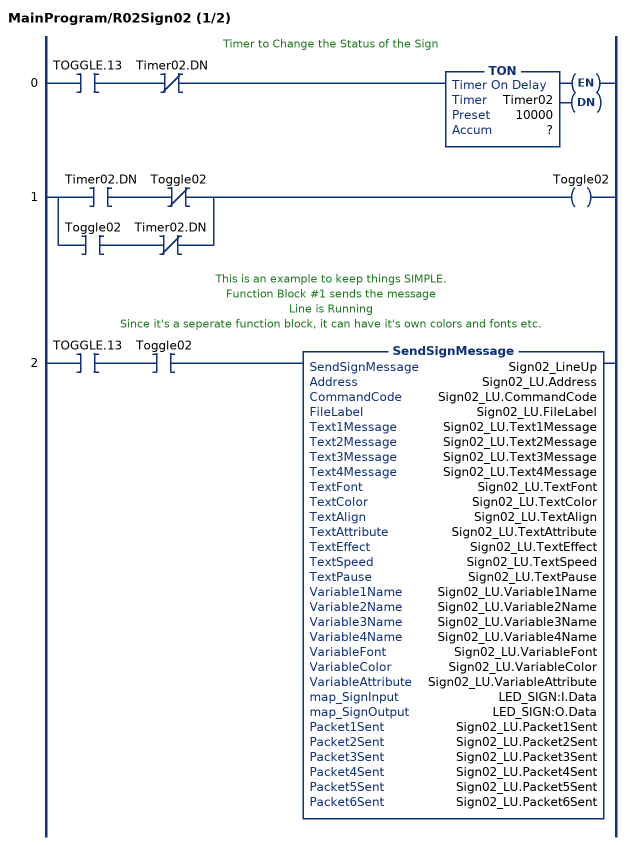
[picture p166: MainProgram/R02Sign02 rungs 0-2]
   // Timer to Change the Status of the Sign
   0: XIC(TOGGLE.13)XIO(Timer02.DN)TON(Timer02,?,?);
   1: [XIC(Timer02.DN) XIO(Toggle02) ,XIC(Toggle02) XIO(Timer02.DN) ]OTE(Toggle02);
   // This is an example to keep things SIMPLE.
   // Function Block #1 sends the message
   // Line is Running
   // Since it's a seperate function block, it can have it's own colors and fonts etc.
   2: XIC(TOGGLE.13)XIC(Toggle02)SendSignMessage(Sign02_LineUp,Sign02_LU.Address,Sign02_LU.CommandCode,Sign02_LU.FileLabel,Sign02_LU.Text1Message,Sign02_LU.Text2Message,Sign02_LU.Text3Message,Sign02_LU.Text4Message,Sign02_LU.TextFont,Sign02_LU.TextColor,Sign02_LU.TextAlign,Sign02_LU.TextAttribute,Sign02_LU.TextEffect,Sign02_LU.TextSpeed,Sign02_LU.TextPause,Sign02_LU.Variable1Name,Sign02_LU.Variable2Name,Sign02_LU.Variable3Name,Sign02_LU.Variable4Name,Sign02_LU.VariableFont,Sign02_LU.VariableColor,Sign02_LU.VariableAttribute,LED_SIGN:I.Data,LED_SIGN:O.Data,Sign02_LU.Packet1Sent,Sign02_LU.Packet2Sent,Sign02_LU.Packet3Sent,Sign02_LU.Packet4Sent,Sign02_LU.Packet5Sent,Sign02_LU.Packet6Sent);
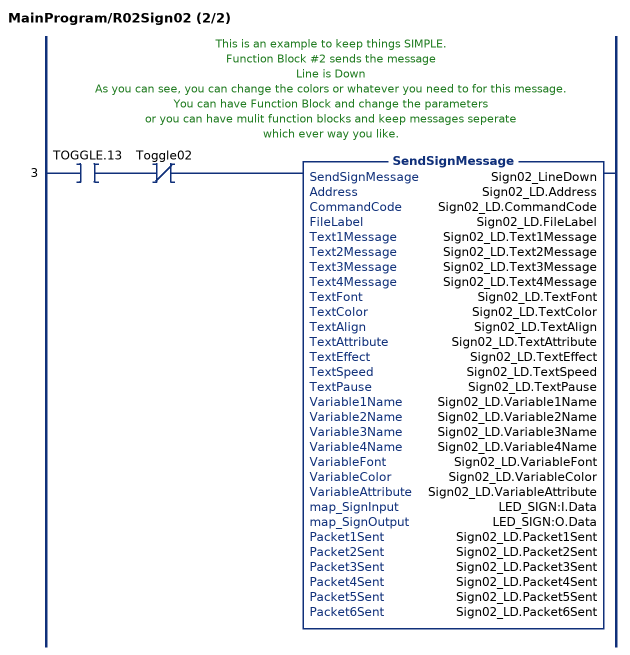
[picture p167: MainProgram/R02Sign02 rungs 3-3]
   // This is an example to keep things SIMPLE.
   // Function Block #2 sends the message
   // Line is Down
   // As you can see, you can change the colors or whatever you need to for this message.
   // You can have Function Block and change the parameters
   // or you can have mulit function blocks and keep messages seperate
   // which ever way you like.
   3: XIC(TOGGLE.13)XIO(Toggle02)SendSignMessage(Sign02_LineDown,Sign02_LD.Address,Sign02_LD.CommandCode,Sign02_LD.FileLabel,Sign02_LD.Text1Message,Sign02_LD.Text2Message,Sign02_LD.Text3Message,Sign02_LD.Text4Message,Sign02_LD.TextFont,Sign02_LD.TextColor,Sign02_LD.TextAlign,Sign02_LD.TextAttribute,Sign02_LD.TextEffect,Sign02_LD.TextSpeed,Sign02_LD.TextPause,Sign02_LD.Variable1Name,Sign02_LD.Variable2Name,Sign02_LD.Variable3Name,Sign02_LD.Variable4Name,Sign02_LD.VariableFont,Sign02_LD.VariableColor,Sign02_LD.VariableAttribute,LED_SIGN:I.Data,LED_SIGN:O.Data,Sign02_LD.Packet1Sent,Sign02_LD.Packet2Sent,Sign02_LD.Packet3Sent,Sign02_LD.Packet4Sent,Sign02_LD.Packet5Sent,Sign02_LD.Packet6Sent);
END_ROUTINE

ROUTINE R03NumSign   (* ladder *)
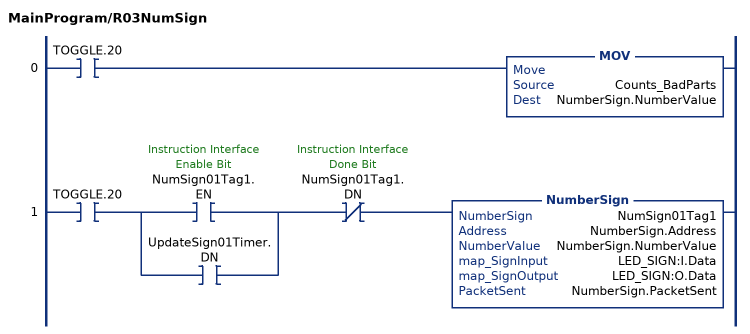
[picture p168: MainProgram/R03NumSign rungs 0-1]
   0: XIC(TOGGLE.20)MOV(Counts_BadParts,NumberSign.NumberValue);
   1: XIC(TOGGLE.20)[XIC(NumSign01Tag1.EN) ,XIC(UpdateSign01Timer.DN) ]XIO(NumSign01Tag1.DN)NumberSign(NumSign01Tag1,NumberSign.Address,NumberSign.NumberValue,LED_SIGN:I.Data,LED_SIGN:O.Data,NumberSign.PacketSent);
END_ROUTINE
END_PROGRAM
